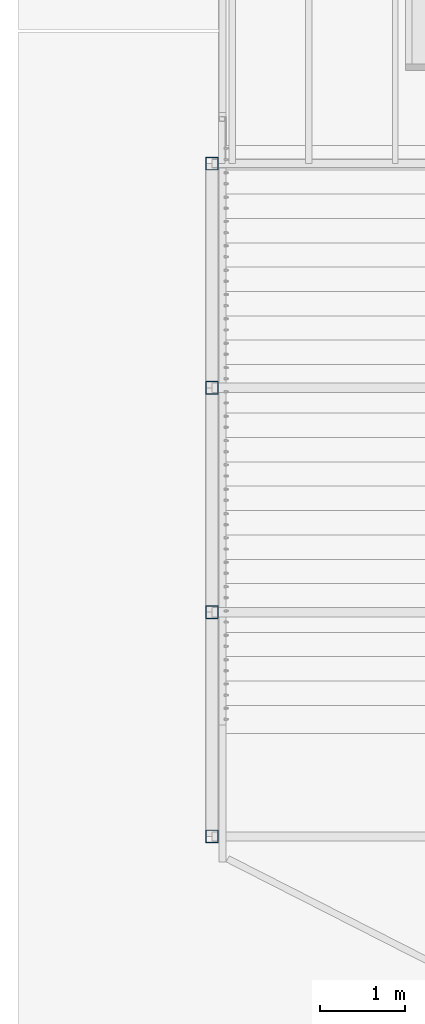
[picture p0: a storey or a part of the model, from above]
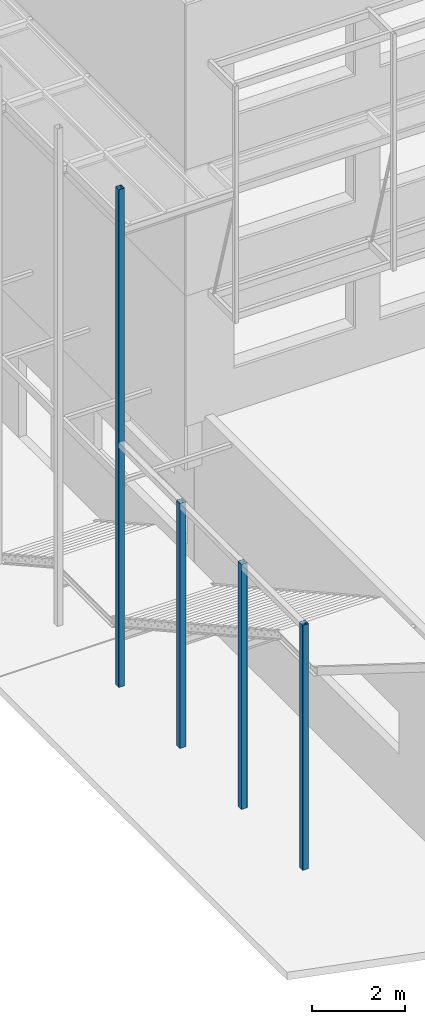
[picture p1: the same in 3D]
Properties of the parts of a building model (IFC2X3), part 1 of 3

# File
Description: ViewDefinition[CoordinationView_V2.0, QuantityTakeOffAddOnView], Option [BaseQuantities:On], Option [GridExport:Off], Option [Assemblies:On], Option [Bolts:On], Option [Rebars:On], Option [PourObjects:Off], Option [Welds:Off], Option [SurfaceTreatments:Off], Option [LocationBy:0], Option [ViewColors:On], Option [SectionedSpine:Off], Option [PropertySets:On], Option [Export all:Off]
File name: Tekla.ifc
Time: 2025-06-02T15:51:15
Author: ETCOMETA\s.laplace
Organization: Structural Designer
Written by: IFC Database Version: Work
Made in: Tekla Structures 2021 Service Pack 13, IFC Export Version: 4.0.0.0 Apr 21 2023

# IfcBuildingStorey, Undefined
In: Undefined
Elevation: 0 mm

# IfcBeam: 160*100 (16)
In: Undefined
Description: 160*100; Material: TIMBER/CHENE
Tekla Commun - Repère de pièce: Po0(?); Repère d'assemblage: Po0(?); Phase: 1402; Classe: 6; Matériau: CHENE; Profil: 160*100; Nom: POUTRE
Tekla Quantités - Hauteur: 160 mm; Largeur: 100 mm
Pset_BeamCommon - LoadBearing: no; Reference: Po0(?)
Name | Niveau bas | Niveau haut | Poids (kg) | Volume (m3) | Surface supérieure totale (m2) | Surface par tonne (m2) | Surface nette (m2) | Longueur (mm) | Length (mm) | OuterSurfaceArea (m2) | NetVolume (m3) | NetWeight (kg)
POUTRE | +156.320 | +156.480 | 278.6 | 0.3 | 1.9 | 36.2 | 10.1 | 19350 | 19350 | 10.094 | 0.3096 | 278.64
POUTRE | +159.620 | +159.780 | 278.6 | 0.3 | 1.9 | 36.2 | 10.1 | 19350 | 19350 | 10.094 | 0.3096 | 278.64
POUTRE | +162.852 | +163.347 | 116.5 | 0.1 | 0 | 36.4 | 4.2 | 8088.5 | 8088.45 | 4.238 | 0.129415 | 116.474
POUTRE | +162.833 | +163.071 | 34.4 | 0 | 0 | 37 | 1.3 | 2390 | 2390 | 1.2748 | 0.03824 | 34.416
POUTRE | +162.935 | +163.349 | 118.1 | 0.1 | 0 | 36.4 | 4.2 | 8200 | 8200 | 4.296 | 0.1312 | 118.08
POUTRE | +162.833 | +163.070 | 36 | 0 | 0 | 37 | 1.3 | 2498.8 | 2498.83 | 1.33139 | 0.0399813 | 35.9832
POUTRE | +162.857 | +163.347 | 116.1 | 0.1 | 0 | 36.4 | 4.2 | 8060 | 8060 | 4.2232 | 0.12896 | 116.064
POUTRE | +156.300 | +156.460 | 28.8 | 0 | 0.2 | 37.2 | 1.1 | 1990 | 1990 | 1.0668 | 0.0318401 | 28.656
POUTRE | +156.320 | +156.480 | 118.1 | 0.1 | 0.8 | 36.4 | 4.2 | 8201 | 8201 | 4.29652 | 0.131216 | 118.094
POUTRE | +156.320 | +156.480 | 118.1 | 0.1 | 0.8 | 36.4 | 4.2 | 8200 | 8200.01 | 4.296 | 0.1312 | 118.08
POUTRE | +162.843 | +163.065 | 28.8 | 0 | 0 | 37.2 | 1.1 | 1990 | 1990 | 1.0668 | 0.0318401 | 28.656
POUTRE | +159.600 | +159.760 | 28.8 | 0 | 0.2 | 37.2 | 1.1 | 1990 | 1990 | 1.0668 | 0.0318401 | 28.656
POUTRE | +159.620 | +159.780 | 118.1 | 0.1 | 0.8 | 36.4 | 4.2 | 8201 | 8201 | 4.29652 | 0.131216 | 118.094
POUTRE | +159.620 | +159.780 | 118.1 | 0.1 | 0.8 | 36.4 | 4.2 | 8200 | 8200.01 | 4.296 | 0.1312 | 118.08
POUTRE | +162.861 | +163.345 | 118.1 | 0.1 | 0 | 36.4 | 4.2 | 8200 | 8200 | 4.296 | 0.1312 | 118.08
POUTRE | +162.933 | +163.347 | 118.1 | 0.1 | 0 | 36.4 | 4.2 | 8200 | 8200 | 4.296 | 0.1312 | 118.08

# IfcBeam: 200*140 (18)
In: Undefined
Description: 200*140; Material: TIMBER/CHENE
Pset_BeamCommon - LoadBearing: no; Reference: Po0(?)
Tekla Commun - Repère de pièce: Po0(?); Repère d'assemblage: Po0(?); Phase: 1402; Classe: 6; Matériau: CHENE; Profil: 200*140; Nom: POUTRE
Tekla Quantités - Volume: 0.1 m3; Surface supérieure totale: 0.5 m2; Surface par tonne: 27.6 m2; Hauteur: 200 mm; Largeur: 140 mm
Name | Niveau bas | Niveau haut | Poids (kg) | Surface nette (m2) | Longueur (mm) = Length (mm) | OuterSurfaceArea (m2) | NetVolume (m3) | NetWeight (kg)
5 x POUTRE | +162.950 | +163.150 | 92.2 | 2.5 | 3660 | 2.5448 | 0.10248 | 92.232
5 x POUTRE | +159.290 | +159.490 | 92.2 | 2.5 | 3660 | 2.5448 | 0.10248 | 92.232
POUTRE | +162.950 | +163.150 | 95.3 | 2.6 | 3780 | 2.6264 | 0.10584 | 95.256
POUTRE | +159.290 | +159.490 | 95.3 | 2.6 | 3780 | 2.6264 | 0.10584 | 95.256
5 x POUTRE | +155.990 | +156.190 | 92.2 | 2.5 | 3660 | 2.5448 | 0.10248 | 92.232
POUTRE | +155.990 | +156.190 | 95.3 | 2.6 | 3780 | 2.6264 | 0.10584 | 95.256

# IfcBeam: 360*160, POUTRE
In: Undefined
Description: 360*160; Material: TIMBER/CHENE
Pset_BeamCommon - LoadBearing: no; Reference: Po0(?)
Tekla Commun - Niveau bas: +164.600; Niveau haut: +164.960; Repère de pièce: Po0(?); Repère d'assemblage: Po0(?); Phase: 1402; Classe: 6; Matériau: CHENE; Profil: 360*160; Nom: POUTRE
Tekla Quantités - Poids: 419.9 kg; Volume: 0.5 m3; Surface supérieure totale: 1.2 m2; Surface par tonne: 20.3 m2; Surface nette: 8.5 m2; Hauteur: 360 mm; Largeur: 160 mm; Longueur: 8100 mm
BaseQuantities - Length: 8100 mm; OuterSurfaceArea: 8.5392 m2; NetVolume: 0.46656 m3; NetWeight: 419.904 kg

# IfcBeam: 360*240 (10)
In: Undefined
Description: 360*240; Material: TIMBER/CHENE
Pset_BeamCommon - LoadBearing: no; Reference: Po0(?)
Tekla Commun - Repère de pièce: Po0(?); Repère d'assemblage: Po0(?); Phase: 1402; Classe: 6; Matériau: CHENE; Profil: 360*240; Nom: POUTRE
Tekla Quantités - Hauteur: 360 mm; Largeur: 240 mm
Name | Niveau bas | Niveau haut | Poids (kg) | Volume (m3) | Surface supérieure totale (m2) | Surface par tonne (m2) | Surface nette (m2) | Longueur (mm) | Length (mm) | OuterSurfaceArea (m2) | NetVolume (m3) | NetWeight (kg)
POUTRE | +156.000 | +156.360 | 1504.7 | 1.7 | 4.6 | 15.5 | 23.4 | 19350 | 19350 | 23.3928 | 1.67184 | 1504.66
POUTRE | +159.300 | +159.660 | 1504.7 | 1.7 | 4.6 | 15.5 | 23.4 | 19350 | 19350 | 23.3928 | 1.67184 | 1504.66
POUTRE | +162.651 | +163.346 | 637.6 | 0.7 | 0 | 15.7 | 10 | 8200 | 8200 | 10.0128 | 0.70848 | 637.632
2 x POUTRE | +162.630 | +163.070 | 201.4 | 0.2 | 0 | 16.3 | 3.3 | 2590 | 2590 | 3.2808 | 0.223776 | 201.398
POUTRE | +162.736 | +163.350 | 637.6 | 0.7 | 0 | 15.7 | 10 | 8200 | 8200 | 10.0128 | 0.70848 | 637.632
POUTRE | +162.657 | +163.346 | 626.7 | 0.7 | 0 | 15.7 | 9.8 | 8060 | 8060 | 9.8448 | 0.696384 | 626.746
POUTRE | +162.640 | +163.068 | 170.4 | 0.2 | 0 | 16.5 | 2.8 | 2191 | 2191.05 | 2.80206 | 0.189307 | 170.376
POUTRE | +162.661 | +163.345 | 637.6 | 0.7 | 0 | 15.7 | 10 | 8200 | 8200 | 10.0128 | 0.70848 | 637.632
POUTRE | +162.734 | +163.347 | 637.6 | 0.7 | 0 | 15.7 | 10 | 8200 | 8200 | 10.0128 | 0.70848 | 637.632

# IfcBeam: 480*240 (2)
In: Undefined
Description: 480*240; Material: TIMBER/CHENE
Pset_BeamCommon - LoadBearing: no; Reference: Po0(?)
Tekla Commun - Repère de pièce: Po0(?); Repère d'assemblage: Po0(?); Phase: 1402; Classe: 6; Matériau: CHENE; Profil: 480*240; Nom: POUTRE
Tekla Quantités - Poids: 1964.7 kg; Volume: 2.2 m3; Surface supérieure totale: 4.5 m2; Surface par tonne: 14 m2; Surface nette: 27.5 m2; Hauteur: 480 mm; Largeur: 240 mm; Longueur: 18950 mm
BaseQuantities - Length: 18950 mm; OuterSurfaceArea: 27.5184 m2; NetVolume: 2.18304 m3; NetWeight: 1964.74 kg
Name | Niveau bas | Niveau haut
POUTRE | +156.000 | +156.480
POUTRE | +159.300 | +159.780

# IfcBeam: 520*140 (6)
In: Undefined
Description: 520*140; Material: TIMBER/CHENE
Pset_BeamCommon - LoadBearing: no; Reference: Po0(?)
Tekla Commun - Niveau bas: +162.950; Niveau haut: +163.470; Repère de pièce: Po0(?); Repère d'assemblage: Po0(?); Phase: 1402; Classe: 6; Matériau: CHENE; Profil: 520*140; Nom: POUTRE
Tekla Quantités - Volume: 0.3 m3; Surface supérieure totale: 0.5 m2; Surface par tonne: 20.8 m2; Hauteur: 520 mm; Largeur: 140 mm
Name | Poids (kg) | Surface nette (m2) | Longueur (mm) = Length (mm) | OuterSurfaceArea (m2) | NetVolume (m3) | NetWeight (kg)
5 x POUTRE | 239.8 | 5 | 3660 | 4.9768 | 0.266448 | 239.803
POUTRE | 247.7 | 5.2 | 3780 | 5.1352 | 0.275184 | 247.666

# IfcBeam: 560*140 (12)
In: Undefined
Description: 560*140; Material: TIMBER/CHENE
Pset_BeamCommon - LoadBearing: no; Reference: Po0(?)
Tekla Commun - Repère de pièce: Po0(?); Repère d'assemblage: Po0(?); Phase: 1402; Classe: 6; Matériau: CHENE; Profil: 560*140; Nom: POUTRE
Tekla Quantités - Volume: 0.3 m3; Surface supérieure totale: 0.5 m2; Surface par tonne: 20.5 m2; Surface nette: 5.3 m2; Hauteur: 560 mm; Largeur: 140 mm
Name | Niveau bas | Niveau haut | Poids (kg) | Longueur (mm) = Length (mm) | OuterSurfaceArea (m2) | NetVolume (m3) | NetWeight (kg)
5 x POUTRE | +159.290 | +159.850 | 258.2 | 3660 | 5.2808 | 0.286944 | 258.25
POUTRE | +159.290 | +159.850 | 266.7 | 3780 | 5.4488 | 0.296352 | 266.717
5 x POUTRE | +155.990 | +156.550 | 258.2 | 3660 | 5.2808 | 0.286944 | 258.25
POUTRE | +155.990 | +156.550 | 266.7 | 3780 | 5.4488 | 0.296352 | 266.717

# IfcBeam: 800*280, POUTRE
In: Undefined
Description: 800*280; Material: TIMBER/CHENE
Pset_BeamCommon - LoadBearing: no; Reference: Po0(?)
Tekla Commun - Niveau bas: +162.400; Niveau haut: +163.200; Repère de pièce: Po0(?); Repère d'assemblage: Po0(?); Phase: 1402; Classe: 6; Matériau: CHENE; Profil: 800*280; Nom: POUTRE
Tekla Quantités - Poids: 1633 kg; Volume: 1.7 m3; Surface supérieure totale: 2.3 m2; Surface par tonne: 11 m2; Surface nette: 17.9 m2; Hauteur: 800 mm; Largeur: 280 mm; Longueur: 8100 mm
BaseQuantities - Length: 8100 mm; OuterSurfaceArea: 17.944 m2; NetVolume: 1.8144 m3; NetWeight: 1632.96 kg

# IfcBeam: IPE140 (47)
In: Undefined
Description: IPE140; Material: STEEL/S275JR
Pset_BeamCommon - LoadBearing: no; Reference: A0(?)
Tekla Commun - Repère de pièce: A0(?); Repère d'assemblage: A0(?); Phase: 301; Classe: 3; Matériau: S275JR; Profil: IPE140
Tekla Quantités - Volume: 0 m3; Surface par tonne: 42.8 m2; Hauteur: 140 mm; Largeur: 73 mm
Name | Niveau bas | Niveau haut | Nom | Poids (kg) | Surface supérieure totale (m2) | Surface nette (m2) | Longueur (mm) | Length (mm) | OuterSurfaceArea (m2) | NetVolume (m3) | NetWeight (kg)
SOLIVE | +150.730 | +150.870 | SOLIVE | 16.8 | 0.1 | 0.7 | 1307.2 | 1307.16 | 0.720245 | 0.00209216 | 16.4235
POUTRE | +148.335 | +148.475 | POUTRE | 22.4 | 0.1 | 0.9 | 1740 | 1740 | 0.95874 | 0.00278494 | 21.8618
POUTRE | +148.335 | +148.475 | POUTRE | 22.4 | 0.1 | 0.9 | 1747.5 | 1747.5 | 0.962872 | 0.00279694 | 21.956
2 x SOLIVE | +159.830 | +159.970 | SOLIVE | 33.9 | 0.2 | 1.4 | 2625 | 2625 | 1.44637 | 0.00420142 | 32.9811
4 x SOLIVE | +156.530 | +156.670 | SOLIVE | 33.9 | 0.2 | 1.4 | 2625 | 2625 | 1.44637 | 0.00420142 | 32.9811
SOLIVE | +156.530 | +156.670 | SOLIVE | 32.8 | 0.2 | 1.4 | 2550 | 2550 | 1.40505 | 0.00408138 | 32.0388
4 x POUTRE | +156.530 | +156.670 | POUTRE | 33.9 | 0.2 | 1.4 | 2625 | 2625 | 1.44637 | 0.00420142 | 32.9811
2 x POUTRE | +156.530 | +156.670 | POUTRE | 39.9 | 0.2 | 1.7 | 3100 | 3100 | 1.7081 | 0.00496167 | 38.9491
8 x SOLIVE | +153.230 | +153.370 | SOLIVE | 33.9 | 0.2 | 1.4 | 2625 | 2625 | 1.44637 | 0.00420142 | 32.9811
4 x POUTRE | +153.230 | +153.370 | POUTRE | 33.9 | 0.2 | 1.4 | 2625 | 2625 | 1.44637 | 0.00420142 | 32.9811
2 x POUTRE | +153.230 | +153.370 | POUTRE | 39.9 | 0.2 | 1.7 | 3100 | 3100 | 1.7081 | 0.00496167 | 38.9491
SOLIVE | +149.930 | +150.070 | SOLIVE | 26 | 0.1 | 1.1 | 2020 | 2020 | 1.11302 | 0.00323309 | 25.3798
SOLIVE | +149.930 | +150.070 | SOLIVE | 33.9 | 0.2 | 1.4 | 2625 | 2625 | 1.44637 | 0.00420142 | 32.9811
SOLIVE | +149.930 | +150.070 | SOLIVE | 32.8 | 0.2 | 1.4 | 2550 | 2550 | 1.40505 | 0.00408138 | 32.0388
2 x SOLIVE | +159.830 | +159.970 | SOLIVE | 33.9 | 0.2 | 1.4 | 2626 | 2626 | 1.44693 | 0.00420302 | 32.9937
SOLIVE | +159.830 | +159.970 | SOLIVE | 31.5 | 0.2 | 1.4 | 2447 | 2447 | 1.3483 | 0.00391652 | 30.7447
SOLIVE | +159.830 | +159.970 | SOLIVE | 28.8 | 0.2 | 1.3 | 2238 | 2238 | 1.23314 | 0.00358201 | 28.1188
3 x SOLIVE | +150.730 | +150.870 | SOLIVE | 33.9 | 0.2 | 1.4 | 2625 | 2625 | 1.44637 | 0.00420142 | 32.9811
SOLIVE | +156.530 | +156.670 | SOLIVE | 33.4 | 0.2 | 1.4 | 2592.9 | 2592.9 | 1.42869 | 0.00407696 | 32.0041
SOLIVE | +156.530 | +156.670 | SOLIVE | 32.6 | 0.2 | 1.4 | 2530 | 2530 | 1.39403 | 0.00404937 | 31.7875
SOLIVE | +156.530 | +156.670 | SOLIVE | 39.9 | 0.2 | 1.7 | 3100 | 3100 | 1.7081 | 0.00496167 | 38.9491
SOLIVE | +156.530 | +156.670 | SOLIVE | 39.7 | 0.2 | 1.7 | 3087 | 3087.05 | 1.70096 | 0.00491172 | 38.557
SOLIVE | +156.530 | +156.670 | SOLIVE | 33.4 | 0.2 | 1.4 | 2592.9 | 2593.05 | 1.42877 | 0.00408009 | 32.0287
2 x SOLIVE | +153.230 | +153.370 | SOLIVE | 39.9 | 0.2 | 1.7 | 3100 | 3100 | 1.7081 | 0.00496167 | 38.9491

# IfcBeam: IPE220 (22)
In: Undefined
Description: IPE220; Material: STEEL/S275JR
Pset_BeamCommon - LoadBearing: no
Tekla Commun - Repère d'assemblage: A0(?); Classe: 3; Matériau: S275JR; Profil: IPE220
Tekla Quantités - Volume: 0 m3; Surface par tonne: 32.3 m2; Hauteur: 220 mm; Largeur: 110 mm
Name | Reference = Repère de pièce | Niveau bas | Niveau haut | Phase | Nom | Poids (kg) | Surface supérieure totale (m2) | Surface nette (m2) | Longueur (mm) | Length (mm) | OuterSurfaceArea (m2) | NetVolume (m3) | NetWeight (kg)
3 x POUTRE | A0(?) | +156.450 | +156.670 | 301 | POUTRE | 53 | 0.2 | 1.7 | 2020 | 2020 | 1.71296 | 0.00649115 | 50.9555
3 x POUTRE | A0(?) | +153.150 | +153.370 | 301 | POUTRE | 53 | 0.2 | 1.7 | 2020 | 2020 | 1.71296 | 0.00649115 | 50.9555
POUTRE | A0(?) | +148.955 | +149.175 | 303 | POUTRE | 71.7 | 0.3 | 2.5 | 2733.4 | 2733.43 | 2.31795 | 0.00878371 | 68.9521
POUTRE | A0(?) | +152.110 | +152.330 | 303 | POUTRE | 71.7 | 0.3 | 2.5 | 2733.4 | 2733.43 | 2.31795 | 0.00878371 | 68.9521
POUTRE | A0(?) | +150.645 | +150.865 | 303 | POUTRE | 71.7 | 0.3 | 2.5 | 2733.4 | 2733.43 | 2.31795 | 0.00878371 | 68.9521
POUTRE | A0(?) | +149.180 | +149.400 | 303 | POUTRE | 71.7 | 0.3 | 2.5 | 2733.4 | 2733.43 | 2.31795 | 0.00878371 | 68.9521
POUTRE | A0(?) | +153.150 | +153.370 | 303 | POUTRE | 71.7 | 0.3 | 2.5 | 2733.4 | 2733.43 | 2.31795 | 0.00878371 | 68.9521
CONSOLE | A0(?) | +159.750 | +159.970 | 301 | CONSOLE | 73.5 | 0.3 | 2.5 | 2803.4 | 2803.43 | 2.37731 | 0.00900865 | 70.7179
3 x CONSOLE | A0(?) | +159.750 | +159.970 | 303 | CONSOLE | 71.7 | 0.3 | 2.5 | 2735 | 2735 | 2.31928 | 0.00878876 | 68.9918
SOLIVE | 0(?) | +150.650 | +150.870 | 301 | SOLIVE | 56.9 | 0.2 | 2 | 2170 | 2170 | 1.84016 | 0.00697316 | 54.7393
SOLIVE | A0(?) | +156.450 | +156.670 | 301 | SOLIVE | 54.9 | 0.2 | 1.7 | 2095 | 2095 | 1.77656 | 0.00673216 | 52.8474
SOLIVE | A0(?) | +156.450 | +156.670 | 301 | SOLIVE | 53 | 0.2 | 1.7 | 2020 | 2020 | 1.71296 | 0.00649115 | 50.9555
SOLIVE | 0(?) | +156.450 | +156.670 | 301 | SOLIVE | 52.4 | 0.2 | 1.7 | 2000 | 2000 | 1.696 | 0.00642688 | 50.451
2 x SOLIVE | A0(?) | +153.150 | +153.370 | 301 | SOLIVE | 54.9 | 0.2 | 1.7 | 2095 | 2095 | 1.77656 | 0.00673216 | 52.8474
SOLIVE | A0(?) | +153.150 | +153.370 | 301 | SOLIVE | 53 | 0.2 | 1.7 | 2020 | 2020 | 1.71296 | 0.00649115 | 50.9555

# IfcBeam: IPE240 (12)
In: Undefined
Description: IPE240; Material: STEEL/S275JR
Pset_BeamCommon - LoadBearing: no; Reference: 0(?)
Tekla Commun - Repère de pièce: 0(?); Phase: 301; Classe: 3; Matériau: S275JR; Profil: IPE240
Tekla Quantités - Volume: 0 m3; Surface par tonne: 30 m2; Hauteur: 240 mm; Largeur: 120 mm
Name | Niveau bas | Niveau haut | Repère d'assemblage | Nom | Poids (kg) | Surface supérieure totale (m2) | Surface nette (m2) | Longueur (mm) | Length (mm) | OuterSurfaceArea (m2) | NetVolume (m3) | NetWeight (kg)
CONSOLE | +159.730 | +159.970 | A0(?) | CONSOLE | 60.9 | 0.2 | 2 | 1985 | 1985 | 1.83017 | 0.00738118 | 57.9423
2 x CONSOLE | +156.430 | +156.670 | A0(?) | CONSOLE | 60.9 | 0.2 | 2 | 1985 | 1985 | 1.83017 | 0.00738118 | 57.9423
2 x CONSOLE | +153.130 | +153.370 | A0(?) | CONSOLE | 60.9 | 0.2 | 2 | 1985 | 1985 | 1.83017 | 0.00738118 | 57.9423
CONSOLE | +149.830 | +150.070 | A0(?) | CONSOLE | 58.6 | 0.2 | 1.7 | 1910 | 1910 | 1.76102 | 0.0071023 | 55.753
SOLIVE | +159.730 | +159.970 | A0(?) | SOLIVE | 62.4 | 0.2 | 2 | 2033.6 | 2033.57 | 1.87495 | 0.00756179 | 59.36
SOLIVE | +150.630 | +150.870 | P0(?) | SOLIVE | 74.7 | 0.3 | 2.3 | 2435 | 2435 | 2.24507 | 0.0090545 | 71.0778
SOLIVE | +156.430 | +156.670 | A0(?) | SOLIVE | 61.4 | 0.2 | 2 | 2000 | 2000 | 1.844 | 0.00743696 | 58.3801
SOLIVE | +156.430 | +156.670 | P0(?) | SOLIVE | 59.5 | 0.2 | 1.7 | 1938.6 | 1938.57 | 1.78736 | 0.00720853 | 56.587
SOLIVE | +153.130 | +153.370 | A0(?) | SOLIVE | 61.4 | 0.2 | 2 | 2000 | 2000 | 1.844 | 0.00743696 | 58.3801
SOLIVE | +153.130 | +153.370 | P0(?) | SOLIVE | 59.8 | 0.2 | 2 | 1948.6 | 1948.57 | 1.79658 | 0.00724572 | 56.8789

# IfcBeam: L100*10 (7)
In: Undefined
Description: L100*10; Material: STEEL/S235JR
Pset_BeamCommon - LoadBearing: no
Tekla Commun - Phase: 301; Classe: 3; Matériau: S235JR; Profil: L100*10; Nom: CORNIERE
Tekla Quantités - Volume: 0 m3; Surface supérieure totale: 0 m2; Surface par tonne: 25.9 m2; Surface nette: 0.1 m2; Hauteur: 100 mm; Largeur: 100 mm
Name | Reference = Repère de pièce | Niveau bas | Niveau haut | Repère d'assemblage | Poids (kg) | Longueur (mm) = Length (mm) | OuterSurfaceArea (m2) | NetVolume (m3) | NetWeight (kg)
CORNIERE | A0(?) | +156.480 | +156.640 | A0(?) | 2.4 | 160 | 0.0624 | 0.000304 | 2.3864
4 x CORNIERE | 0(?) | +156.480 | +156.640 | P0(?) | 2.4 | 160 | 0.0624 | 0.000304 | 2.3864
CORNIERE | 0(?) | +156.420 | +156.620 | P0(?) | 3 | 200 | 0.078 | 0.00038 | 2.983
CORNIERE | 0(?) | +159.800 | +159.960 | A0(?) | 2.4 | 160 | 0.0624 | 0.000304 | 2.3864

# IfcBeam: L50*5 (61)
In: Undefined
Description: L50*5
Pset_BeamCommon - LoadBearing: no; Reference: A0(?)
Tekla Commun - Repère de pièce: A0(?); Repère d'assemblage: A0(?); Phase: 301; Classe: 3; Profil: L50*5; Nom: STAB
Tekla Quantités - Volume: 0 m3; Surface par tonne: 51.5 m2; Hauteur: 50 mm; Largeur: 50 mm
Name | Material | Niveau bas | Niveau haut | Matériau | Poids (kg) | Surface supérieure totale (m2) | Surface nette (m2) | Longueur (mm) | Length (mm) | OuterSurfaceArea (m2) | NetVolume (m3) | NetWeight (kg)
STAB | STEEL/S275JR | +156.458 | +156.508 | S275JR | 5.7 | 0 | 0.4 | 1520.7 | 1520.75 | 0.295025 | 0.000722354 | 5.67048
STAB | STEEL/S275JR | +156.458 | +156.508 | S275JR | 5.2 | 0 | 0.4 | 1387.7 | 1387.65 | 0.269205 | 0.000659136 | 5.17422
STAB | STEEL/S275JR | +156.458 | +156.508 | S275JR | 5.5 | 0 | 0.4 | 1471.4 | 1471.37 | 0.285446 | 0.0006989 | 5.48637
STAB | STEEL/S275JR | +150.680 | +150.730 | S275JR | 8.3 | 0.1 | 0.4 | 2213.6 | 2213.59 | 0.429437 | 0.00105146 | 8.25394
2 x STAB | STEEL/S235JR | +159.780 | +159.830 | S235JR | 12.7 | 0.2 | 0.7 | 3372 | 3372 | 0.654168 | 0.0016017 | 12.5734
4 x STAB | STEEL/S235JR | +156.480 | +156.530 | S235JR | 12.7 | 0.2 | 0.7 | 3372 | 3372 | 0.654168 | 0.0016017 | 12.5734
2 x STAB | STEEL/S235JR | +156.480 | +156.530 | S235JR | 13.1 | 0.2 | 0.7 | 3463.9 | 3463.94 | 0.672005 | 0.00164537 | 12.9162
STAB | STEEL/S235JR | +156.507 | +156.557 | S235JR | 13.1 | 0.2 | 0.7 | 3463.9 | 3463.94 | 0.672005 | 0.00164537 | 12.9162
STAB | STEEL/S235JR | +156.507 | +156.557 | S235JR | 12.3 | 0.2 | 0.7 | 3266.8 | 3266.82 | 0.633764 | 0.00155174 | 12.1812
4 x STAB | STEEL/S235JR | +156.480 | +156.530 | S235JR | 14.3 | 0.2 | 0.7 | 3784 | 3784.03 | 0.734102 | 0.00179742 | 14.1097
4 x STAB | STEEL/S235JR | +153.180 | +153.230 | S235JR | 12.7 | 0.2 | 0.7 | 3372 | 3372 | 0.654168 | 0.0016017 | 12.5734
4 x STAB | STEEL/S235JR | +153.180 | +153.230 | S235JR | 13.1 | 0.2 | 0.7 | 3463.9 | 3463.94 | 0.672005 | 0.00164537 | 12.9162
4 x STAB | STEEL/S235JR | +153.180 | +153.230 | S235JR | 14.3 | 0.2 | 0.7 | 3784 | 3784.03 | 0.734102 | 0.00179742 | 14.1097
2 x STAB | STEEL/S235JR | +149.880 | +149.930 | S235JR | 12.7 | 0.2 | 0.7 | 3372 | 3372 | 0.654168 | 0.0016017 | 12.5734
2 x STAB | STEEL/S275JR | +159.780 | +159.830 | S275JR | 12.7 | 0.2 | 0.7 | 3372 | 3372 | 0.654168 | 0.0016017 | 12.5734
2 x STAB | STEEL/S275JR | +150.680 | +150.730 | S275JR | 12.7 | 0.2 | 0.7 | 3372 | 3372 | 0.654168 | 0.0016017 | 12.5734
2 x STAB | STEEL/S275JR | +156.480 | +156.530 | S275JR | 12.7 | 0.2 | 0.7 | 3372 | 3372 | 0.654168 | 0.0016017 | 12.5734
STAB | STEEL/S275JR | +156.458 | +156.508 | S275JR | 11.2 | 0 | 0.7 | 3010.5 | 3010.48 | 0.584032 | 0.00142998 | 11.2253
4 x STAB | STEEL/S275JR | +153.180 | +153.230 | S275JR | 12.7 | 0.2 | 0.7 | 3372 | 3372 | 0.654168 | 0.0016017 | 12.5734
2 x STAB | STEEL/S275JR | +150.680 | +150.730 | S275JR | 13.1 | 0.2 | 0.7 | 3463.9 | 3463.94 | 0.672005 | 0.00164537 | 12.9162
STAB | STEEL/S275JR | +156.458 | +156.508 | S275JR | 11 | 0 | 0.7 | 2908.9 | 2908.88 | 0.564323 | 0.00138172 | 10.8465
STAB | STEEL/S275JR | +156.458 | +156.508 | S275JR | 5.3 | 0 | 0.4 | 1395.9 | 1395.86 | 0.270796 | 0.000663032 | 5.2048
2 x STAB | STEEL/S275JR | +156.480 | +156.530 | S275JR | 13.1 | 0.2 | 0.7 | 3463.9 | 3463.94 | 0.672005 | 0.00164537 | 12.9162
4 x STAB | STEEL/S275JR | +156.480 | +156.530 | S275JR | 14.3 | 0.2 | 0.7 | 3784 | 3784.03 | 0.734102 | 0.00179742 | 14.1097
4 x STAB | STEEL/S275JR | +153.180 | +153.230 | S275JR | 13.1 | 0.2 | 0.7 | 3463.9 | 3463.94 | 0.672005 | 0.00164537 | 12.9162
4 x STAB | STEEL/S275JR | +153.180 | +153.230 | S275JR | 14.3 | 0.2 | 0.7 | 3784 | 3784.03 | 0.734102 | 0.00179742 | 14.1097

# IfcBeam: L80*8 (9)
In: Undefined
Description: L80*8; Material: STEEL/S235JR
Tekla Commun - Repère de pièce: 0(?); Classe: 99; Matériau: S235JR; Profil: L80*8; Nom: CORNIERE
Tekla Quantités - Poids: 1.4 kg; Volume: 0 m3; Surface supérieure totale: 0 m2; Surface par tonne: 32.2 m2; Surface nette: 0.1 m2; Hauteur: 80 mm; Largeur: 80 mm; Longueur: 150 mm
Pset_BeamCommon - LoadBearing: no; Reference: 0(?)
BaseQuantities - Length: 150 mm; OuterSurfaceArea: 0.04665 m2; NetVolume: 0.0001824 m3; NetWeight: 1.43184 kg
Name | Niveau bas | Niveau haut | Repère d'assemblage | Phase
CORNIERE | +156.485 | +156.635 | L0(?) | 301
CORNIERE | +156.485 | +156.635 | A0(?) | 303
CORNIERE | +149.885 | +150.035 | A0(?) | 301
2 x CORNIERE | +153.185 | +153.335 | A0(?) | 301
2 x CORNIERE | +156.485 | +156.635 | A0(?) | 301
CORNIERE | +150.685 | +150.835 | A0(?) | 301
CORNIERE | +159.785 | +159.935 | A0(?) | 301

# IfcBeam: PL10*10 (212)
In: Undefined
Description: PL10*10; Material: STEEL/S235JR
Pset_BeamCommon - LoadBearing: no; Reference: 0(?)
Tekla Commun - Repère de pièce: 0(?); Repère d'assemblage: GC0(?); Phase: 601; Classe: 13; Matériau: S235JR; Profil: PL10*10; Nom: LISSE
Tekla Quantités - Poids: 0.7 kg; Volume: 0 m3; Surface supérieure totale: 0 m2; Surface nette: 0 m2; Hauteur: 10 mm; Largeur: 10 mm
Name | Niveau bas | Niveau haut | Surface par tonne (m2) | Longueur (mm) | Length (mm) | OuterSurfaceArea (m2) | NetVolume (m3) | NetWeight (kg)
32 x LISSE | +160.120 | +160.990 | 51.2 | 870 | 870 | 0.035 | 0.000087 | 0.68295
90 x LISSE | +156.820 | +157.690 | 51.2 | 870 | 870 | 0.035 | 0.000087 | 0.68295
LISSE | +159.950 | +160.775 | 51.3 | 825.6 | 825.551 | 0.0330295 | 0.0000820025 | 0.643719
LISSE | +159.889 | +160.715 | 51.3 | 825.6 | 825.551 | 0.0330295 | 0.0000820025 | 0.643719
LISSE | +156.985 | +157.810 | 51.3 | 825.6 | 825.551 | 0.0330295 | 0.0000820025 | 0.643719
LISSE | +157.045 | +157.871 | 51.3 | 825.6 | 825.551 | 0.0330295 | 0.0000820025 | 0.643719
LISSE | +157.106 | +157.932 | 51.3 | 825.6 | 825.551 | 0.0330295 | 0.0000820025 | 0.643719
LISSE | +157.167 | +157.993 | 51.3 | 825.6 | 825.551 | 0.0330295 | 0.0000820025 | 0.643719
LISSE | +157.228 | +158.053 | 51.3 | 825.6 | 825.551 | 0.0330295 | 0.0000820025 | 0.643719
LISSE | +157.289 | +158.114 | 51.3 | 825.6 | 825.551 | 0.0330295 | 0.0000820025 | 0.643719
LISSE | +157.349 | +158.175 | 51.3 | 825.6 | 825.551 | 0.0330295 | 0.0000820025 | 0.643719
LISSE | +157.410 | +158.236 | 51.3 | 825.6 | 825.551 | 0.0330295 | 0.0000820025 | 0.643719
LISSE | +157.471 | +158.296 | 51.3 | 825.6 | 825.551 | 0.0330295 | 0.0000820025 | 0.643719
LISSE | +157.592 | +158.418 | 51.3 | 825.6 | 825.551 | 0.0330295 | 0.0000820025 | 0.643719
LISSE | +157.653 | +158.479 | 51.3 | 825.6 | 825.551 | 0.0330295 | 0.0000820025 | 0.643719
LISSE | +157.714 | +158.540 | 51.3 | 825.6 | 825.551 | 0.0330295 | 0.0000820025 | 0.643719
LISSE | +157.775 | +158.600 | 51.3 | 825.6 | 825.551 | 0.0330295 | 0.0000820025 | 0.643719
LISSE | +157.836 | +158.661 | 51.3 | 825.6 | 825.551 | 0.0330295 | 0.0000820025 | 0.643719
LISSE | +157.896 | +158.722 | 51.3 | 825.6 | 825.551 | 0.0330295 | 0.0000820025 | 0.643719
LISSE | +157.957 | +158.783 | 51.3 | 825.6 | 825.551 | 0.0330295 | 0.0000820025 | 0.643719
LISSE | +158.018 | +158.844 | 51.3 | 825.6 | 825.551 | 0.0330295 | 0.0000820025 | 0.643719
LISSE | +158.079 | +158.904 | 51.3 | 825.6 | 825.551 | 0.0330295 | 0.0000820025 | 0.643719
LISSE | +158.200 | +159.026 | 51.3 | 825.6 | 825.551 | 0.0330295 | 0.0000820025 | 0.643719
LISSE | +158.261 | +159.087 | 51.3 | 825.6 | 825.551 | 0.0330295 | 0.0000820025 | 0.643719
LISSE | +158.322 | +159.148 | 51.3 | 825.6 | 825.551 | 0.0330295 | 0.0000820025 | 0.643719
LISSE | +158.383 | +159.208 | 51.3 | 825.6 | 825.551 | 0.0330295 | 0.0000820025 | 0.643719
LISSE | +158.444 | +159.269 | 51.3 | 825.6 | 825.551 | 0.0330295 | 0.0000820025 | 0.643719
LISSE | +158.504 | +159.330 | 51.3 | 825.6 | 825.551 | 0.0330295 | 0.0000820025 | 0.643719
LISSE | +158.565 | +159.391 | 51.3 | 825.6 | 825.551 | 0.0330295 | 0.0000820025 | 0.643719
LISSE | +158.626 | +159.451 | 51.3 | 825.6 | 825.551 | 0.0330295 | 0.0000820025 | 0.643719
LISSE | +158.687 | +159.512 | 51.3 | 825.6 | 825.551 | 0.0330295 | 0.0000820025 | 0.643719
LISSE | +158.808 | +159.634 | 51.3 | 825.6 | 825.551 | 0.0330295 | 0.0000820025 | 0.643719
LISSE | +158.869 | +159.695 | 51.3 | 825.6 | 825.551 | 0.0330295 | 0.0000820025 | 0.643719
LISSE | +158.930 | +159.755 | 51.3 | 825.6 | 825.551 | 0.0330295 | 0.0000820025 | 0.643719
LISSE | +158.991 | +159.816 | 51.3 | 825.6 | 825.551 | 0.0330295 | 0.0000820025 | 0.643719
LISSE | +159.051 | +159.877 | 51.3 | 825.6 | 825.551 | 0.0330295 | 0.0000820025 | 0.643719
LISSE | +159.112 | +159.938 | 51.3 | 825.6 | 825.551 | 0.0330295 | 0.0000820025 | 0.643719
LISSE | +159.173 | +159.999 | 51.3 | 825.6 | 825.551 | 0.0330295 | 0.0000820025 | 0.643719
LISSE | +159.234 | +160.059 | 51.3 | 825.6 | 825.551 | 0.0330295 | 0.0000820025 | 0.643719
LISSE | +159.295 | +160.120 | 51.3 | 825.6 | 825.551 | 0.0330295 | 0.0000820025 | 0.643719
LISSE | +159.416 | +160.242 | 51.3 | 825.6 | 825.551 | 0.0330295 | 0.0000820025 | 0.643719
LISSE | +159.477 | +160.303 | 51.3 | 825.6 | 825.551 | 0.0330295 | 0.0000820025 | 0.643719
LISSE | +159.538 | +160.363 | 51.3 | 825.6 | 825.551 | 0.0330295 | 0.0000820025 | 0.643719
LISSE | +159.599 | +160.424 | 51.3 | 825.6 | 825.551 | 0.0330295 | 0.0000820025 | 0.643719
LISSE | +159.659 | +160.485 | 51.3 | 825.6 | 825.551 | 0.0330295 | 0.0000820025 | 0.643719
LISSE | +159.720 | +160.546 | 51.3 | 825.6 | 825.551 | 0.0330295 | 0.0000820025 | 0.643719
LISSE | +159.781 | +160.606 | 51.3 | 825.6 | 825.551 | 0.0330295 | 0.0000820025 | 0.643719
LISSE | +159.842 | +160.667 | 51.3 | 825.6 | 825.551 | 0.0330295 | 0.0000820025 | 0.643719
LISSE | +159.902 | +160.728 | 51.3 | 825.6 | 825.551 | 0.0330295 | 0.0000820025 | 0.643719
LISSE | +159.828 | +160.654 | 51.3 | 825.6 | 825.551 | 0.0330295 | 0.0000820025 | 0.643719
LISSE | +159.767 | +160.593 | 51.3 | 825.6 | 825.551 | 0.0330295 | 0.0000820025 | 0.643719
LISSE | +159.707 | +160.532 | 51.3 | 825.6 | 825.551 | 0.0330295 | 0.0000820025 | 0.643719
LISSE | +159.646 | +160.471 | 51.3 | 825.6 | 825.551 | 0.0330295 | 0.0000820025 | 0.643719
LISSE | +159.585 | +160.411 | 51.3 | 825.6 | 825.551 | 0.0330295 | 0.0000820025 | 0.643719
LISSE | +159.524 | +160.350 | 51.3 | 825.6 | 825.551 | 0.0330295 | 0.0000820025 | 0.643719
LISSE | +159.463 | +160.289 | 51.3 | 825.6 | 825.551 | 0.0330295 | 0.0000820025 | 0.643719
LISSE | +159.342 | +160.167 | 51.3 | 825.6 | 825.551 | 0.0330295 | 0.0000820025 | 0.643719
LISSE | +159.281 | +160.107 | 51.3 | 825.6 | 825.551 | 0.0330295 | 0.0000820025 | 0.643719
LISSE | +159.220 | +160.046 | 51.3 | 825.6 | 825.551 | 0.0330295 | 0.0000820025 | 0.643719
LISSE | +159.160 | +159.985 | 51.3 | 825.6 | 825.551 | 0.0330295 | 0.0000820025 | 0.643719
LISSE | +159.099 | +159.924 | 51.3 | 825.6 | 825.551 | 0.0330295 | 0.0000820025 | 0.643719
LISSE | +159.038 | +159.863 | 51.3 | 825.6 | 825.551 | 0.0330295 | 0.0000820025 | 0.643719
LISSE | +158.977 | +159.803 | 51.3 | 825.6 | 825.551 | 0.0330295 | 0.0000820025 | 0.643719
LISSE | +158.916 | +159.742 | 51.3 | 825.6 | 825.551 | 0.0330295 | 0.0000820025 | 0.643719
LISSE | +158.856 | +159.681 | 51.3 | 825.6 | 825.551 | 0.0330295 | 0.0000820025 | 0.643719
LISSE | +158.734 | +159.560 | 51.3 | 825.6 | 825.551 | 0.0330295 | 0.0000820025 | 0.643719
LISSE | +158.673 | +159.499 | 51.3 | 825.6 | 825.551 | 0.0330295 | 0.0000820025 | 0.643719
LISSE | +158.612 | +159.438 | 51.3 | 825.6 | 825.551 | 0.0330295 | 0.0000820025 | 0.643719
LISSE | +158.552 | +159.377 | 51.3 | 825.6 | 825.551 | 0.0330295 | 0.0000820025 | 0.643719
LISSE | +158.491 | +159.316 | 51.3 | 825.6 | 825.551 | 0.0330295 | 0.0000820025 | 0.643719
LISSE | +158.430 | +159.256 | 51.3 | 825.6 | 825.551 | 0.0330295 | 0.0000820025 | 0.643719
LISSE | +158.369 | +159.195 | 51.3 | 825.6 | 825.551 | 0.0330295 | 0.0000820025 | 0.643719
LISSE | +158.308 | +159.134 | 51.3 | 825.6 | 825.551 | 0.0330295 | 0.0000820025 | 0.643719
LISSE | +158.248 | +159.073 | 51.3 | 825.6 | 825.551 | 0.0330295 | 0.0000820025 | 0.643719
LISSE | +158.126 | +158.952 | 51.3 | 825.6 | 825.551 | 0.0330295 | 0.0000820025 | 0.643719
LISSE | +158.065 | +158.891 | 51.3 | 825.6 | 825.551 | 0.0330295 | 0.0000820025 | 0.643719
LISSE | +158.005 | +158.830 | 51.3 | 825.6 | 825.551 | 0.0330295 | 0.0000820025 | 0.643719
LISSE | +157.944 | +158.769 | 51.3 | 825.6 | 825.551 | 0.0330295 | 0.0000820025 | 0.643719
LISSE | +157.883 | +158.708 | 51.3 | 825.6 | 825.551 | 0.0330295 | 0.0000820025 | 0.643719
LISSE | +157.822 | +158.648 | 51.3 | 825.6 | 825.551 | 0.0330295 | 0.0000820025 | 0.643719
LISSE | +157.761 | +158.587 | 51.3 | 825.6 | 825.551 | 0.0330295 | 0.0000820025 | 0.643719
LISSE | +157.701 | +158.526 | 51.3 | 825.6 | 825.551 | 0.0330295 | 0.0000820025 | 0.643719
LISSE | +157.640 | +158.465 | 51.3 | 825.6 | 825.551 | 0.0330295 | 0.0000820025 | 0.643719
LISSE | +157.518 | +158.344 | 51.3 | 825.6 | 825.551 | 0.0330295 | 0.0000820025 | 0.643719
LISSE | +157.457 | +158.283 | 51.3 | 825.6 | 825.551 | 0.0330295 | 0.0000820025 | 0.643719
LISSE | +157.397 | +158.222 | 51.3 | 825.6 | 825.551 | 0.0330295 | 0.0000820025 | 0.643719
LISSE | +157.336 | +158.161 | 51.3 | 825.6 | 825.551 | 0.0330295 | 0.0000820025 | 0.643719
LISSE | +157.275 | +158.101 | 51.3 | 825.6 | 825.551 | 0.0330295 | 0.0000820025 | 0.643719
LISSE | +157.214 | +158.040 | 51.3 | 825.6 | 825.551 | 0.0330295 | 0.0000820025 | 0.643719
LISSE | +157.153 | +157.979 | 51.3 | 825.6 | 825.551 | 0.0330295 | 0.0000820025 | 0.643719
LISSE | +157.093 | +157.918 | 51.3 | 825.6 | 825.551 | 0.0330295 | 0.0000820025 | 0.643719
LISSE | +157.032 | +157.857 | 51.3 | 825.6 | 825.551 | 0.0330295 | 0.0000820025 | 0.643719

# IfcBeam: PL10*50 (10)
In: Undefined
Description: PL10*50; Material: STEEL/S235JR
Pset_BeamCommon - LoadBearing: no; Reference: 0(?)
Tekla Commun - Repère de pièce: 0(?); Repère d'assemblage: GC0(?); Phase: 601; Classe: 13; Matériau: S235JR; Profil: PL10*50
Tekla Quantités - Volume: 0 m3; Surface nette: 0.4 m2; Hauteur: 50 mm; Largeur: 10 mm
Name | Niveau bas | Niveau haut | Nom | Poids (kg) | Surface supérieure totale (m2) | Surface par tonne (m2) | Longueur (mm) = Length (mm) | OuterSurfaceArea (m2) | NetVolume (m3) | NetWeight (kg)
2 x LISSE | +156.810 | +156.820 | LISSE | 9.7 | 0.1 | 30.9 | 2500 | 0.2982 | 0.00123 | 9.6555
2 x MAIN_COURANTE | +157.690 | +157.700 | MAIN_COURANTE | 10 | 0.1 | 30.7 | 2540 | 0.3058 | 0.00127 | 9.9695
2 x LISSE | +156.810 | +156.820 | LISSE | 11.2 | 0.1 | 30.7 | 2900 | 0.3462 | 0.00143 | 11.2255
2 x MAIN_COURANTE | +157.690 | +157.700 | MAIN_COURANTE | 11.5 | 0.1 | 30.7 | 2940 | 0.3538 | 0.00147 | 11.5395
LISSE | +160.110 | +160.120 | LISSE | 14.5 | 0.2 | 30.7 | 3750 | 0.4468 | 0.001845 | 14.4832
MAIN_COURANTE | +160.990 | +161.000 | MAIN_COURANTE | 14.9 | 0.2 | 30.6 | 3790 | 0.4558 | 0.001895 | 14.8758

# IfcBeam: TUBE-C-100*100*4 (11)
In: Undefined
Description: TUBE-C-100*100*4; Material: STEEL/S275JR
Pset_BeamCommon - LoadBearing: no
Tekla Commun - Repère d'assemblage: A0(?); Classe: 3; Matériau: S275JR; Profil: TUBE-C-100*100*4; Nom: CONSOLE
Tekla Quantités - Volume: 0 m3; Surface par tonne: 33 m2; Hauteur: 100 mm; Largeur: 100 mm
Name | Reference = Repère de pièce | Niveau bas | Niveau haut | Phase | Poids (kg) | Surface supérieure totale (m2) | Surface nette (m2) | Longueur (mm) | Length (mm) | OuterSurfaceArea (m2) | NetVolume (m3) | NetWeight (kg)
2 x CONSOLE | A0(?) | +153.270 | +153.370 | 303 | 32 | 0.3 | 1.1 | 2733.4 | 2733.43 | 1.0551 | 0.00419855 | 32.9586
2 x CONSOLE | A0(?) | +153.270 | +153.370 | 303 | 32 | 0.3 | 1.1 | 2735 | 2735 | 1.05571 | 0.00420096 | 32.9775
7 x CONSOLE | 0(?) | +156.490 | +162.680 | 301 | 72.4 | 0 | 2.5 | 6190 | 6190 | 2.38934 | 0.00950784 | 74.6365

# IfcBeam: TUBE-C-150*150*5 (3)
In: Undefined
Description: TUBE-C-150*150*5; Material: STEEL/S275JR
Pset_BeamCommon - LoadBearing: no; Reference: A0(?)
Tekla Commun - Niveau bas: +154.250; Niveau haut: +154.400; Repère de pièce: A0(?); Repère d'assemblage: A0(?); Phase: 301; Classe: 3; Matériau: S275JR; Profil: TUBE-C-150*150*5; Nom: SOLIVE
Tekla Quantités - Poids: 58.4 kg; Volume: 0 m3; Surface supérieure totale: 0.3 m2; Surface par tonne: 25.9 m2; Surface nette: 1.6 m2; Hauteur: 150 mm; Largeur: 150 mm; Longueur: 2626 mm
BaseQuantities - Length: 2626 mm; OuterSurfaceArea: 1.51783 m2; NetVolume: 0.0076154 m3; NetWeight: 59.7809 kg

# IfcBeam: TUBE-C-40*40*3 (6)
In: Undefined
Description: TUBE-C-40*40*3; Material: STEEL/S275JR
Pset_BeamCommon - LoadBearing: no; Reference: A0(?)
Tekla Commun - Repère de pièce: A0(?); Repère d'assemblage: A0(?); Phase: 301; Classe: 3; Matériau: S275JR; Profil: TUBE-C-40*40*3; Nom: STAB
Tekla Quantités - Poids: 7.1 kg; Volume: 0 m3; Surface supérieure totale: 0.1 m2; Surface par tonne: 45.1 m2; Surface nette: 0.4 m2; Hauteur: 40 mm; Largeur: 40 mm
Name | Niveau bas | Niveau haut | Longueur (mm) | Length (mm) | OuterSurfaceArea (m2) | NetVolume (m3) | NetWeight (kg)
2 x STAB | +162.570 | +162.610 | 2147.7 | 2147.67 | 0.320003 | 0.000953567 | 7.4855
2 x STAB | +156.560 | +156.600 | 2147.7 | 2147.67 | 0.320003 | 0.000953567 | 7.4855
2 x STAB | +159.860 | +159.900 | 2173.1 | 2173.06 | 0.323786 | 0.000964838 | 7.57398

# IfcBeam: TUBE-R-180*100*4 (60)
In: Undefined
Description: TUBE-R-180*100*4; Material: STEEL/S275JR
Pset_BeamCommon - LoadBearing: no
Tekla Commun - Repère d'assemblage: A0(?); Classe: 3; Matériau: S275JR; Profil: TUBE-R-180*100*4
Tekla Quantités - Volume: 0 m3; Surface par tonne: 32.6 m2; Hauteur: 180 mm; Largeur: 100 mm
Name | Reference = Repère de pièce | Niveau bas | Niveau haut | Phase | Nom | Poids (kg) | Surface supérieure totale (m2) | Surface nette (m2) | Longueur (mm) | Length (mm) | OuterSurfaceArea (m2) | NetVolume (m3) | NetWeight (kg)
4 x SOLIVE | A0(?) | +162.500 | +162.680 | 301 | SOLIVE | 69.6 | 0.3 | 2.3 | 4180 | 4180 | 2.26974 | 0.00909568 | 71.4011
4 x CONSOLE | A0(?) | +162.500 | +162.680 | 303 | CONSOLE | 25.3 | 0.2 | 0.7 | 1518 | 1518 | 0.824274 | 0.00330317 | 25.9299
2 x SOLIVE | A0(?) | +162.500 | +162.680 | 301 | SOLIVE | 48.1 | 0.3 | 1.6 | 2890 | 2890 | 1.56927 | 0.00628864 | 49.3658
2 x SOLIVE | A0(?) | +162.500 | +162.680 | 301 | SOLIVE | 69.8 | 0.3 | 2.3 | 4190 | 4190 | 2.27517 | 0.00911744 | 71.5719
2 x SOLIVE | A0(?) | +162.500 | +162.680 | 301 | SOLIVE | 81.6 | 0.5 | 2.7 | 4898 | 4898 | 2.65961 | 0.010658 | 83.6657
CONSOLE | A0(?) | +162.500 | +162.680 | 303 | CONSOLE | 27.3 | 0.2 | 0.9 | 1638 | 1638 | 0.889434 | 0.00356429 | 27.9797
2 x SOLIVE | A0(?) | +162.500 | +162.680 | 301 | SOLIVE | 55.5 | 0.3 | 2 | 3333.6 | 3333.57 | 1.81013 | 0.00725385 | 56.9427
10 x SOLIVE | A0(?) | +162.500 | +162.680 | 301 | SOLIVE | 64.9 | 0.3 | 2.2 | 3900 | 3900 | 2.1177 | 0.0084864 | 66.6182
2 x SOLIVE | A0(?) | +156.490 | +156.670 | 301 | SOLIVE | 55.5 | 0.3 | 2 | 3333.6 | 3333.57 | 1.81013 | 0.00725385 | 56.9427
10 x SOLIVE | A0(?) | +156.490 | +156.670 | 301 | SOLIVE | 64.9 | 0.3 | 2.2 | 3900 | 3900 | 2.1177 | 0.0084864 | 66.6182
7 x CONSOLE | 0(?) | +162.500 | +162.680 | 301 | CONSOLE | 25.3 | 0.2 | 0.7 | 1518 | 1518 | 0.824274 | 0.00330317 | 25.9299
7 x CONSOLE | 0(?) | +156.490 | +156.670 | 301 | CONSOLE | 25.3 | 0.2 | 0.7 | 1518 | 1518 | 0.824274 | 0.00330317 | 25.9299
7 x CONSOLE | 0(?) | +159.790 | +159.970 | 301 | CONSOLE | 25.3 | 0.2 | 0.7 | 1518 | 1518 | 0.824274 | 0.00330317 | 25.9299

# IfcBeam: UPN140 (5)
In: Undefined
Description: UPN140
Pset_BeamCommon - LoadBearing: no; Reference: A0(?)
Tekla Commun - Repère de pièce: A0(?); Repère d'assemblage: A0(?); Phase: 301; Classe: 3; Profil: UPN140
Tekla Quantités - Volume: 0 m3; Surface par tonne: 30.4 m2; Hauteur: 140 mm; Largeur: 60 mm
Name | Material | Niveau bas | Niveau haut | Matériau | Nom | Poids (kg) | Surface supérieure totale (m2) | Surface nette (m2) | Longueur (mm) = Length (mm) | OuterSurfaceArea (m2) | NetVolume (m3) | NetWeight (kg)
POUTRE | STEEL/S235JR | +150.730 | +150.870 | S235JR | POUTRE | 28.8 | 0.1 | 0.9 | 1800 | 0.876602 | 0.00361858 | 28.4059
2 x SOLIVE | STEEL/S275JR | +159.830 | +159.970 | S275JR | SOLIVE | 42.1 | 0.2 | 1.3 | 2626 | 1.27886 | 0.0052791 | 41.4409
SOLIVE | STEEL/S275JR | +159.830 | +159.970 | S275JR | SOLIVE | 39.2 | 0.1 | 1.3 | 2447 | 1.19169 | 0.00491925 | 38.6161
SOLIVE | STEEL/S275JR | +159.830 | +159.970 | S275JR | SOLIVE | 34.6 | 0.1 | 1.1 | 2163 | 1.05338 | 0.00434832 | 34.1343

# IfcBeam: UPN160 (3)
In: Undefined
Description: UPN160; Material: STEEL/S275JR
Pset_BeamCommon - LoadBearing: no; Reference: A0(?)
Tekla Commun - Repère de pièce: A0(?); Repère d'assemblage: A0(?); Phase: 301; Classe: 3; Matériau: S275JR; Profil: UPN160; Nom: POUTRE
Tekla Quantités - Poids: 33.9 kg; Volume: 0 m3; Surface supérieure totale: 0.1 m2; Surface par tonne: 28.9 m2; Surface nette: 0.9 m2; Hauteur: 160 mm; Largeur: 65 mm; Longueur: 1800 mm
BaseQuantities - Length: 1800 mm; OuterSurfaceArea: 0.981 m2; NetVolume: 0.0042714 m3; NetWeight: 33.5305 kg
Name | Niveau bas | Niveau haut
2 x POUTRE | +148.315 | +148.475
POUTRE | +149.910 | +150.070

# IfcBeam: UPN180 (12)
In: Undefined
Description: UPN180; Material: STEEL/S275JR
Pset_BeamCommon - LoadBearing: no
Tekla Commun - Niveau bas: +159.790; Niveau haut: +159.970; Repère d'assemblage: A0(?); Phase: 301; Classe: 3; Matériau: S275JR; Profil: UPN180; Nom: SOLIVE
Tekla Quantités - Volume: 0 m3; Surface par tonne: 27.5 m2; Hauteur: 180 mm; Largeur: 70 mm
Name | Reference = Repère de pièce | Poids (kg) | Surface supérieure totale (m2) | Surface nette (m2) | Longueur (mm) | Length (mm) | OuterSurfaceArea (m2) | NetVolume (m3) | NetWeight (kg)
2 x SOLIVE | A0(?) | 73 | 0.2 | 2.1 | 3333.6 | 3333.57 | 2.00681 | 0.00921505 | 72.3382
8 x SOLIVE | A0(?) | 85.4 | 0.3 | 2.5 | 3900 | 3900 | 2.3478 | 0.0107808 | 84.6297
SOLIVE | 0(?) | 84.1 | 0.3 | 2.5 | 3840 | 3840 | 2.31168 | 0.010615 | 83.3277
SOLIVE | A0(?) | 84.1 | 0.3 | 2.5 | 3840 | 3840 | 2.31168 | 0.010615 | 83.3277

# IfcBeam: UPN220 (91)
In: Undefined
Description: UPN220
Tekla Commun - Profil: UPN220
Tekla Quantités - Volume: 0 m3; Surface par tonne: 24.5 m2; Hauteur: 220 mm; Largeur: 80 mm
Pset_BeamCommon - LoadBearing: no
Name | Material | Niveau bas | Niveau haut | Repère de pièce = Reference | Repère d'assemblage | Phase | Classe | Matériau | Nom | Poids (kg) | Surface supérieure totale (m2) | Surface nette (m2) | Longueur (mm) | Length (mm) | OuterSurfaceArea (m2) | NetVolume (m3) | NetWeight (kg)
SOLIVE | STEEL/S275JR | +149.850 | +150.070 | A0(?) | A0(?) | 301 | 3 | S275JR | SOLIVE | 17 | 0 | 0.4 | 578 | 578 | 0.415004 | 0.00214084 | 16.8056
SOLIVE | STEEL/S275JR | +149.850 | +150.070 | A0(?) | A0(?) | 301 | 3 | S275JR | SOLIVE | 78.8 | 0.2 | 2 | 2685 | 2685 | 1.92783 | 0.00994492 | 78.0676
2 x LIMON | STEEL/S235JR | +153.150 | +153.370 | 0(?) | L0(?) | 301 | 1 | S235JR | LIMON | 81.9 | 0.2 | 2 | 2791 | 2791.03 | 2.00396 | 0.0102326 | 80.3256
LIMON | STEEL/S235JR | +156.450 | +156.670 | 0(?) | L0(?) | 301 | 1 | S235JR | LIMON | 79.2 | 0.2 | 2 | 2697 | 2697.03 | 1.93647 | 0.00972046 | 76.3056
LIMON | STEEL/S235JR | +149.850 | +150.070 | 0(?) | L0(?) | 301 | 1 | S235JR | LIMON | 81.9 | 0.2 | 2 | 2791 | 2791.03 | 2.00396 | 0.0102326 | 80.3256
LIMON | STEEL/S235JR | +156.450 | +156.670 | 0(?) | L0(?) | 301 | 1 | S235JR | LIMON | 81.9 | 0.2 | 2 | 2791 | 2791.03 | 2.00396 | 0.0102326 | 80.3256
2 x POUTRE | STEEL/S275JR | +156.450 | +156.670 | A0(?) | A0(?) | 303 | 3 | S275JR | POUTRE | 76.7 | 0.2 | 2 | 2613 | 2613 | 1.87613 | 0.00967824 | 75.9742
SOLIVE | STEEL/S275JR | +156.450 | +156.670 | 0(?) | A0(?) | 303 | 3 | S275JR | SOLIVE | 74.2 | 0.2 | 2 | 2528 | 2527.99 | 1.8151 | 0.00936337 | 73.5025
LIMON | STEEL/S235JR | +153.150 | +153.370 | L0(?) | L0(?) | 301 | 1 | S235JR | LIMON | 44.6 | 0.1 | 1.1 | 1517.8 | 1517.82 | 1.08979 | 0.00562182 | 44.1313
2 x LIMON | STEEL/S235JR | +149.175 | +149.395 | 0(?) | L0(?) | 301 | 1 | S235JR | LIMON | 3 | 0 | 0.1 | 103.4 | 103.444 | 0.0742727 | 0.00027718 | 2.17587
2 x LIMON | STEEL/S275JR | +150.650 | +150.870 | 0(?) | L0(?) | 301 | 1 | S275JR | LIMON | 5.3 | 0 | 0.1 | 179.7 | 179.697 | 0.129022 | 0.000448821 | 3.52325
2 x LIMON | STEEL/S235JR | +156.450 | +156.670 | 0(?) | L0(?) | 301 | 1 | S235JR | LIMON | 85 | 0.2 | 2.1 | 2894.3 | 2894.29 | 2.0781 | 0.010615 | 83.3277
LIMON | STEEL/S235JR | +156.450 | +156.670 | 0(?) | L0(?) | 301 | 1 | S235JR | LIMON | 5.3 | 0 | 0.1 | 181.2 | 181.186 | 0.130091 | 0.000506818 | 3.97852
POUTRE | STEEL/S275JR | +148.255 | +148.475 | A0(?) | A0(?) | 301 | 3 | S275JR | POUTRE | 116.6 | 0.3 | 2.9 | 3970 | 3970 | 2.85046 | 0.0147044 | 115.43
2 x LIMON | STEEL/S235JR | +148.255 | +148.475 | 0(?) | L0(?) | 301 | 1 | S235JR | LIMON | 53 | 0.1 | 1.3 | 1803.8 | 1803.77 | 1.29511 | 0.00657469 | 51.6113
2 x LIMON | STEEL/S235JR | +148.255 | +148.475 | 0(?) | L0(?) | 301 | 1 | S235JR | LIMON | 55.9 | 0.2 | 1.4 | 1903.6 | 1903.61 | 1.36679 | 0.00694447 | 54.5141
LIMON | STEEL/S235JR | +153.150 | +153.370 | 0(?) | L0(?) | 301 | 1 | S235JR | LIMON | 5.3 | 0 | 0.1 | 181.2 | 181.186 | 0.130091 | 0.000506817 | 3.97852
LIMON | STEEL/S235JR | +153.150 | +153.370 | 0(?) | L0(?) | 301 | 1 | S235JR | LIMON | 85 | 0.2 | 2.1 | 2894.3 | 2894.29 | 2.0781 | 0.010615 | 83.3277
2 x LIMON | STEEL/S235JR | +149.850 | +150.070 | 0(?) | L0(?) | 301 | 1 | S235JR | LIMON | 62.6 | 0.2 | 1.4 | 2133.6 | 2133.61 | 1.53193 | 0.00779636 | 61.2014
LIMON | STEEL/S235JR | +156.450 | +156.670 | 0(?) | L0(?) | 301 | 1 | S235JR | LIMON | 5.3 | 0 | 0.1 | 181.2 | 181.186 | 0.130091 | 0.000506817 | 3.97852
LIMON | STEEL/S235JR | +159.750 | +159.970 | 0(?) | L0(?) | 301 | 1 | S235JR | LIMON | 5.3 | 0 | 0.1 | 181.2 | 181.186 | 0.130091 | 0.000506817 | 3.97852
2 x LIMON | STEEL/S235JR | +159.750 | +159.970 | 0(?) | L0(?) | 301 | 1 | S235JR | LIMON | 85 | 0.2 | 2.1 | 2894.3 | 2894.29 | 2.0781 | 0.010615 | 83.3277
POUTRE | STEEL/S275JR | +159.750 | +159.970 | A0(?) | A0(?) | 301 | 3 | S275JR | POUTRE | 79.3 | 0.2 | 2 | 2700 | 2700 | 1.9386 | 0.0100005 | 78.5037
POUTRE | STEEL/S275JR | +159.750 | +159.970 | A0(?) | A0(?) | 303 | 3 | S275JR | POUTRE | 78.8 | 0.2 | 2 | 2688 | 2688 | 1.92998 | 0.00995603 | 78.1548
POUTRE | STEEL/S275JR | +156.450 | +156.670 | A0(?) | A0(?) | 301 | 3 | S275JR | POUTRE | 61.2 | 0.2 | 1.4 | 2085 | 2085 | 1.49703 | 0.00772259 | 60.6223
POUTRE | STEEL/S275JR | +156.450 | +156.670 | A0(?) | A0(?) | 301 | 3 | S275JR | POUTRE | 182 | 0.5 | 4.5 | 6200 | 6200 | 4.4516 | 0.0229641 | 180.268
POUTRE | STEEL/S275JR | +156.450 | +156.670 | A0(?) | A0(?) | 301 | 3 | S275JR | POUTRE | 63.7 | 0.2 | 1.6 | 2170 | 2170 | 1.55806 | 0.00803742 | 63.0937
POUTRE | STEEL/S275JR | +156.450 | +156.670 | 0(?) | A0(?) | 301 | 3 | S275JR | POUTRE | 76.5 | 0.2 | 2 | 2606 | 2606 | 1.87111 | 0.00948157 | 74.4303
POUTRE | STEEL/S275JR | +156.450 | +156.670 | 0(?) | A0(?) | 301 | 3 | S275JR | POUTRE | 91 | 0.2 | 2.3 | 3100 | 3100 | 2.2258 | 0.011482 | 90.1339
POUTRE | STEEL/S275JR | +156.450 | +156.670 | A0(?) | A0(?) | 301 | 3 | S275JR | POUTRE | 91 | 0.2 | 2.3 | 3100 | 3100 | 2.2258 | 0.011482 | 90.1339
POUTRE | STEEL/S275JR | +156.450 | +156.670 | A0(?) | A0(?) | 301 | 3 | S275JR | POUTRE | 79.3 | 0.2 | 2 | 2700 | 2700 | 1.9386 | 0.0100005 | 78.5037
POUTRE | STEEL/S275JR | +153.150 | +153.370 | A0(?) | A0(?) | 301 | 3 | S275JR | POUTRE | 182 | 0.5 | 4.5 | 6200 | 6200 | 4.4516 | 0.0229641 | 180.268
POUTRE | STEEL/S275JR | +153.150 | +153.370 | A0(?) | A0(?) | 301 | 3 | S275JR | POUTRE | 63.7 | 0.2 | 1.6 | 2170 | 2170 | 1.55806 | 0.00803742 | 63.0937
POUTRE | STEEL/S275JR | +153.150 | +153.370 | A0(?) | A0(?) | 303 | 3 | S275JR | POUTRE | 76.7 | 0.2 | 2 | 2613 | 2613 | 1.87613 | 0.00967824 | 75.9742
2 x POUTRE | STEEL/S275JR | +153.150 | +153.370 | A0(?) | A0(?) | 301 | 3 | S275JR | POUTRE | 79.3 | 0.2 | 2 | 2700 | 2700 | 1.9386 | 0.0100005 | 78.5037
2 x POUTRE | STEEL/S275JR | +153.150 | +153.370 | A0(?) | A0(?) | 301 | 3 | S275JR | POUTRE | 91 | 0.2 | 2.3 | 3100 | 3100 | 2.2258 | 0.011482 | 90.1339
SOLIVE | STEEL/S275JR | +149.850 | +150.070 | A0(?) | A0(?) | 301 | 3 | S275JR | SOLIVE | 63.7 | 0.2 | 1.6 | 2170 | 2170 | 1.55806 | 0.00803742 | 63.0937
SOLIVE | STEEL/S275JR | +149.850 | +150.070 | A0(?) | A0(?) | 301 | 3 | S275JR | SOLIVE | 75.2 | 0.2 | 2 | 2563 | 2563 | 1.84023 | 0.00949304 | 74.5204
LIMON | STEEL/S235JR | +153.150 | +153.370 | 0(?) | L0(?) | 301 | 1 | S235JR | LIMON | 38.3 | 0.1 | 0.9 | 1303.8 | 1303.77 | 0.936109 | 0.00472306 | 37.076
LIMON | STEEL/S235JR | +153.150 | +153.370 | 0(?) | L0(?) | 301 | 1 | S235JR | LIMON | 47.1 | 0.1 | 1.3 | 1603.8 | 1603.77 | 1.15151 | 0.00583422 | 45.7986
2 x LIMON | STEEL/S235JR | +149.175 | +149.395 | 0(?) | L0(?) | 301 | 1 | S235JR | LIMON | 75 | 0.2 | 2 | 2553.8 | 2553.77 | 1.83361 | 0.00935291 | 73.4203
POUTRE | STEEL/S275JR | +153.150 | +153.370 | A0(?) | A0(?) | 303 | 3 | S275JR | POUTRE | 84.8 | 0.2 | 2.1 | 2890 | 2890 | 2.07502 | 0.0107042 | 84.028
LIMON | STEEL/S235JR | +159.750 | +159.970 | 0(?) | L0(?) | 301 | 1 | S235JR | LIMON | 5.3 | 0 | 0.1 | 181.2 | 181.186 | 0.130091 | 0.000506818 | 3.97852
SOLIVE | STEEL/S275JR | +150.650 | +150.870 | A0(?) | A0(?) | 301 | 3 | S275JR | SOLIVE | 77.1 | 0.2 | 2 | 2625 | 2625 | 1.88475 | 0.00972269 | 76.3231
LIMON | STEEL/S235JR | +153.150 | +153.370 | 0(?) | L0(?) | 301 | 1 | S235JR | LIMON | 85 | 0.2 | 2.1 | 2896.4 | 2896.36 | 2.07958 | 0.0106261 | 83.4147
LIMON | STEEL/S235JR | +153.150 | +153.370 | 0(?) | L0(?) | 301 | 1 | S235JR | LIMON | 5.3 | 0 | 0.1 | 183.3 | 183.258 | 0.131579 | 0.000517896 | 4.06549
2 x LIMON | STEEL/S235JR | +150.650 | +150.870 | 0(?) | L0(?) | 301 | 1 | S235JR | LIMON | 39.8 | 0.1 | 0.9 | 1354.1 | 1354.06 | 0.972218 | 0.0049136 | 38.5718
2 x SOLIVE | STEEL/S275JR | +153.150 | +153.370 | A0(?) | A0(?) | 301 | 3 | S275JR | SOLIVE | 77.1 | 0.2 | 2 | 2626 | 2626 | 1.88547 | 0.00972639 | 76.3522
SOLIVE | STEEL/S275JR | +153.150 | +153.370 | A0(?) | A0(?) | 301 | 3 | S275JR | SOLIVE | 71.7 | 0.2 | 1.7 | 2447 | 2447 | 1.75695 | 0.00906339 | 71.1476
SOLIVE | STEEL/S275JR | +153.150 | +153.370 | A0(?) | A0(?) | 301 | 3 | S275JR | SOLIVE | 63.5 | 0.2 | 1.6 | 2163 | 2163 | 1.55303 | 0.00801149 | 62.8902
2 x SOLIVE | STEEL/S275JR | +159.750 | +159.970 | A0(?) | A0(?) | 301 | 3 | S275JR | SOLIVE | 77.1 | 0.2 | 2 | 2626 | 2626 | 1.88547 | 0.00972639 | 76.3522
SOLIVE | STEEL/S275JR | +159.750 | +159.970 | A0(?) | A0(?) | 301 | 3 | S275JR | SOLIVE | 71.7 | 0.2 | 1.7 | 2447 | 2447 | 1.75695 | 0.00906339 | 71.1476
SOLIVE | STEEL/S275JR | +159.750 | +159.970 | A0(?) | A0(?) | 301 | 3 | S275JR | SOLIVE | 63.5 | 0.2 | 1.6 | 2163 | 2163 | 1.55303 | 0.00801149 | 62.8902
SOLIVE | STEEL/S275JR | +159.750 | +159.970 | A0(?) | A0(?) | 303 | 3 | S275JR | SOLIVE | 76.7 | 0.2 | 2 | 2613 | 2613 | 1.87613 | 0.00967824 | 75.9742
SOLIVE | STEEL/S275JR | +159.750 | +159.970 | A0(?) | A0(?) | 301 | 3 | S275JR | SOLIVE | 79.3 | 0.2 | 2 | 2700 | 2700 | 1.9386 | 0.0100005 | 78.5037
2 x SOLIVE | STEEL/S275JR | +150.650 | +150.870 | A0(?) | A0(?) | 301 | 3 | S275JR | SOLIVE | 79.3 | 0.2 | 2 | 2700 | 2700 | 1.9386 | 0.0100005 | 78.5037
SOLIVE | STEEL/S275JR | +150.650 | +150.870 | A0(?) | A0(?) | 301 | 3 | S275JR | SOLIVE | 73 | 0.2 | 1.7 | 2486.4 | 2486.43 | 1.78526 | 0.00920944 | 72.2941
SOLIVE | STEEL/S275JR | +150.650 | +150.870 | A0(?) | A0(?) | 301 | 3 | S275JR | SOLIVE | 63.7 | 0.2 | 1.6 | 2170 | 2170 | 1.55806 | 0.00803742 | 63.0937
SOLIVE | STEEL/S275JR | +156.450 | +156.670 | A0(?) | A0(?) | 301 | 3 | S275JR | SOLIVE | 179.5 | 0.5 | 4.5 | 6115 | 6115 | 4.39057 | 0.0226492 | 177.796
SOLIVE | STEEL/S275JR | +156.450 | +156.670 | A0(?) | A0(?) | 301 | 3 | S275JR | SOLIVE | 79.3 | 0.2 | 2 | 2700 | 2700 | 1.9386 | 0.0100005 | 78.5037
SOLIVE | STEEL/S275JR | +156.450 | +156.670 | A0(?) | A0(?) | 301 | 3 | S275JR | SOLIVE | 91 | 0.2 | 2.3 | 3100 | 3100 | 2.2258 | 0.011482 | 90.1339
SOLIVE | STEEL/S275JR | +156.450 | +156.670 | 0(?) | A0(?) | 301 | 3 | S275JR | SOLIVE | 88.5 | 0.2 | 2.2 | 3015 | 3015 | 2.16477 | 0.0111672 | 87.6625
SOLIVE | STEEL/S275JR | +156.450 | +156.670 | 0(?) | A0(?) | 301 | 3 | S275JR | SOLIVE | 74 | 0.2 | 1.7 | 2521 | 2521 | 1.81008 | 0.00918226 | 72.0807
SOLIVE | STEEL/S275JR | +156.450 | +156.670 | A0(?) | A0(?) | 303 | 3 | S275JR | SOLIVE | 75.7 | 0.2 | 2 | 2579.4 | 2579.43 | 1.85203 | 0.0095539 | 74.9981
SOLIVE | STEEL/S275JR | +156.450 | +156.670 | A0(?) | A0(?) | 301 | 3 | S275JR | SOLIVE | 63.7 | 0.2 | 1.6 | 2170 | 2170 | 1.55806 | 0.00803742 | 63.0937
SOLIVE | STEEL/S275JR | +156.450 | +156.670 | 0(?) | A0(?) | 301 | 3 | S275JR | SOLIVE | 58.7 | 0.2 | 1.4 | 2000 | 2000 | 1.436 | 0.00740776 | 58.1509
SOLIVE | STEEL/S275JR | +153.150 | +153.370 | A0(?) | A0(?) | 301 | 3 | S275JR | SOLIVE | 182 | 0.5 | 4.5 | 6200 | 6200 | 4.4516 | 0.0229641 | 180.268
2 x SOLIVE | STEEL/S275JR | +153.150 | +153.370 | A0(?) | A0(?) | 301 | 3 | S275JR | SOLIVE | 79.3 | 0.2 | 2 | 2700 | 2700 | 1.9386 | 0.0100005 | 78.5037
2 x SOLIVE | STEEL/S275JR | +153.150 | +153.370 | A0(?) | A0(?) | 301 | 3 | S275JR | SOLIVE | 91 | 0.2 | 2.3 | 3100 | 3100 | 2.2258 | 0.011482 | 90.1339
SOLIVE | STEEL/S275JR | +153.150 | +153.370 | A0(?) | A0(?) | 303 | 3 | S275JR | SOLIVE | 75.7 | 0.2 | 2 | 2579.4 | 2579.43 | 1.85203 | 0.0095539 | 74.9981
2 x SOLIVE | STEEL/S275JR | +153.150 | +153.370 | A0(?) | A0(?) | 301 | 3 | S275JR | SOLIVE | 63.7 | 0.2 | 1.6 | 2170 | 2170 | 1.55806 | 0.00803742 | 63.0937
SOLIVE | STEEL/S275JR | +153.150 | +153.370 | A0(?) | A0(?) | 303 | 3 | S275JR | SOLIVE | 76.7 | 0.2 | 2 | 2613 | 2612.99 | 1.87613 | 0.0096782 | 75.9739

# IfcBeam: UPN300 (2)
In: Undefined
Description: UPN300; Material: STEEL/S275JR
Pset_BeamCommon - LoadBearing: no; Reference: A0(?)
Tekla Commun - Niveau bas: +153.070; Niveau haut: +153.370; Repère de pièce: A0(?); Repère d'assemblage: A0(?); Classe: 3; Matériau: S275JR; Profil: UPN300; Nom: POUTRE
Tekla Quantités - Volume: 0 m3; Surface par tonne: 20.5 m2; Hauteur: 300 mm; Largeur: 100 mm
Name | Phase | Poids (kg) | Surface supérieure totale (m2) | Surface nette (m2) | Longueur (mm) = Length (mm) | OuterSurfaceArea (m2) | NetVolume (m3) | NetWeight (kg)
POUTRE | 303 | 120.6 | 0.3 | 2.5 | 2613 | 2.47712 | 0.0151763 | 119.134
POUTRE | 301 | 100.2 | 0.2 | 2.1 | 2170 | 2.05716 | 0.0126034 | 98.9364

# IfcColumn: 160*160, POUTRE
In: Undefined
Description: 160*160; Material: TIMBER/CHENE
Pset_ColumnCommon - LoadBearing: no; Reference: Po0(?)
Tekla Commun - Niveau bas: +163.200; Niveau haut: +164.960; Repère de pièce: Po0(?); Repère d'assemblage: Po0(?); Phase: 1402; Classe: 6; Matériau: CHENE; Profil: 160*160; Nom: POUTRE
Tekla Quantités - Poids: 40.6 kg; Volume: 0 m3; Surface supérieure totale: 0 m2; Surface par tonne: 28.9 m2; Surface nette: 1.3 m2; Hauteur: 160 mm; Largeur: 160 mm; Longueur: 1760 mm
BaseQuantities - Length: 1760.01 mm; OuterSurfaceArea: 1.17761 m2; NetVolume: 0.0450564 m3; NetWeight: 40.5507 kg

# IfcColumn: 240*240, POUTRE
In: Undefined
Description: 240*240; Material: TIMBER/CHENE
Pset_ColumnCommon - LoadBearing: no; Reference: Po0(?)
Tekla Commun - Niveau bas: +159.900; Niveau haut: +163.186; Repère de pièce: Po0(?); Repère d'assemblage: Po0(?); Phase: 1402; Classe: 6; Matériau: CHENE; Profil: 240*240; Nom: POUTRE
Tekla Quantités - Poids: 170.4 kg; Volume: 0.2 m3; Surface supérieure totale: 0.1 m2; Surface par tonne: 19.2 m2; Surface nette: 3.3 m2; Hauteur: 240 mm; Largeur: 240 mm; Longueur: 3286.1 mm
BaseQuantities - Length: 3286.14 mm; OuterSurfaceArea: 3.26989 m2; NetVolume: 0.189281 m3; NetWeight: 170.353 kg

# IfcColumn: 240*280 (21)
In: Undefined
Description: 240*280; Material: TIMBER/CHENE
Tekla Commun - Repère de pièce: Po0(?); Repère d'assemblage: Po0(?); Phase: 1402; Classe: 6; Matériau: CHENE; Profil: 240*280; Nom: POUTRE
Tekla Quantités - Volume: 0.2 m3; Surface supérieure totale: 0.1 m2; Hauteur: 240 mm; Largeur: 280 mm
Pset_ColumnCommon - LoadBearing: no; Reference: Po0(?)
Name | Niveau bas | Niveau haut | Poids (kg) | Surface par tonne (m2) | Surface nette (m2) | Longueur (mm) | Length (mm) | OuterSurfaceArea (m2) | NetVolume (m3) | NetWeight (kg)
7 x POUTRE | +159.850 | +163.470 | 218.9 | 17.8 | 3.9 | 3620 | 3620.01 | 3.89921 | 0.243265 | 218.938
7 x POUTRE | +156.550 | +159.850 | 199.6 | 17.9 | 3.6 | 3300 | 3300 | 3.5664 | 0.22176 | 199.584
7 x POUTRE | +153.400 | +156.550 | 190.5 | 17.9 | 3.4 | 3150 | 3149.99 | 3.41039 | 0.21168 | 190.512

# IfcColumn: 240*320 (6)
In: Undefined
Description: 240*320; Material: TIMBER/CHENE
Pset_ColumnCommon - LoadBearing: no; Reference: Po0(?)
Tekla Commun - Repère de pièce: Po0(?); Repère d'assemblage: Po0(?); Phase: 1402; Classe: 6; Matériau: CHENE; Profil: 240*320; Nom: POUTRE
Tekla Quantités - Surface supérieure totale: 0.1 m2; Surface par tonne: 16.9 m2; Hauteur: 240 mm; Largeur: 320 mm
Name | Niveau bas | Niveau haut | Poids (kg) | Volume (m3) | Surface nette (m2) | Longueur (mm) | Length (mm) | OuterSurfaceArea (m2) | NetVolume (m3) | NetWeight (kg)
POUTRE | +159.850 | +163.130 | 226.7 | 0.3 | 3.8 | 3280 | 3279.99 | 3.82719 | 0.251904 | 226.713
POUTRE | +159.850 | +163.210 | 232.2 | 0.3 | 3.9 | 3360 | 3360 | 3.9168 | 0.258048 | 232.243
2 x POUTRE | +156.550 | +159.850 | 228.1 | 0.3 | 3.8 | 3300 | 3300 | 3.8496 | 0.25344 | 228.096
2 x POUTRE | +153.400 | +156.550 | 217.7 | 0.2 | 3.7 | 3150 | 3149.99 | 3.68159 | 0.24192 | 217.728

# IfcColumn: 280*240 (7)
In: Undefined
Description: 280*240; Material: TIMBER/CHENE
Pset_ColumnCommon - LoadBearing: no; Reference: Po0(?)
Tekla Commun - Repère de pièce: Po0(?); Repère d'assemblage: Po0(?); Phase: 1402; Classe: 6; Matériau: CHENE; Profil: 280*240; Nom: POUTRE
Tekla Quantités - Volume: 0.2 m3; Surface supérieure totale: 0.1 m2; Hauteur: 280 mm; Largeur: 240 mm
Name | Niveau bas | Niveau haut | Poids (kg) | Surface par tonne (m2) | Surface nette (m2) | Longueur (mm) = Length (mm) | OuterSurfaceArea (m2) | NetVolume (m3) | NetWeight (kg)
2 x POUTRE | +153.400 | +156.550 | 190.5 | 17.9 | 3.4 | 3150 | 3.4104 | 0.21168 | 190.512
2 x POUTRE | +156.550 | +159.900 | 202.6 | 17.9 | 3.6 | 3350 | 3.6184 | 0.22512 | 202.608
3 x POUTRE | +159.900 | +163.470 | 215.9 | 17.8 | 3.8 | 3570 | 3.8472 | 0.239904 | 215.914

# IfcColumn: 280*280 (6)
In: Undefined
Description: 280*280; Material: TIMBER/CHENE
Pset_ColumnCommon - LoadBearing: no; Reference: Po0(?)
Tekla Commun - Repère de pièce: Po0(?); Repère d'assemblage: Po0(?); Phase: 1402; Classe: 6; Matériau: CHENE; Profil: 280*280; Nom: POUTRE
Tekla Quantités - Surface supérieure totale: 0.1 m2; Hauteur: 280 mm; Largeur: 280 mm
Name | Niveau bas | Niveau haut | Poids (kg) | Volume (m3) | Surface par tonne (m2) | Surface nette (m2) | Longueur (mm) | Length (mm) | OuterSurfaceArea (m2) | NetVolume (m3) | NetWeight (kg)
POUTRE | +163.200 | +164.960 | 124.2 | 0.1 | 17.1 | 2.1 | 1760 | 1760.01 | 2.12802 | 0.137985 | 124.187
POUTRE | +159.850 | +163.200 | 236.4 | 0.3 | 16.5 | 3.9 | 3350 | 3349.99 | 3.90879 | 0.26264 | 236.376
POUTRE | +163.470 | +164.960 | 105.1 | 0.1 | 17.4 | 1.7 | 1490 | 1490 | 1.8256 | 0.116816 | 105.135
POUTRE | +159.850 | +163.470 | 255.4 | 0.3 | 16.5 | 4.2 | 3620 | 3620 | 4.2112 | 0.283808 | 255.427
POUTRE | +156.550 | +159.850 | 232.8 | 0.3 | 16.5 | 3.9 | 3300 | 3300 | 3.8528 | 0.25872 | 232.848
POUTRE | +153.400 | +156.550 | 222.3 | 0.2 | 16.6 | 3.7 | 3150 | 3149.99 | 3.68479 | 0.24696 | 222.264

# IfcColumn: 320*240 (7)
In: Undefined
Description: 320*240; Material: TIMBER/CHENE
Pset_ColumnCommon - LoadBearing: no; Reference: Po0(?)
Tekla Commun - Repère de pièce: Po0(?); Repère d'assemblage: Po0(?); Phase: 1402; Classe: 6; Matériau: CHENE; Profil: 320*240; Nom: POUTRE
Tekla Quantités - Surface supérieure totale: 0.1 m2; Surface par tonne: 16.9 m2; Hauteur: 320 mm; Largeur: 240 mm
Name | Niveau bas | Niveau haut | Poids (kg) | Volume (m3) | Surface nette (m2) | Longueur (mm) | Length (mm) | OuterSurfaceArea (m2) | NetVolume (m3) | NetWeight (kg)
POUTRE | +153.350 | +156.550 | 221.2 | 0.2 | 3.7 | 3200 | 3199.99 | 3.73759 | 0.245759 | 221.183
POUTRE | +153.400 | +156.550 | 217.7 | 0.2 | 3.7 | 3150 | 3149.99 | 3.68159 | 0.241919 | 217.727
2 x POUTRE | +156.550 | +159.850 | 228.1 | 0.3 | 3.8 | 3300 | 3300.01 | 3.84961 | 0.253441 | 228.097
POUTRE | +159.850 | +163.210 | 232.2 | 0.3 | 3.9 | 3360 | 3360 | 3.9168 | 0.258048 | 232.243
POUTRE | +159.850 | +163.130 | 226.7 | 0.3 | 3.8 | 3280 | 3280 | 3.8272 | 0.251904 | 226.714
POUTRE | +159.900 | +163.130 | 223.3 | 0.2 | 3.8 | 3230 | 3230 | 3.7712 | 0.248064 | 223.257

# IfcColumn: 450*400 (3)
In: Undefined
Description: 450*400; Material: CONCRETE/C25/30
Tekla Commun - Niveau bas: +147.592; Niveau haut: +153.200; Repère de pièce: Pt0(?); Repère d'assemblage: Pt0(?); Phase: 1401; Classe: 13; Matériau: C25/30; Profil: 450*400; Nom: POTEAU
Tekla Quantités - Poids: 2422.5 kg; Volume: 1 m3; Surface supérieure totale: 0.2 m2; Surface par tonne: 4.1 m2; Surface nette: 9.8 m2; Hauteur: 450 mm; Largeur: 400 mm; Longueur: 5607.6 mm
Pset_ColumnCommon - LoadBearing: no; Reference: Pt0(?)
BaseQuantities - Length: 5607.64 mm; OuterSurfaceArea: 9.89299 m2; NetVolume: 1.00938 m3; NetWeight: 2422.5 kg

# IfcColumn: L100*10 (5)
In: Undefined
Description: L100*10; Material: STEEL/S235JR
Tekla Commun - Phase: 301; Classe: 3; Matériau: S235JR; Profil: L100*10; Nom: CORNIERE
Tekla Quantités - Poids: 2.4 kg; Volume: 0 m3; Surface supérieure totale: 0 m2; Surface par tonne: 25.9 m2; Surface nette: 0.1 m2; Hauteur: 100 mm; Largeur: 100 mm; Longueur: 160 mm
Pset_ColumnCommon - LoadBearing: no
BaseQuantities - Length: 160 mm; OuterSurfaceArea: 0.0624 m2; NetVolume: 0.000304 m3; NetWeight: 2.3864 kg
Name | Niveau bas | Niveau haut | Repère de pièce = Reference | Repère d'assemblage
2 x CORNIERE | +156.480 | +156.640 | A0(?) | A0(?)
2 x CORNIERE | +156.480 | +156.640 | 0(?) | P0(?)
CORNIERE | +159.800 | +159.960 | 0(?) | A0(?)

# IfcColumn: L80*8 (6)
In: Undefined
Description: L80*8; Material: STEEL/S235JR
Tekla Quantités - Poids: 1.4 kg; Volume: 0 m3; Surface supérieure totale: 0 m2; Surface par tonne: 32.2 m2; Surface nette: 0.1 m2; Hauteur: 80 mm; Largeur: 80 mm; Longueur: 150 mm
BaseQuantities - Length: 150 mm; OuterSurfaceArea: 0.04665 m2; NetVolume: 0.0001824 m3; NetWeight: 1.43184 kg
Pset_ColumnCommon - LoadBearing: no; Reference: 0(?)
Tekla Commun - Repère de pièce: 0(?); Phase: 301; Classe: 99; Matériau: S235JR; Profil: L80*8; Nom: CORNIERE
Name | Niveau bas | Niveau haut | Repère d'assemblage
CORNIERE | +153.185 | +153.335 | A0(?)
CORNIERE | +156.485 | +156.635 | A0(?)
CORNIERE | +159.785 | +159.935 | A0(?)
CORNIERE | +150.685 | +150.835 | A0(?)
CORNIERE | +153.185 | +153.335 | P0(?)
CORNIERE | +156.485 | +156.635 | P0(?)

# IfcColumn: PL20*50 (33)
In: Undefined
Description: PL20*50; Material: STEEL/S235JR
Tekla Commun - Repère de pièce: 0(?); Repère d'assemblage: GC0(?); Phase: 601; Classe: 1; Matériau: S235JR; Profil: PL20*50; Nom: MONTANT
Tekla Quantités - Volume: 0 m3; Surface supérieure totale: 0 m2; Surface par tonne: 18.1 m2; Hauteur: 50 mm; Largeur: 20 mm
Pset_ColumnCommon - LoadBearing: no; Reference: 0(?)
Name | Niveau bas | Niveau haut | Poids (kg) | Surface nette (m2) | Longueur (mm) | Length (mm) | OuterSurfaceArea (m2) | NetVolume (m3) | NetWeight (kg)
2 x MONTANT | +160.110 | +160.990 | 6.9 | 0.1 | 880 | 880 | 0.1252 | 0.00088 | 6.908
8 x MONTANT | +156.810 | +157.690 | 6.9 | 0.1 | 880 | 880 | 0.1252 | 0.00088 | 6.908
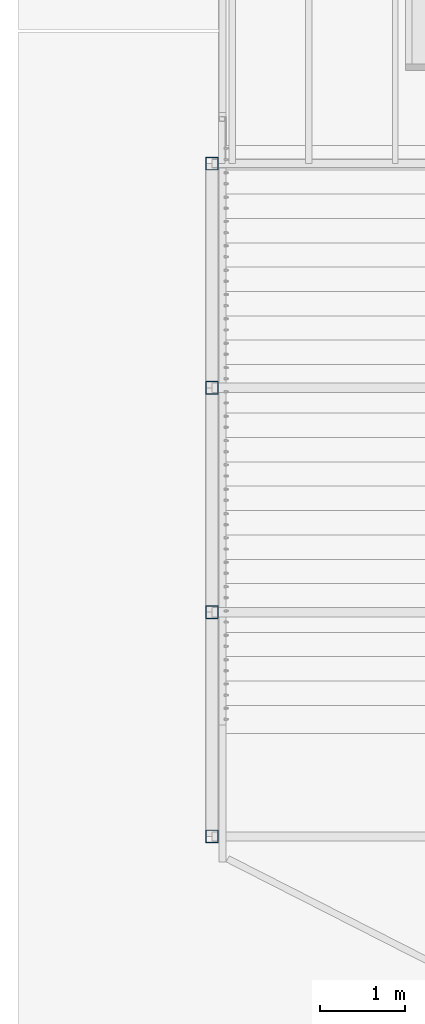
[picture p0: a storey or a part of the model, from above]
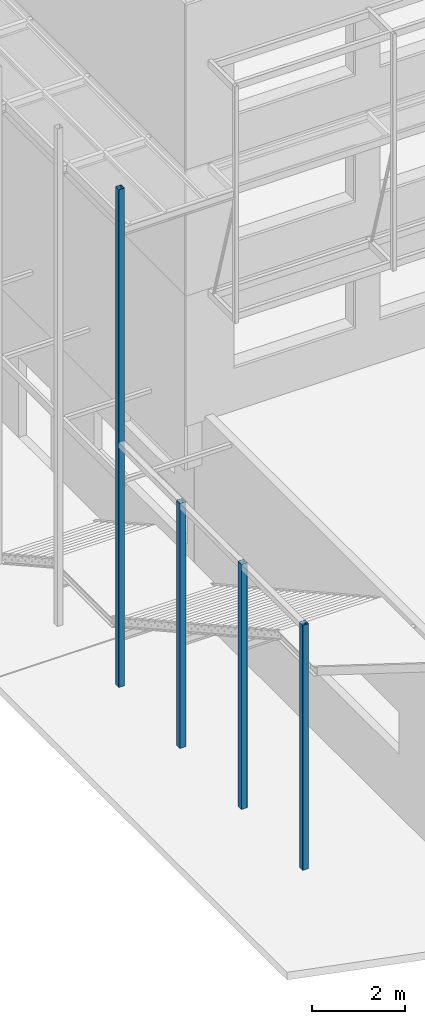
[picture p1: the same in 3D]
Properties of the parts of a building model (IFC2X3), part 2 of 3

# IfcColumn: PL20*50 (33)
Name | Niveau bas | Niveau haut | Poids (kg) | Surface nette (m2) | Longueur (mm) | Length (mm) | OuterSurfaceArea (m2) | NetVolume (m3) | NetWeight (kg)
8 x MONTANT | +156.510 | +157.690 | 9.3 | 0.2 | 1180 | 1180 | 0.1672 | 0.00118 | 9.263
MONTANT | +156.858 | +157.758 | 7.1 | 0.1 | 900 | 900 | 0.128 | 0.0009 | 7.065
MONTANT | +157.466 | +158.360 | 6.9 | 0.1 | 894.1 | 894.101 | 0.126543 | 0.000888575 | 6.97531
MONTANT | +158.074 | +158.968 | 6.9 | 0.1 | 894.1 | 894.101 | 0.126543 | 0.000888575 | 6.97531
MONTANT | +158.682 | +159.576 | 6.9 | 0.1 | 894.1 | 894.101 | 0.126543 | 0.000888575 | 6.97531
MONTANT | +159.290 | +160.184 | 6.9 | 0.1 | 894.1 | 894.101 | 0.126543 | 0.000888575 | 6.97531
MONTANT | +159.897 | +160.797 | 7.1 | 0.1 | 900 | 900 | 0.128 | 0.0009 | 7.065
3 x MONTANT | +159.810 | +160.990 | 9.3 | 0.2 | 1180 | 1180 | 0.1672 | 0.00118 | 9.263
MONTANT | +159.945 | +160.845 | 7.1 | 0.1 | 900 | 900 | 0.128 | 0.0009 | 7.065
MONTANT | +159.337 | +160.231 | 6.9 | 0.1 | 894.1 | 894.101 | 0.126543 | 0.000888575 | 6.97531
MONTANT | +158.729 | +159.623 | 6.9 | 0.1 | 894.1 | 894.101 | 0.126543 | 0.000888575 | 6.97531
MONTANT | +158.121 | +159.015 | 6.9 | 0.1 | 894.1 | 894.101 | 0.126543 | 0.000888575 | 6.97531
MONTANT | +157.513 | +158.407 | 6.9 | 0.1 | 894.1 | 894.101 | 0.126543 | 0.000888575 | 6.97531
MONTANT | +156.905 | +157.805 | 7.1 | 0.1 | 900 | 900 | 0.128 | 0.0009 | 7.065

# IfcColumn: TUBE-C-150*150*10 (2)
In: Undefined
Description: TUBE-C-150*150*10; Material: STEEL/S275JR
Pset_ColumnCommon - LoadBearing: no; Reference: P0(?)
Tekla Commun - Niveau bas: +147.550; Repère de pièce: P0(?); Repère d'assemblage: P0(?); Phase: 301; Classe: 7; Matériau: S275JR; Profil: TUBE-C-150*150*10; Nom: POTEAU
Tekla Quantités - Volume: 0.1 m3; Surface supérieure totale: 0 m2; Surface par tonne: 13.8 m2; Hauteur: 150 mm; Largeur: 150 mm
Name | Niveau haut | Poids (kg) | Surface nette (m2) | Longueur (mm) = Length (mm) | OuterSurfaceArea (m2) | NetVolume (m3) | NetWeight (kg)
POTEAU | +157.700 | 421.6 | 6.1 | 10150 | 5.81595 | 0.05684 | 446.194
POTEAU | +161.000 | 558.6 | 8.1 | 13450 | 7.70685 | 0.07532 | 591.262

# IfcColumn: TUBE-C-150*150*5 (27)
In: Undefined
Description: TUBE-C-150*150*5; Material: STEEL/S275JR
Pset_ColumnCommon - LoadBearing: no
Tekla Commun - Repère d'assemblage: P0(?); Phase: 301; Classe: 7; Matériau: S275JR; Profil: TUBE-C-150*150*5; Nom: POTEAU
Tekla Quantités - Volume: 0 m3; Surface supérieure totale: 0 m2; Surface par tonne: 25.9 m2; Hauteur: 150 mm; Largeur: 150 mm
Name | Reference = Repère de pièce | Niveau bas | Niveau haut | Poids (kg) | Surface nette (m2) | Longueur (mm) = Length (mm) | OuterSurfaceArea (m2) | NetVolume (m3) | NetWeight (kg)
POTEAU | P0(?) | +147.550 | +161.000 | 299.3 | 8.1 | 13450 | 7.7741 | 0.039005 | 306.189
POTEAU | 0(?) | +147.500 | +157.700 | 227 | 6.1 | 10200 | 5.8956 | 0.02958 | 232.203
4 x POTEAU | P0(?) | +147.500 | +157.700 | 227 | 6.1 | 10200 | 5.8956 | 0.02958 | 232.203
POTEAU | P0(?) | +147.550 | +157.700 | 225.9 | 6.1 | 10150 | 5.8667 | 0.029435 | 231.065
POTEAU | P0(?) | +147.590 | +157.700 | 225 | 6.1 | 10110 | 5.84358 | 0.029319 | 230.154
POTEAU | P0(?) | +153.070 | +161.000 | 176.5 | 4.8 | 7930 | 4.58354 | 0.022997 | 180.526
3 x POTEAU | P0(?) | +148.000 | +154.400 | 142.4 | 3.8 | 6400 | 3.6992 | 0.01856 | 145.696
6 x POTEAU | P0(?) | +148.000 | +161.000 | 289.3 | 7.8 | 13000 | 7.514 | 0.0377 | 295.945
POTEAU | P0(?) | +148.000 | +159.970 | 266.4 | 7.2 | 11970 | 6.91866 | 0.034713 | 272.497
5 x POTEAU | 0(?) | +148.000 | +157.700 | 215.9 | 5.8 | 9700 | 5.6066 | 0.02813 | 220.821
3 x POTEAU | P0(?) | +148.000 | +157.700 | 215.9 | 5.8 | 9700 | 5.6066 | 0.02813 | 220.821

# IfcColumn: UPN220, POTEAU
In: Undefined
Description: UPN220; Material: STEEL/S275JR
Tekla Commun - Niveau bas: +147.591; Niveau haut: +148.256; Repère de pièce: P0(?); Repère d'assemblage: P0(?); Phase: 301; Classe: 7; Matériau: S275JR; Profil: UPN220; Nom: POTEAU
Tekla Quantités - Poids: 19.5 kg; Volume: 0 m3; Surface supérieure totale: 0 m2; Surface par tonne: 24.5 m2; Surface nette: 0.4 m2; Hauteur: 220 mm; Largeur: 80 mm; Longueur: 665 mm
Pset_ColumnCommon - LoadBearing: no; Reference: P0(?)
BaseQuantities - Length: 665.04 mm; OuterSurfaceArea: 0.477499 m2; NetVolume: 0.00246323 m3; NetWeight: 19.3363 kg

# IfcElementAssembly (732)
In: Undefined
Name | PredefinedType | Poids Assemblage/Elément béton (kg) | Niveau Bas Assemblage/Elément béton | Niveau Haut Assemblage/Elément béton | Position maillage Assemblage/Elément béton | Repère Assemblage/Elément béton | Width (mm)
POUTRE | RIGID_FRAME | 17 | +149.850 | +150.070 | G-H/1> | A0(?) | 80
POUTRE | RIGID_FRAME | 78.8 | +149.850 | +150.070 | G-H/1 | A0(?) | 80
POTEAU | RIGID_FRAME | 426.1 | +148.000 | +157.700 | <A/6-5 | P0(?) | 2675
LIMON | RIGID_FRAME | 367.6 | +156.450 | +159.970 | <A/8-5 | L0(?) | 160
LIMON | RIGID_FRAME | 368.9 | +153.150 | +156.670 | <A/8-5 | L0(?) | 80
SOLIVE | RIGID_FRAME | 78.4 | +156.450 | +156.670 | <A/5 | A0(?) | 251.781
POUTRE |  | 218.9 | +159.850 | +163.470 | A/5 | Po0(?) | 280
POUTRE |  | 199.6 | +156.550 | +159.850 | A/5 | Po0(?) | 280
POUTRE |  | 190.5 | +153.400 | +156.550 | A/5 | Po0(?) | 280
LIMON | RIGID_FRAME | 368.9 | +149.850 | +153.370 | G-H/1> | L0(?) | 80
LIMON | RIGID_FRAME | 368.9 | +153.150 | +156.670 | G-H/1> | L0(?) | 80
LIMON | RIGID_FRAME | 368.9 | +156.450 | +159.970 | G-H/1> | L0(?) | 80
POUTRE | RIGID_FRAME | 120.6 | +153.070 | +153.370 | I/1> | A0(?) | 100
POUTRE | RIGID_FRAME | 76.7 | +156.450 | +156.670 | I/1> | A0(?) | 80
MAIN_COURANTE | RIGID_FRAME | 92.8 | +159.810 | +161.000 | C-D/12-11 | GC0(?) | 1190
PANNEAU | RIGID_FRAME | 54434.9 | +160.000 | +164.300 | <A-G/5 | PA0(?) | 75
PANNEAU | RIGID_FRAME | 40543.4 | +156.700 | +160.000 | <A-G/5 | PA0(?) | 75
PANNEAU | RIGID_FRAME | 58602.4 | +152.100 | +156.700 | <A-G/5 | PA0(?) | 75
PANNEAU | RIGID_FRAME | 33928.9 | +160.000 | +164.300 | G/5-1> | PA0(?) | 75
PANNEAU | RIGID_FRAME | 22739.6 | +156.700 | +160.000 | G/5-1> | PA0(?) | 75
PANNEAU | RIGID_FRAME | 34828.7 | +152.100 | +156.700 | G/5-1> | PA0(?) | 75
PANNEAU | RIGID_FRAME | 48862 | +160.000 | +164.300 | G-J/1> | PA0(?) | 75
PANNEAU | RIGID_FRAME | 36677.2 | +156.700 | +160.000 | G-J/1> | PA0(?) | 75
PANNEAU | RIGID_FRAME | 52517.4 | +152.100 | +156.700 | G-J/1> | PA0(?) | 75
PANNEAU | RIGID_FRAME | 43171.3 | +156.700 | +161.000 | G/<15-11 | PA0(?) | 75
PANNEAU | RIGID_FRAME | 67751.1 | +160.000 | +164.300 | <A-J/11 | PA0(?) | 75
PANNEAU | RIGID_FRAME | 30645.3 | +156.700 | +160.000 | <A-G/11 | PA0(?) | 75
PANNEAU | RIGID_FRAME | 32182.6 | +153.291 | +156.700 | <A-G/11 | PA0(?) | 75
PANNEAU | RIGID_FRAME | 48440.7 | +160.000 | +164.300 | <A/11-5 | PA0(?) | 75
PANNEAU | RIGID_FRAME | 36491.4 | +156.700 | +160.000 | <A/11-5 | PA0(?) | 75
PANNEAU | RIGID_FRAME | 51201.2 | +152.100 | +156.700 | <A/11-5 | PA0(?) | 75
STAB | RIGID_FRAME | 5.2 | +156.458 | +156.508 | <A/6-5 | A0(?) | 50
2 x SOLIVE | RIGID_FRAME | 33.4 | +156.530 | +156.670 | <A/6-5 | A0(?) | 73
STAB | RIGID_FRAME | 11.3 | +156.458 | +156.508 | <A/6-5 | A0(?) | 50
SOLIVE | RIGID_FRAME | 32.6 | +156.530 | +156.670 | <A/6-5 | A0(?) | 73
POTEAU | RIGID_FRAME | 221.2 | +148.000 | +157.700 | <A/5 | P0(?) | 350
MAIN_COURANTE | RIGID_FRAME | 66.3 | +156.510 | +157.700 | <A/6-5 | GC0(?) | 1190
SOLIVE | RIGID_FRAME | 77.2 | +156.450 | +156.670 | <A/6-5 | A0(?) | 287.941
MAIN_COURANTE | RIGID_FRAME | 71.5 | +156.510 | +157.700 | <A/7-5 | GC0(?) | 1190
SOLIVE | RIGID_FRAME | 179.5 | +156.450 | +156.670 | <A/8-5 | A0(?) | 80
3 x CORNIERE | RIGID_FRAME | 2.4 | +156.480 | +156.640 | <A/6-5 | A0(?) | 100
SOLIVE | RIGID_FRAME | 39.7 | +156.530 | +156.670 | <A/7-5 | A0(?) | 73
SOLIVE | RIGID_FRAME | 54.6 | +156.450 | +156.670 | <A/6-5 | A0(?) | 298.009
GOUSSET | RIGID_FRAME | 3.1 | +156.450 | +156.458 | <A/6-5 | G0(?) | 8
STAB | RIGID_FRAME | 5.7 | +156.458 | +156.508 | <A/6-5 | A0(?) | 50
STAB | RIGID_FRAME | 5.3 | +156.458 | +156.508 | <A/6-5 | A0(?) | 50
GOUSSET | RIGID_FRAME | 3.6 | +156.450 | +156.458 | <A/6-5 | G0(?) | 8
STAB | RIGID_FRAME | 5.5 | +156.458 | +156.508 | <A/6-5 | A0(?) | 50
POTEAU | RIGID_FRAME | 218.3 | +148.000 | +157.700 | <A/5 | P0(?) | 250
POTEAU | RIGID_FRAME | 216.9 | +148.000 | +157.700 | <A/6-5 | P0(?) | 230
SOLIVE | RIGID_FRAME | 90.5 | +156.450 | +156.670 | <A/7-5 | A0(?) | 135
SOLIVE | RIGID_FRAME | 61.5 | +156.450 | +156.670 | <A/5 | A0(?) | 250.059
STAB | RIGID_FRAME | 11 | +156.458 | +156.508 | <A/6-5 | A0(?) | 50
STAB | RIGID_FRAME | 12.3 | +156.507 | +156.557 | H-I/1> | A0(?) | 50
POUTRE | RIGID_FRAME | 79.1 | +156.450 | +156.670 | H-I/1> | A0(?) | 191.883
POTEAU | RIGID_FRAME | 232.4 | +147.500 | +157.700 | I/1> | P0(?) | 250
POUTRE | RIGID_FRAME | 61.2 | +156.450 | +156.670 | I/1> | A0(?) | 80
POTEAU | RIGID_FRAME | 220.7 | +148.000 | +157.700 | <A/5 | P0(?) | 250
MAIN_COURANTE | RIGID_FRAME | 66.3 | +156.510 | +157.700 | H-I/1> | GC0(?) | 1190
MAIN_COURANTE | RIGID_FRAME | 71.5 | +156.510 | +157.700 | G-H/1> | GC0(?) | 1190
LIMON | RIGID_FRAME | 44.6 | +153.150 | +153.370 | A/14-13 | L0(?) | 80
SOLIVE | RIGID_FRAME | 58.4 | +154.250 | +154.400 | <A/12-11 | A0(?) | 150
SOLIVE | RIGID_FRAME | 58.4 | +154.250 | +154.400 | <A/14-12 | A0(?) | 150
SOLIVE | RIGID_FRAME | 58.4 | +154.250 | +154.400 | <A/13-12 | A0(?) | 150
STAB | RIGID_FRAME | 8.3 | +150.680 | +150.730 | <A/6-5 | A0(?) | 50
SOLIVE | RIGID_FRAME | 16.8 | +150.730 | +150.870 | <A/6-5 | A0(?) | 73
POUTRE | RIGID_FRAME | 28.8 | +150.730 | +150.870 | <A/6 | A0(?) | 60
GOUSSET | RIGID_FRAME | 1723.7 | +149.395 | +149.425 | <A/12-9 | G0(?) | 30
LIMON | RIGID_FRAME | 282.5 | +149.175 | +153.370 | A/13-11 | L0(?) | 80
LIMON | RIGID_FRAME | 291.3 | +149.175 | +153.370 | <A/13-11 | L0(?) | 80
CAILLEBOTIS | RIGID_FRAME | 3713.5 | +150.870 | +150.900 | <A/6-5 | G0(?) | 30
CAILLEBOTIS | RIGID_FRAME | 8351.3 | +153.370 | +153.400 | <A/8-5 | G0(?) | 30
2 x LIMON | RIGID_FRAME | 111.6 | +147.356 | +148.475 | G-H/1> | L0(?) | 80
MARCHE | RIGID_FRAME | 317.9 | +148.276 | +148.346 | G-H/1> | MA0(?) | 1800
2 x LIMON | RIGID_FRAME | 213.2 | +148.255 | +150.070 | G-H/1> | L0(?) | 80
MARCHE | RIGID_FRAME | 317.9 | +149.871 | +149.941 | G-H/1> | MA0(?) | 1800
MARCHE | RIGID_FRAME | 317.9 | +148.116 | +148.186 | G-H/1> | MA0(?) | 1800
MARCHE | RIGID_FRAME | 317.9 | +149.711 | +149.781 | G-H/1> | MA0(?) | 1800
MAIN_COURANTE | RIGID_FRAME | 120 | +156.905 | +160.850 | <A/7-5 | GC0(?) | 797.391
MAIN_COURANTE | RIGID_FRAME | 120 | +156.858 | +160.803 | G-H/1> | GC0(?) | 797.391
GOUSSET | RIGID_FRAME | 1910.3 | +148.475 | +148.505 | G-H/1> | G0(?) | 30
POUTRE | RIGID_FRAME | 93 | +156.450 | +156.670 | G-H/1> | A0(?) | 135
CAILLEBOTIS | RIGID_FRAME | 2780.2 | +150.070 | +150.100 | G-H/1> | G0(?) | 30
CAILLEBOTIS | RIGID_FRAME | 8431.4 | +153.370 | +153.400 | G-I/1> | G0(?) | 30
CAILLEBOTIS | RIGID_FRAME | 8431.4 | +156.670 | +156.700 | G-I/1> | G0(?) | 30
GOUSSET | RIGID_FRAME | 1347.9 | +159.970 | +160.000 | H-I/1> | G0(?) | 30
POUTRE |  | 278.6 | +156.320 | +156.480 | G-J/1 | Po0(?) | 100
POUTRE |  | 1504.7 | +156.000 | +156.360 | G-J/1 | Po0(?) | 240
POUTRE |  | 278.6 | +159.620 | +159.780 | G-J/1 | Po0(?) | 100
POUTRE |  | 1504.7 | +159.300 | +159.660 | G-J/1 | Po0(?) | 240
POUTRE |  | 116.5 | +162.852 | +163.347 | I-J/1 | Po0(?) | 100
POUTRE |  | 637.6 | +162.651 | +163.346 | I-J/1 | Po0(?) | 240
POUTRE |  | 34.4 | +162.833 | +163.071 | H-I/1 | Po0(?) | 100
POUTRE |  | 201.4 | +162.630 | +163.070 | H-I/1 | Po0(?) | 240
POUTRE |  | 118.1 | +162.935 | +163.349 | G-H/1 | Po0(?) | 100
POUTRE |  | 637.6 | +162.736 | +163.350 | G-H/1 | Po0(?) | 240
POUTRE |  | 221.2 | +153.350 | +156.550 | H/1 | Po0(?) | 240
POUTRE |  | 190.5 | +153.400 | +156.550 | J/1 | Po0(?) | 240
POUTRE |  | 190.5 | +153.400 | +156.550 | G/1 | Po0(?) | 240
POUTRE |  | 202.6 | +156.550 | +159.900 | J/1 | Po0(?) | 240
POUTRE |  | 202.6 | +156.550 | +159.900 | G/1 | Po0(?) | 240
2 x POUTRE |  | 262 | +153.301 | +156.339 | I-J/1 | Po0(?) | 240
2 x POUTRE |  | 262 | +153.301 | +156.339 | G-H/1 | Po0(?) | 240
2 x POUTRE |  | 276.1 | +156.146 | +159.634 | I-J/1 | Po0(?) | 240
2 x POUTRE |  | 276.1 | +156.146 | +159.634 | G-H/1 | Po0(?) | 240
POUTRE |  | 217.7 | +153.400 | +156.550 | I/1 | Po0(?) | 240
POUTRE |  | 228.1 | +156.550 | +159.850 | H/1 | Po0(?) | 240
POUTRE |  | 228.1 | +156.550 | +159.850 | I/1 | Po0(?) | 240
POUTRE |  | 232.2 | +159.850 | +163.210 | H/1 | Po0(?) | 240
POUTRE |  | 226.7 | +159.850 | +163.130 | I/1 | Po0(?) | 240
POUTRE |  | 215.9 | +159.900 | +163.470 | J/1 | Po0(?) | 240
POUTRE |  | 215.9 | +159.900 | +163.470 | G/1 | Po0(?) | 240
2 x POUTRE |  | 281.3 | +159.448 | +163.094 | I-J/1 | Po0(?) | 240
2 x POUTRE |  | 282.8 | +159.448 | +163.136 | G-H/1 | Po0(?) | 240
SOLIVE | RIGID_FRAME | 87 | +159.790 | +159.970 | C-D/12-11 | A0(?) | 125
LIMON | RIGID_FRAME | 209.2 | +149.838 | +153.370 | G-H/1> | L0(?) | 80
POUTRE | RIGID_FRAME | 60.1 | +149.830 | +150.070 | G-H/1> | A0(?) | 143.1
LIMON | RIGID_FRAME | 209.2 | +153.138 | +156.670 | G-H/1> | L0(?) | 80
CONSOLE | RIGID_FRAME | 62.4 | +153.130 | +153.370 | G-H/1> | A0(?) | 143.1
LIMON | RIGID_FRAME | 209.2 | +156.438 | +159.970 | G-H/1> | L0(?) | 80
CONSOLE | RIGID_FRAME | 62.4 | +156.430 | +156.670 | G-H/1> | A0(?) | 143.1
CONSOLE | RIGID_FRAME | 62.4 | +153.130 | +153.370 | H/1> | A0(?) | 143.1
CONSOLE | RIGID_FRAME | 62.4 | +156.430 | +156.670 | H/1> | A0(?) | 143.1
CONSOLE | RIGID_FRAME | 62.4 | +159.730 | +159.970 | H/1> | A0(?) | 143.1
2 x LIMON | RIGID_FRAME | 188.2 | +147.798 | +150.870 | <A/7-5 | L0(?) | 80
SOLIVE | RIGID_FRAME | 59.8 | +150.650 | +150.870 | <A/6-5 | A0(?) | 137.95
LIMON | RIGID_FRAME | 202.9 | +150.650 | +153.370 | <A/8-6 | L0(?) | 80
SOLIVE | RIGID_FRAME | 62.8 | +153.130 | +153.370 | <A/8-7 | A0(?) | 143.1
LIMON | RIGID_FRAME | 209.2 | +153.138 | +156.670 | <A/8-5 | L0(?) | 80
SOLIVE | RIGID_FRAME | 62.8 | +156.430 | +156.670 | <A/8-7 | A0(?) | 143.1
MARCHE | RIGID_FRAME | 317.9 | +156.473 | +156.543 | <A/8-7 | MA0(?) | 1800
MARCHE | RIGID_FRAME | 317.9 | +156.315 | +156.385 | <A/7 | MA0(?) | 1800
MARCHE | RIGID_FRAME | 317.9 | +156.158 | +156.228 | <A/7 | MA0(?) | 1800
MARCHE | RIGID_FRAME | 317.9 | +156.000 | +156.070 | <A/7-6 | MA0(?) | 1800
MARCHE | RIGID_FRAME | 317.9 | +155.843 | +155.913 | <A/7-6 | MA0(?) | 1800
MARCHE | RIGID_FRAME | 317.9 | +155.685 | +155.755 | <A/7-6 | MA0(?) | 1800
MARCHE | RIGID_FRAME | 317.9 | +155.528 | +155.598 | <A/7-6 | MA0(?) | 1800
MARCHE | RIGID_FRAME | 317.9 | +155.370 | +155.440 | <A/7-6 | MA0(?) | 1800
MARCHE | RIGID_FRAME | 317.9 | +155.213 | +155.283 | <A/7-6 | MA0(?) | 1800
MARCHE | RIGID_FRAME | 317.9 | +155.055 | +155.125 | <A/7-6 | MA0(?) | 1800
MARCHE | RIGID_FRAME | 317.9 | +154.898 | +154.968 | <A/7-6 | MA0(?) | 1800
MARCHE | RIGID_FRAME | 317.9 | +154.740 | +154.810 | <A/7-6 | MA0(?) | 1800
MARCHE | RIGID_FRAME | 317.9 | +154.583 | +154.653 | <A/7-6 | MA0(?) | 1800
MARCHE | RIGID_FRAME | 317.9 | +154.425 | +154.495 | <A/7-6 | MA0(?) | 1800
MARCHE | RIGID_FRAME | 317.9 | +154.268 | +154.338 | <A/7-6 | MA0(?) | 1800
MARCHE | RIGID_FRAME | 317.9 | +154.110 | +154.180 | <A/6 | MA0(?) | 1800
MARCHE | RIGID_FRAME | 317.9 | +153.953 | +154.023 | <A/6 | MA0(?) | 1800
MARCHE | RIGID_FRAME | 317.9 | +153.795 | +153.865 | <A/6-5 | MA0(?) | 1800
MARCHE | RIGID_FRAME | 317.9 | +153.638 | +153.708 | <A/6-5 | MA0(?) | 1800
MARCHE | RIGID_FRAME | 317.9 | +153.480 | +153.550 | <A/6-5 | MA0(?) | 1800
LIMON | RIGID_FRAME | 209.2 | +156.438 | +159.970 | <A/8-5 | L0(?) | 80
SOLIVE | RIGID_FRAME | 63.8 | +159.730 | +159.970 | <A/8-7 | A0(?) | 143.1
POTEAU | RIGID_FRAME | 19.5 | +147.591 | +148.256 | G-H/1> | P0(?) | 80
2 x POUTRE | RIGID_FRAME | 22.4 | +148.335 | +148.475 | G-H/1> | A0(?) | 73
2 x POUTRE | RIGID_FRAME | 33.9 | +148.315 | +148.475 | G-H/1> | A0(?) | 65
POUTRE | RIGID_FRAME | 116.6 | +148.255 | +148.475 | G-H/1> | A0(?) | 80
POUTRE | RIGID_FRAME | 33.9 | +149.910 | +150.070 | G-H/1> | A0(?) | 65
MARCHE | RIGID_FRAME | 317.9 | +147.957 | +148.027 | G-H/1> | MA0(?) | 1800
MARCHE | RIGID_FRAME | 317.9 | +147.797 | +147.867 | G-H/1> | MA0(?) | 1800
MARCHE | RIGID_FRAME | 317.9 | +147.638 | +147.708 | G-H/1> | MA0(?) | 1800
MARCHE | RIGID_FRAME | 317.9 | +153.173 | +153.243 | H/1> | MA0(?) | 1800
MARCHE | RIGID_FRAME | 317.9 | +153.015 | +153.085 | G-H/1> | MA0(?) | 1800
MARCHE | RIGID_FRAME | 317.9 | +152.858 | +152.928 | G-H/1> | MA0(?) | 1800
MARCHE | RIGID_FRAME | 317.9 | +152.700 | +152.770 | G-H/1> | MA0(?) | 1800
MARCHE | RIGID_FRAME | 317.9 | +152.543 | +152.613 | G-H/1> | MA0(?) | 1800
MARCHE | RIGID_FRAME | 317.9 | +152.385 | +152.455 | G-H/1> | MA0(?) | 1800
MARCHE | RIGID_FRAME | 317.9 | +152.228 | +152.298 | G-H/1> | MA0(?) | 1800
MARCHE | RIGID_FRAME | 317.9 | +152.070 | +152.140 | G-H/1> | MA0(?) | 1800
MARCHE | RIGID_FRAME | 317.9 | +151.913 | +151.983 | G-H/1> | MA0(?) | 1800
MARCHE | RIGID_FRAME | 317.9 | +151.755 | +151.825 | G-H/1> | MA0(?) | 1800
MARCHE | RIGID_FRAME | 317.9 | +151.598 | +151.668 | G-H/1> | MA0(?) | 1800
MARCHE | RIGID_FRAME | 317.9 | +151.440 | +151.510 | G-H/1> | MA0(?) | 1800
MARCHE | RIGID_FRAME | 317.9 | +151.283 | +151.353 | G-H/1> | MA0(?) | 1800
MARCHE | RIGID_FRAME | 317.9 | +151.125 | +151.195 | G-H/1> | MA0(?) | 1800
MARCHE | RIGID_FRAME | 317.9 | +150.968 | +151.038 | G-H/1> | MA0(?) | 1800
MARCHE | RIGID_FRAME | 317.9 | +150.810 | +150.880 | G-H/1> | MA0(?) | 1800
MARCHE | RIGID_FRAME | 317.9 | +150.653 | +150.723 | G-H/1> | MA0(?) | 1800
MARCHE | RIGID_FRAME | 317.9 | +150.495 | +150.565 | G-H/1> | MA0(?) | 1800
MARCHE | RIGID_FRAME | 317.9 | +150.338 | +150.408 | G-H/1> | MA0(?) | 1800
MARCHE | RIGID_FRAME | 317.9 | +150.180 | +150.250 | G-H/1> | MA0(?) | 1800
MARCHE | RIGID_FRAME | 317.9 | +148.914 | +148.984 | G-H/1> | MA0(?) | 1800
MARCHE | RIGID_FRAME | 317.9 | +148.754 | +148.824 | G-H/1> | MA0(?) | 1800
MARCHE | RIGID_FRAME | 317.9 | +149.073 | +149.143 | G-H/1> | MA0(?) | 1800
MARCHE | RIGID_FRAME | 317.9 | +149.233 | +149.303 | G-H/1> | MA0(?) | 1800
MARCHE | RIGID_FRAME | 317.9 | +148.595 | +148.665 | G-H/1> | MA0(?) | 1800
MARCHE | RIGID_FRAME | 317.9 | +149.392 | +149.462 | G-H/1> | MA0(?) | 1800
MARCHE | RIGID_FRAME | 317.9 | +149.552 | +149.622 | G-H/1> | MA0(?) | 1800
MARCHE | RIGID_FRAME | 317.9 | +156.473 | +156.543 | H/1> | MA0(?) | 1800
MARCHE | RIGID_FRAME | 317.9 | +156.315 | +156.385 | G-H/1> | MA0(?) | 1800
MARCHE | RIGID_FRAME | 317.9 | +156.158 | +156.228 | G-H/1> | MA0(?) | 1800
MARCHE | RIGID_FRAME | 317.9 | +156.000 | +156.070 | G-H/1> | MA0(?) | 1800
MARCHE | RIGID_FRAME | 317.9 | +155.843 | +155.913 | G-H/1> | MA0(?) | 1800
MARCHE | RIGID_FRAME | 317.9 | +155.685 | +155.755 | G-H/1> | MA0(?) | 1800
MARCHE | RIGID_FRAME | 317.9 | +155.528 | +155.598 | G-H/1> | MA0(?) | 1800
MARCHE | RIGID_FRAME | 317.9 | +155.370 | +155.440 | G-H/1> | MA0(?) | 1800
MARCHE | RIGID_FRAME | 317.9 | +155.213 | +155.283 | G-H/1> | MA0(?) | 1800
MARCHE | RIGID_FRAME | 317.9 | +155.055 | +155.125 | G-H/1> | MA0(?) | 1800
MARCHE | RIGID_FRAME | 317.9 | +154.898 | +154.968 | G-H/1> | MA0(?) | 1800
MARCHE | RIGID_FRAME | 317.9 | +154.740 | +154.810 | G-H/1> | MA0(?) | 1800
MARCHE | RIGID_FRAME | 317.9 | +154.583 | +154.653 | G-H/1> | MA0(?) | 1800
MARCHE | RIGID_FRAME | 317.9 | +154.425 | +154.495 | G-H/1> | MA0(?) | 1800
MARCHE | RIGID_FRAME | 317.9 | +154.268 | +154.338 | G-H/1> | MA0(?) | 1800
MARCHE | RIGID_FRAME | 317.9 | +154.110 | +154.180 | G-H/1> | MA0(?) | 1800
MARCHE | RIGID_FRAME | 317.9 | +153.953 | +154.023 | G-H/1> | MA0(?) | 1800
MARCHE | RIGID_FRAME | 317.9 | +153.795 | +153.865 | G-H/1> | MA0(?) | 1800
MARCHE | RIGID_FRAME | 317.9 | +153.638 | +153.708 | G-H/1> | MA0(?) | 1800
MARCHE | RIGID_FRAME | 317.9 | +153.480 | +153.550 | G-H/1> | MA0(?) | 1800
MARCHE | RIGID_FRAME | 317.9 | +159.773 | +159.843 | H/1> | MA0(?) | 1800
MARCHE | RIGID_FRAME | 317.9 | +159.615 | +159.685 | G-H/1> | MA0(?) | 1800
MARCHE | RIGID_FRAME | 317.9 | +159.458 | +159.528 | G-H/1> | MA0(?) | 1800
MARCHE | RIGID_FRAME | 317.9 | +159.300 | +159.370 | G-H/1> | MA0(?) | 1800
MARCHE | RIGID_FRAME | 317.9 | +159.143 | +159.213 | G-H/1> | MA0(?) | 1800
MARCHE | RIGID_FRAME | 317.9 | +158.985 | +159.055 | G-H/1> | MA0(?) | 1800
MARCHE | RIGID_FRAME | 317.9 | +158.828 | +158.898 | G-H/1> | MA0(?) | 1800
MARCHE | RIGID_FRAME | 317.9 | +158.670 | +158.740 | G-H/1> | MA0(?) | 1800
MARCHE | RIGID_FRAME | 317.9 | +158.513 | +158.583 | G-H/1> | MA0(?) | 1800
MARCHE | RIGID_FRAME | 317.9 | +158.355 | +158.425 | G-H/1> | MA0(?) | 1800
MARCHE | RIGID_FRAME | 317.9 | +158.198 | +158.268 | G-H/1> | MA0(?) | 1800
MARCHE | RIGID_FRAME | 317.9 | +158.040 | +158.110 | G-H/1> | MA0(?) | 1800
MARCHE | RIGID_FRAME | 317.9 | +157.883 | +157.953 | G-H/1> | MA0(?) | 1800
MARCHE | RIGID_FRAME | 317.9 | +157.725 | +157.795 | G-H/1> | MA0(?) | 1800
MARCHE | RIGID_FRAME | 317.9 | +157.568 | +157.638 | G-H/1> | MA0(?) | 1800
MARCHE | RIGID_FRAME | 317.9 | +157.410 | +157.480 | G-H/1> | MA0(?) | 1800
MARCHE | RIGID_FRAME | 317.9 | +157.253 | +157.323 | G-H/1> | MA0(?) | 1800
MARCHE | RIGID_FRAME | 317.9 | +157.095 | +157.165 | G-H/1> | MA0(?) | 1800
MARCHE | RIGID_FRAME | 317.9 | +156.938 | +157.008 | G-H/1> | MA0(?) | 1800
MARCHE | RIGID_FRAME | 317.9 | +156.780 | +156.850 | G-H/1> | MA0(?) | 1800
SOLIVE | RIGID_FRAME | 33.9 | +159.830 | +159.970 | H-I/1> | A0(?) | 73
2 x STAB | RIGID_FRAME | 12.7 | +159.780 | +159.830 | H-I/1> | A0(?) | 50
POUTRE | RIGID_FRAME | 79.3 | +159.750 | +159.970 | H-I/1> | A0(?) | 80
POUTRE | RIGID_FRAME | 78.8 | +159.750 | +159.970 | I/1> | A0(?) | 80
POTEAU | RIGID_FRAME | 299.3 | +147.550 | +161.000 | I/1> | P0(?) | 150
SOLIVE | RIGID_FRAME | 33.9 | +156.530 | +156.670 | H-I/1> | A0(?) | 73
2 x STAB | RIGID_FRAME | 12.7 | +156.480 | +156.530 | H-I/1> | A0(?) | 50
SOLIVE | RIGID_FRAME | 32.8 | +156.530 | +156.670 | G-H/1> | A0(?) | 73
2 x STAB | RIGID_FRAME | 12.7 | +156.480 | +156.530 | G-H/1> | A0(?) | 50
2 x STAB | RIGID_FRAME | 13.1 | +156.480 | +156.530 | G-H/1> | A0(?) | 50
STAB | RIGID_FRAME | 13.1 | +156.507 | +156.557 | H-I/1> | A0(?) | 50
4 x STAB | RIGID_FRAME | 14.3 | +156.480 | +156.530 | G-H/1> | A0(?) | 50
2 x POUTRE | RIGID_FRAME | 33.9 | +156.530 | +156.670 | H-I/1> | A0(?) | 73
2 x POUTRE | RIGID_FRAME | 33.9 | +156.530 | +156.670 | G-H/1> | A0(?) | 73
2 x POUTRE | RIGID_FRAME | 39.9 | +156.530 | +156.670 | G-H/1> | A0(?) | 73
2 x POUTRE | RIGID_FRAME | 53 | +156.450 | +156.670 | G-H/1> | A0(?) | 110
POUTRE | RIGID_FRAME | 53 | +156.450 | +156.670 | H/1> | A0(?) | 110
POUTRE | RIGID_FRAME | 182 | +156.450 | +156.670 | G-H/1> | A0(?) | 80
POUTRE | RIGID_FRAME | 63.7 | +156.450 | +156.670 | G/1> | A0(?) | 80
POUTRE | RIGID_FRAME | 76.7 | +156.450 | +156.670 | G/1> | A0(?) | 80
POUTRE | RIGID_FRAME | 91 | +156.450 | +156.670 | G-H/1> | A0(?) | 80
POUTRE | RIGID_FRAME | 79.3 | +156.450 | +156.670 | G-H/1> | A0(?) | 80
SOLIVE | RIGID_FRAME | 33.9 | +153.230 | +153.370 | H-I/1> | A0(?) | 73
2 x STAB | RIGID_FRAME | 12.7 | +153.180 | +153.230 | H-I/1> | A0(?) | 50
SOLIVE | RIGID_FRAME | 33.9 | +153.230 | +153.370 | G-H/1> | A0(?) | 73
2 x STAB | RIGID_FRAME | 12.7 | +153.180 | +153.230 | G-H/1> | A0(?) | 50
2 x STAB | RIGID_FRAME | 13.1 | +153.180 | +153.230 | G-H/1> | A0(?) | 50
2 x STAB | RIGID_FRAME | 13.1 | +153.180 | +153.230 | H-I/1> | A0(?) | 50
4 x STAB | RIGID_FRAME | 14.3 | +153.180 | +153.230 | G-H/1> | A0(?) | 50
2 x POUTRE | RIGID_FRAME | 33.9 | +153.230 | +153.370 | H-I/1> | A0(?) | 73
2 x POUTRE | RIGID_FRAME | 33.9 | +153.230 | +153.370 | G-H/1> | A0(?) | 73
POUTRE | RIGID_FRAME | 100.2 | +153.070 | +153.370 | I/1> | A0(?) | 100
2 x POUTRE | RIGID_FRAME | 39.9 | +153.230 | +153.370 | G-H/1> | A0(?) | 73
2 x POUTRE | RIGID_FRAME | 53 | +153.150 | +153.370 | G-H/1> | A0(?) | 110
POUTRE | RIGID_FRAME | 53 | +153.150 | +153.370 | H/1> | A0(?) | 110
POUTRE | RIGID_FRAME | 182 | +153.150 | +153.370 | G-H/1> | A0(?) | 80
POUTRE | RIGID_FRAME | 63.7 | +153.150 | +153.370 | G/1> | A0(?) | 80
POUTRE | RIGID_FRAME | 76.7 | +153.150 | +153.370 | G/1> | A0(?) | 80
STAB | RIGID_FRAME | 79.3 | +153.150 | +153.370 | H-I/1> | A0(?) | 80
2 x STAB | RIGID_FRAME | 91 | +153.150 | +153.370 | G-H/1> | A0(?) | 80
STAB | RIGID_FRAME | 79.3 | +153.150 | +153.370 | G-H/1> | A0(?) | 80
SOLIVE | RIGID_FRAME | 26 | +149.930 | +150.070 | G-H/1> | A0(?) | 73
SOLIVE | RIGID_FRAME | 33.9 | +149.930 | +150.070 | G-H/1> | A0(?) | 73
2 x STAB | RIGID_FRAME | 12.7 | +149.880 | +149.930 | G-H/1> | A0(?) | 50
POUTRE | RIGID_FRAME | 32.8 | +149.930 | +150.070 | G-H/1> | A0(?) | 73
POUTRE | RIGID_FRAME | 63.7 | +149.850 | +150.070 | G/1> | A0(?) | 80
POUTRE | RIGID_FRAME | 75.2 | +149.850 | +150.070 | G/1> | A0(?) | 80
POTEAU | RIGID_FRAME | 421.6 | +147.550 | +157.700 | G-H/1> | P0(?) | 150
POTEAU | RIGID_FRAME | 558.6 | +147.550 | +161.000 | H/1> | P0(?) | 150
POTEAU | RIGID_FRAME | 227 | +147.500 | +157.700 | H/1> | P0(?) | 150
2 x POTEAU | RIGID_FRAME | 227 | +147.500 | +157.700 | G-H/1> | P0(?) | 150
POTEAU | RIGID_FRAME | 227 | +147.500 | +157.700 | G/1> | P0(?) | 150
POTEAU | RIGID_FRAME | 225.9 | +147.550 | +157.700 | G/1> | P0(?) | 150
POTEAU | RIGID_FRAME | 225 | +147.590 | +157.700 | G/1> | P0(?) | 150
POTEAU | RIGID_FRAME | 176.5 | +153.070 | +161.000 | I/1> | P0(?) | 150
CONSOLE | RIGID_FRAME | 170.6 | +156.490 | +162.680 | C/12-11 | A0(?) | 300.008
SOLIVE | RIGID_FRAME | 84.1 | +159.790 | +159.970 | B-C/12-11 | A0(?) | 70
GOUSSET | RIGID_FRAME | 1300.5 | +153.370 | +153.400 | <A/14-13 | G0(?) | 30
GOUSSET | RIGID_FRAME | 8378.9 | +156.670 | +156.700 | <A/8-5 | G0(?) | 30
POUTRE | RIGID_FRAME | 71.7 | +148.955 | +149.175 | <A/10-9 | A0(?) | 110
POUTRE | RIGID_FRAME | 71.7 | +152.110 | +152.330 | <A/13-12 | A0(?) | 110
POUTRE | RIGID_FRAME | 71.7 | +150.645 | +150.865 | <A/12 | A0(?) | 110
POUTRE | RIGID_FRAME | 71.7 | +149.180 | +149.400 | <A/12-11 | A0(?) | 110
LIMON | RIGID_FRAME | 159.4 | +147.802 | +149.395 | A/10-9 | L0(?) | 80
LIMON | RIGID_FRAME | 159.4 | +147.802 | +149.395 | <A/10-9 | L0(?) | 80
POUTRE | RIGID_FRAME | 71.7 | +153.150 | +153.370 | <A/14-13 | A0(?) | 110
POUTRE | RIGID_FRAME | 84.8 | +153.150 | +153.370 | <A/14-13 | A0(?) | 80
MARCHE | RIGID_FRAME | 423.9 | +153.171 | +153.241 | <A/13 | MA0(?) | 2400
MARCHE | RIGID_FRAME | 423.9 | +153.012 | +153.082 | <A/13 | MA0(?) | 2400
MARCHE | RIGID_FRAME | 423.9 | +152.853 | +152.923 | <A/13-12 | MA0(?) | 2400
MARCHE | RIGID_FRAME | 423.9 | +152.694 | +152.764 | <A/13-12 | MA0(?) | 2400
MARCHE | RIGID_FRAME | 423.9 | +152.535 | +152.605 | <A/13-12 | MA0(?) | 2400
MARCHE | RIGID_FRAME | 423.9 | +152.376 | +152.446 | <A/13-12 | MA0(?) | 2400
MARCHE | RIGID_FRAME | 423.9 | +152.217 | +152.287 | <A/13-12 | MA0(?) | 2400
MARCHE | RIGID_FRAME | 423.9 | +152.058 | +152.128 | <A/13-12 | MA0(?) | 2400
MARCHE | RIGID_FRAME | 423.9 | +151.899 | +151.969 | <A/13-12 | MA0(?) | 2400
MARCHE | RIGID_FRAME | 423.9 | +151.740 | +151.810 | <A/13-12 | MA0(?) | 2400
MARCHE | RIGID_FRAME | 423.9 | +151.581 | +151.651 | <A/13-12 | MA0(?) | 2400
MARCHE | RIGID_FRAME | 423.9 | +151.422 | +151.492 | <A/13-12 | MA0(?) | 2400
MARCHE | RIGID_FRAME | 423.9 | +151.263 | +151.333 | <A/13-12 | MA0(?) | 2400
MARCHE | RIGID_FRAME | 423.9 | +151.104 | +151.174 | <A/12 | MA0(?) | 2400
MARCHE | RIGID_FRAME | 423.9 | +150.945 | +151.015 | <A/12 | MA0(?) | 2400
MARCHE | RIGID_FRAME | 423.9 | +150.786 | +150.856 | <A/12-11 | MA0(?) | 2400
MARCHE | RIGID_FRAME | 423.9 | +150.468 | +150.538 | <A/12-11 | MA0(?) | 2400
MARCHE | RIGID_FRAME | 423.9 | +150.309 | +150.379 | <A/12-11 | MA0(?) | 2400
MARCHE | RIGID_FRAME | 423.9 | +150.150 | +150.220 | <A/12-11 | MA0(?) | 2400
MARCHE | RIGID_FRAME | 423.9 | +149.991 | +150.061 | <A/12-11 | MA0(?) | 2400
MARCHE | RIGID_FRAME | 423.9 | +149.832 | +149.902 | <A/12-11 | MA0(?) | 2400
MARCHE | RIGID_FRAME | 423.9 | +149.673 | +149.743 | <A/12-11 | MA0(?) | 2400
MARCHE | RIGID_FRAME | 423.9 | +149.514 | +149.584 | <A/12-11 | MA0(?) | 2400
MARCHE | RIGID_FRAME | 423.9 | +150.627 | +150.697 | <A/12-11 | MA0(?) | 2400
MARCHE | RIGID_FRAME | 423.9 | +149.037 | +149.107 | <A/10-9 | MA0(?) | 2400
MARCHE | RIGID_FRAME | 423.9 | +148.878 | +148.948 | <A/10-9 | MA0(?) | 2400
MARCHE | RIGID_FRAME | 423.9 | +148.719 | +148.789 | <A/10-9 | MA0(?) | 2400
MARCHE | RIGID_FRAME | 423.9 | +148.560 | +148.630 | <A/10-9 | MA0(?) | 2400
MARCHE | RIGID_FRAME | 423.9 | +148.401 | +148.471 | <A/10-9 | MA0(?) | 2400
MARCHE | RIGID_FRAME | 423.9 | +148.242 | +148.312 | <A/10-9 | MA0(?) | 2400
MARCHE | RIGID_FRAME | 423.9 | +148.083 | +148.153 | <A/9 | MA0(?) | 2400
MARCHE | RIGID_FRAME | 423.9 | +149.196 | +149.266 | <A/10-9 | MA0(?) | 2400
MARCHE | RIGID_FRAME | 317.9 | +159.773 | +159.843 | <A/8-7 | MA0(?) | 1800
MARCHE | RIGID_FRAME | 317.9 | +159.615 | +159.685 | <A/7 | MA0(?) | 1800
MARCHE | RIGID_FRAME | 317.9 | +159.458 | +159.528 | <A/7 | MA0(?) | 1800
MARCHE | RIGID_FRAME | 317.9 | +159.300 | +159.370 | <A/7-6 | MA0(?) | 1800
MARCHE | RIGID_FRAME | 317.9 | +159.143 | +159.213 | <A/7-6 | MA0(?) | 1800
MARCHE | RIGID_FRAME | 317.9 | +158.985 | +159.055 | <A/7-6 | MA0(?) | 1800
MARCHE | RIGID_FRAME | 317.9 | +158.828 | +158.898 | <A/7-6 | MA0(?) | 1800
MARCHE | RIGID_FRAME | 317.9 | +158.670 | +158.740 | <A/7-6 | MA0(?) | 1800
MARCHE | RIGID_FRAME | 317.9 | +158.513 | +158.583 | <A/7-6 | MA0(?) | 1800
MARCHE | RIGID_FRAME | 317.9 | +158.355 | +158.425 | <A/7-6 | MA0(?) | 1800
MARCHE | RIGID_FRAME | 317.9 | +158.198 | +158.268 | <A/7-6 | MA0(?) | 1800
MARCHE | RIGID_FRAME | 317.9 | +158.040 | +158.110 | <A/7-6 | MA0(?) | 1800
MARCHE | RIGID_FRAME | 317.9 | +157.883 | +157.953 | <A/7-6 | MA0(?) | 1800
MARCHE | RIGID_FRAME | 317.9 | +157.725 | +157.795 | <A/7-6 | MA0(?) | 1800
MARCHE | RIGID_FRAME | 317.9 | +157.568 | +157.638 | <A/7-6 | MA0(?) | 1800
MARCHE | RIGID_FRAME | 317.9 | +157.410 | +157.480 | <A/6 | MA0(?) | 1800
MARCHE | RIGID_FRAME | 317.9 | +157.253 | +157.323 | <A/6 | MA0(?) | 1800
MARCHE | RIGID_FRAME | 317.9 | +157.095 | +157.165 | <A/6-5 | MA0(?) | 1800
MARCHE | RIGID_FRAME | 317.9 | +156.938 | +157.008 | <A/6-5 | MA0(?) | 1800
MARCHE | RIGID_FRAME | 317.9 | +156.780 | +156.850 | <A/6-5 | MA0(?) | 1800
CONSOLE | RIGID_FRAME | 32 | +153.270 | +153.370 | <A/12-11 | A0(?) | 100
CONSOLE | RIGID_FRAME | 32 | +153.270 | +153.370 | <A/10-9 | A0(?) | 100
CONSOLE | RIGID_FRAME | 32 | +153.270 | +153.370 | <A/9 | A0(?) | 100
CONSOLE | RIGID_FRAME | 32 | +153.270 | +153.370 | <A/9-8 | A0(?) | 100
MARCHE | RIGID_FRAME | 317.9 | +150.677 | +150.747 | <A/6-5 | MA0(?) | 1800
MARCHE | RIGID_FRAME | 317.9 | +150.524 | +150.594 | <A/6-5 | MA0(?) | 1800
MARCHE | RIGID_FRAME | 317.9 | +150.371 | +150.441 | <A/6-5 | MA0(?) | 1800
MARCHE | RIGID_FRAME | 317.9 | +150.218 | +150.288 | <A/6-5 | MA0(?) | 1800
MARCHE | RIGID_FRAME | 317.9 | +150.065 | +150.135 | <A/6 | MA0(?) | 1800
MARCHE | RIGID_FRAME | 317.9 | +149.912 | +149.982 | <A/6 | MA0(?) | 1800
MARCHE | RIGID_FRAME | 317.9 | +149.759 | +149.829 | <A/7-6 | MA0(?) | 1800
MARCHE | RIGID_FRAME | 317.9 | +149.606 | +149.676 | <A/7-6 | MA0(?) | 1800
MARCHE | RIGID_FRAME | 317.9 | +149.453 | +149.523 | <A/7-6 | MA0(?) | 1800
MARCHE | RIGID_FRAME | 317.9 | +149.300 | +149.370 | <A/7-6 | MA0(?) | 1800
MARCHE | RIGID_FRAME | 317.9 | +149.147 | +149.217 | <A/7-6 | MA0(?) | 1800
MARCHE | RIGID_FRAME | 317.9 | +148.994 | +149.064 | <A/7-6 | MA0(?) | 1800
MARCHE | RIGID_FRAME | 317.9 | +148.841 | +148.911 | <A/7-6 | MA0(?) | 1800
MARCHE | RIGID_FRAME | 317.9 | +148.688 | +148.758 | <A/7-6 | MA0(?) | 1800
MARCHE | RIGID_FRAME | 317.9 | +148.535 | +148.605 | <A/7-6 | MA0(?) | 1800
MARCHE | RIGID_FRAME | 317.9 | +148.382 | +148.452 | <A/7-6 | MA0(?) | 1800
MARCHE | RIGID_FRAME | 317.9 | +148.229 | +148.299 | <A/7-6 | MA0(?) | 1800
MARCHE | RIGID_FRAME | 317.9 | +148.076 | +148.146 | <A/7 | MA0(?) | 1800
SOLIVE | RIGID_FRAME | 77.2 | +150.650 | +150.870 | A/6-5 | A0(?) | 80
DALLE | REINFORCEMENT_UNIT | 92887.1 | +150.700 | +150.900 | A-G/8-5 | Da0(?) | 200 | Tekla Assemblages - Cast unit type: Coulé sur site; Poids ferraillage Elément béton: 0 kg
LIMON | RIGID_FRAME | 282.6 | +150.650 | +153.370 | <A/8-6 | L0(?) | 80
MARCHE | RIGID_FRAME | 317.9 | +153.174 | +153.244 | <A/8-7 | MA0(?) | 1800
MARCHE | RIGID_FRAME | 317.9 | +153.017 | +153.087 | <A/7 | MA0(?) | 1800
MARCHE | RIGID_FRAME | 317.9 | +152.861 | +152.931 | <A/7 | MA0(?) | 1800
MARCHE | RIGID_FRAME | 317.9 | +152.704 | +152.774 | <A/7-6 | MA0(?) | 1800
MARCHE | RIGID_FRAME | 317.9 | +152.548 | +152.618 | <A/7-6 | MA0(?) | 1800
MARCHE | RIGID_FRAME | 317.9 | +152.391 | +152.461 | <A/7-6 | MA0(?) | 1800
MARCHE | RIGID_FRAME | 317.9 | +152.235 | +152.305 | <A/7-6 | MA0(?) | 1800
MARCHE | RIGID_FRAME | 317.9 | +152.078 | +152.148 | <A/7-6 | MA0(?) | 1800
MARCHE | RIGID_FRAME | 317.9 | +151.922 | +151.992 | <A/7-6 | MA0(?) | 1800
MARCHE | RIGID_FRAME | 317.9 | +151.765 | +151.835 | <A/7-6 | MA0(?) | 1800
MARCHE | RIGID_FRAME | 317.9 | +151.609 | +151.679 | <A/7-6 | MA0(?) | 1800
MARCHE | RIGID_FRAME | 317.9 | +151.452 | +151.522 | <A/7-6 | MA0(?) | 1800
MARCHE | RIGID_FRAME | 317.9 | +151.296 | +151.366 | <A/7-6 | MA0(?) | 1800
MARCHE | RIGID_FRAME | 317.9 | +151.139 | +151.209 | <A/7-6 | MA0(?) | 1800
MARCHE | RIGID_FRAME | 317.9 | +150.983 | +151.053 | <A/6 | MA0(?) | 1800
SOLIVE | RIGID_FRAME | 77.2 | +153.150 | +153.370 | <A/12-9 | A0(?) | 80
SOLIVE | RIGID_FRAME | 77.2 | +153.150 | +153.370 | <A/10-9 | A0(?) | 80
SOLIVE | RIGID_FRAME | 71.7 | +153.150 | +153.370 | <A/9-8 | A0(?) | 80
SOLIVE | RIGID_FRAME | 63.5 | +153.150 | +153.370 | <A/9-8 | A0(?) | 80
GOUSSET | RIGID_FRAME | 6220 | +159.970 | +160.000 | <A/12-7 | G0(?) | 30
SOLIVE | RIGID_FRAME | 33.9 | +159.830 | +159.970 | <A/12-9 | A0(?) | 73
SOLIVE | RIGID_FRAME | 42.1 | +159.830 | +159.970 | <A/12-9 | A0(?) | 60
SOLIVE | RIGID_FRAME | 77.2 | +159.750 | +159.970 | <A/12-9 | A0(?) | 80
CONSOLE | RIGID_FRAME | 73.5 | +159.750 | +159.970 | <A/12-11 | A0(?) | 110
CONSOLE | RIGID_FRAME | 71.7 | +159.750 | +159.970 | <A/10-9 | A0(?) | 110
SOLIVE | RIGID_FRAME | 33.9 | +159.830 | +159.970 | <A/10-9 | A0(?) | 73
SOLIVE | RIGID_FRAME | 42.1 | +159.830 | +159.970 | <A/10-9 | A0(?) | 60
SOLIVE | RIGID_FRAME | 77.2 | +159.750 | +159.970 | <A/10-9 | A0(?) | 80
CONSOLE | RIGID_FRAME | 71.7 | +159.750 | +159.970 | <A/9 | A0(?) | 110
SOLIVE | RIGID_FRAME | 31.5 | +159.830 | +159.970 | <A/9-8 | A0(?) | 73
SOLIVE | RIGID_FRAME | 39.2 | +159.830 | +159.970 | <A/9-8 | A0(?) | 60
SOLIVE | RIGID_FRAME | 71.7 | +159.750 | +159.970 | <A/9-8 | A0(?) | 80
STAB | RIGID_FRAME | 71.7 | +159.750 | +159.970 | <A/9-8 | A0(?) | 110
SOLIVE | RIGID_FRAME | 28.8 | +159.830 | +159.970 | <A/9-7 | A0(?) | 73
SOLIVE | RIGID_FRAME | 34.6 | +159.830 | +159.970 | <A/9-8 | A0(?) | 60
SOLIVE | RIGID_FRAME | 63.5 | +159.750 | +159.970 | <A/9-8 | A0(?) | 80
SOLIVE | RIGID_FRAME | 76.7 | +159.750 | +159.970 | <A/8-7 | A0(?) | 80
2 x STAB | RIGID_FRAME | 12.7 | +159.780 | +159.830 | <A/8-7 | A0(?) | 50
SOLIVE | RIGID_FRAME | 33.9 | +159.830 | +159.970 | <A/8-7 | A0(?) | 73
SOLIVE | RIGID_FRAME | 79.3 | +159.750 | +159.970 | <A/8-7 | A0(?) | 80
POTEAU | RIGID_FRAME | 142.4 | +148.000 | +154.400 | <A/14-13 | P0(?) | 150
POTEAU | RIGID_FRAME | 142.4 | +148.000 | +154.400 | <A/13-12 | P0(?) | 150
POTEAU | RIGID_FRAME | 142.4 | +148.000 | +154.400 | <A/12 | P0(?) | 150
POTEAU | RIGID_FRAME | 289.3 | +148.000 | +161.000 | <A/12-11 | P0(?) | 150
POTEAU | RIGID_FRAME | 289.3 | +148.000 | +161.000 | <A/10-9 | P0(?) | 150
POTEAU | RIGID_FRAME | 289.3 | +148.000 | +161.000 | <A/9 | P0(?) | 150
POTEAU | RIGID_FRAME | 289.3 | +148.000 | +161.000 | <A/9-8 | P0(?) | 150
2 x STAB | RIGID_FRAME | 12.7 | +150.680 | +150.730 | <A/6-5 | A0(?) | 50
3 x SOLIVE | RIGID_FRAME | 33.9 | +150.730 | +150.870 | <A/6-5 | A0(?) | 73
2 x SOLIVE | RIGID_FRAME | 79.3 | +150.650 | +150.870 | <A/6-5 | A0(?) | 80
2 x STAB | RIGID_FRAME | 12.7 | +156.480 | +156.530 | <A/8-7 | A0(?) | 50
3 x SOLIVE | RIGID_FRAME | 33.9 | +156.530 | +156.670 | <A/8-7 | A0(?) | 73
2 x STAB | RIGID_FRAME | 12.7 | +153.180 | +153.230 | <A/8-7 | A0(?) | 50
3 x SOLIVE | RIGID_FRAME | 33.9 | +153.230 | +153.370 | <A/8-7 | A0(?) | 73
2 x STAB | RIGID_FRAME | 12.7 | +153.180 | +153.230 | <A/6-5 | A0(?) | 50
3 x SOLIVE | RIGID_FRAME | 33.9 | +153.230 | +153.370 | <A/6-5 | A0(?) | 73
2 x STAB | RIGID_FRAME | 13.1 | +150.680 | +150.730 | <A/6-5 | A0(?) | 50
SOLIVE | RIGID_FRAME | 73 | +150.650 | +150.870 | <A/5 | A0(?) | 80
SOLIVE | RIGID_FRAME | 63.7 | +150.650 | +150.870 | <A/5 | A0(?) | 80
2 x STAB | RIGID_FRAME | 13.1 | +156.480 | +156.530 | <A/8-7 | A0(?) | 50
2 x STAB | RIGID_FRAME | 14.3 | +156.480 | +156.530 | <A/8-6 | A0(?) | 50
2 x STAB | RIGID_FRAME | 14.3 | +156.480 | +156.530 | <A/7-5 | A0(?) | 50
SOLIVE | RIGID_FRAME | 39.9 | +156.530 | +156.670 | <A/8-6 | A0(?) | 73
SOLIVE | RIGID_FRAME | 54.9 | +156.450 | +156.670 | <A/8-7 | A0(?) | 110
SOLIVE | RIGID_FRAME | 53 | +156.450 | +156.670 | <A/7-6 | A0(?) | 110
SOLIVE | RIGID_FRAME | 79.3 | +156.450 | +156.670 | <A/8-7 | A0(?) | 80
SOLIVE | RIGID_FRAME | 91 | +156.450 | +156.670 | <A/8-6 | A0(?) | 80
SOLIVE | RIGID_FRAME | 75.7 | +156.450 | +156.670 | <A/8-7 | A0(?) | 80
SOLIVE | RIGID_FRAME | 63.7 | +156.450 | +156.670 | <A/8-7 | A0(?) | 80
2 x STAB | RIGID_FRAME | 13.1 | +153.180 | +153.230 | <A/6-5 | A0(?) | 50
2 x STAB | RIGID_FRAME | 13.1 | +153.180 | +153.230 | <A/8-7 | A0(?) | 50
2 x STAB | RIGID_FRAME | 14.3 | +153.180 | +153.230 | <A/8-6 | A0(?) | 50
2 x SOLIVE | RIGID_FRAME | 14.3 | +153.180 | +153.230 | <A/7-5 | A0(?) | 50
SOLIVE | RIGID_FRAME | 39.9 | +153.230 | +153.370 | <A/8-6 | A0(?) | 73
SOLIVE | RIGID_FRAME | 39.9 | +153.230 | +153.370 | <A/7-5 | A0(?) | 73
SOLIVE | RIGID_FRAME | 54.9 | +153.150 | +153.370 | <A/8-7 | A0(?) | 110
SOLIVE | RIGID_FRAME | 53 | +153.150 | +153.370 | <A/7-6 | A0(?) | 110
SOLIVE | RIGID_FRAME | 54.9 | +153.150 | +153.370 | <A/6-5 | A0(?) | 110
SOLIVE | RIGID_FRAME | 182 | +153.150 | +153.370 | <A/8-5 | A0(?) | 80
SOLIVE | RIGID_FRAME | 79.3 | +153.150 | +153.370 | <A/8-7 | A0(?) | 80
SOLIVE | RIGID_FRAME | 91 | +153.150 | +153.370 | <A/8-6 | A0(?) | 80
SOLIVE | RIGID_FRAME | 91 | +153.150 | +153.370 | <A/7-5 | A0(?) | 80
SOLIVE | RIGID_FRAME | 79.3 | +153.150 | +153.370 | <A/6-5 | A0(?) | 80
SOLIVE | RIGID_FRAME | 75.7 | +153.150 | +153.370 | <A/8-7 | A0(?) | 80
SOLIVE | RIGID_FRAME | 63.7 | +153.150 | +153.370 | <A/8-7 | A0(?) | 80
STAB | RIGID_FRAME | 76.7 | +153.150 | +153.370 | <A/5 | A0(?) | 80
STAB | RIGID_FRAME | 63.7 | +153.150 | +153.370 | <A/5 | A0(?) | 80
POTEAU | RIGID_FRAME | 266.4 | +148.000 | +159.970 | <A/8-7 | P0(?) | 150
2 x POTEAU | RIGID_FRAME | 289.3 | +148.000 | +161.000 | <A/8-7 | P0(?) | 150
2 x POTEAU | RIGID_FRAME | 215.9 | +148.000 | +157.700 | <A/8-7 | P0(?) | 150
POTEAU | RIGID_FRAME | 215.9 | +148.000 | +157.700 | <A/7-6 | P0(?) | 150
POUTRE |  | 419.9 | +164.600 | +164.960 | G-H/10 | Po0(?) | 160
POUTRE |  | 40.6 | +163.200 | +164.960 | G-H/10 | Po0(?) | 160
POUTRE |  | 124.2 | +163.200 | +164.960 | H/10 | Po0(?) | 280
POUTRE |  | 236.4 | +159.850 | +163.200 | H/10 | Po0(?) | 280
POUTRE |  | 105.1 | +163.470 | +164.960 | G/10 | Po0(?) | 280
POUTRE |  | 1633 | +162.400 | +163.200 | G-H/10 | Po0(?) | 280
POUTRE |  | 36 | +162.833 | +163.070 | H-I/10 | Po0(?) | 100
POUTRE |  | 201.4 | +162.630 | +163.070 | H-I/10 | Po0(?) | 240
POUTRE |  | 116.1 | +162.857 | +163.347 | I-J/10 | Po0(?) | 100
POUTRE |  | 626.7 | +162.657 | +163.346 | I-J/10 | Po0(?) | 240
POUTRE |  | 215.9 | +159.900 | +163.470 | J/10 | Po0(?) | 240
POUTRE |  | 170.4 | +159.900 | +163.186 | I-J/10 | Po0(?) | 240
POUTRE |  | 223.3 | +159.900 | +163.130 | I/10 | Po0(?) | 240
2 x SOLIVE | RIGID_FRAME | 69.6 | +162.500 | +162.680 | I-J/11 | A0(?) | 100
2 x SOLIVE | RIGID_FRAME | 69.6 | +162.500 | +162.680 | I-J/12-11 | A0(?) | 100
CONSOLE | RIGID_FRAME | 25.3 | +162.500 | +162.680 | J/12-11 | A0(?) | 100
CONSOLE | RIGID_FRAME | 25.3 | +162.500 | +162.680 | I-J/12-11 | A0(?) | 100
SOLIVE | RIGID_FRAME | 48.1 | +162.500 | +162.680 | H-I/11 | A0(?) | 100
SOLIVE | RIGID_FRAME | 48.1 | +162.500 | +162.680 | H-I/12-11 | A0(?) | 100
CONSOLE | RIGID_FRAME | 25.3 | +162.500 | +162.680 | I/12-11 | A0(?) | 100
SOLIVE | RIGID_FRAME | 69.8 | +162.500 | +162.680 | G-H/11 | A0(?) | 100
SOLIVE | RIGID_FRAME | 69.8 | +162.500 | +162.680 | G-H/12-11 | A0(?) | 100
CONSOLE | RIGID_FRAME | 25.3 | +162.500 | +162.680 | H/12-11 | A0(?) | 100
SOLIVE | RIGID_FRAME | 81.6 | +162.500 | +162.680 | F-H/11 | A0(?) | 100
SOLIVE | RIGID_FRAME | 81.6 | +162.500 | +162.680 | F-H/12-11 | A0(?) | 100
CONSOLE | RIGID_FRAME | 27.3 | +162.500 | +162.680 | G-H/12-10 | A0(?) | 100
2 x CVT | RIGID_FRAME | 7.1 | +162.570 | +162.610 | C-D/12-11 | A0(?) | 40
2 x CVT | RIGID_FRAME | 7.1 | +156.560 | +156.600 | C-D/12-11 | A0(?) | 40
SOLIVE | RIGID_FRAME | 55.5 | +162.500 | +162.680 | F-G/11 | A0(?) | 100
SOLIVE | RIGID_FRAME | 64.9 | +162.500 | +162.680 | E-F/11 | A0(?) | 100
SOLIVE | RIGID_FRAME | 64.9 | +162.500 | +162.680 | D-E/11 | A0(?) | 100
SOLIVE | RIGID_FRAME | 64.9 | +162.500 | +162.680 | C-D/11 | A0(?) | 100
SOLIVE | RIGID_FRAME | 64.9 | +162.500 | +162.680 | B-C/11 | A0(?) | 100
SOLIVE | RIGID_FRAME | 64.9 | +162.500 | +162.680 | A-B/11 | A0(?) | 100
SOLIVE | RIGID_FRAME | 55.5 | +162.500 | +162.680 | F-G/12-11 | A0(?) | 100
SOLIVE | RIGID_FRAME | 64.9 | +162.500 | +162.680 | E-F/12-11 | A0(?) | 100
SOLIVE | RIGID_FRAME | 64.9 | +162.500 | +162.680 | D-E/12-11 | A0(?) | 100
SOLIVE | RIGID_FRAME | 64.9 | +162.500 | +162.680 | C-D/12-11 | A0(?) | 100
SOLIVE | RIGID_FRAME | 64.9 | +162.500 | +162.680 | B-C/12-11 | A0(?) | 100
SOLIVE | RIGID_FRAME | 64.9 | +162.500 | +162.680 | A-B/12-11 | A0(?) | 100
SOLIVE | RIGID_FRAME | 55.5 | +156.490 | +156.670 | F-G/11 | A0(?) | 100
SOLIVE | RIGID_FRAME | 64.9 | +156.490 | +156.670 | E-F/11 | A0(?) | 100
SOLIVE | RIGID_FRAME | 64.9 | +156.490 | +156.670 | D-E/11 | A0(?) | 100
SOLIVE | RIGID_FRAME | 64.9 | +156.490 | +156.670 | C-D/11 | A0(?) | 100
SOLIVE | RIGID_FRAME | 64.9 | +156.490 | +156.670 | B-C/11 | A0(?) | 100
SOLIVE | RIGID_FRAME | 64.9 | +156.490 | +156.670 | A-B/11 | A0(?) | 100
SOLIVE | RIGID_FRAME | 55.5 | +156.490 | +156.670 | F-G/12-11 | A0(?) | 100
SOLIVE | RIGID_FRAME | 64.9 | +156.490 | +156.670 | E-F/12-11 | A0(?) | 100
SOLIVE | RIGID_FRAME | 64.9 | +156.490 | +156.670 | D-E/12-11 | A0(?) | 100
SOLIVE | RIGID_FRAME | 64.9 | +156.490 | +156.670 | C-D/12-11 | A0(?) | 100
SOLIVE | RIGID_FRAME | 64.9 | +156.490 | +156.670 | B-C/12-11 | A0(?) | 100
SOLIVE | RIGID_FRAME | 64.9 | +156.490 | +156.670 | A-B/12-11 | A0(?) | 100
CONSOLE | RIGID_FRAME | 165.7 | +156.490 | +162.680 | F-G/12-11 | A0(?) | 100
CONSOLE | RIGID_FRAME | 165.7 | +156.490 | +162.680 | F/12-11 | A0(?) | 100
CONSOLE | RIGID_FRAME | 165.7 | +156.490 | +162.680 | E/12-11 | A0(?) | 100
CONSOLE | RIGID_FRAME | 165.7 | +156.490 | +162.680 | D/12-11 | A0(?) | 100
CONSOLE | RIGID_FRAME | 165.7 | +156.490 | +162.680 | B/12-11 | A0(?) | 100
CONSOLE | RIGID_FRAME | 165.7 | +156.490 | +162.680 | A/12-11 | A0(?) | 100
SOLIVE | RIGID_FRAME | 73 | +159.790 | +159.970 | F-G/11 | A0(?) | 70
SOLIVE | RIGID_FRAME | 85.4 | +159.790 | +159.970 | E-F/11 | A0(?) | 70
SOLIVE | RIGID_FRAME | 85.4 | +159.790 | +159.970 | D-E/11 | A0(?) | 70
SOLIVE | RIGID_FRAME | 85.4 | +159.790 | +159.970 | C-D/11 | A0(?) | 70
SOLIVE | RIGID_FRAME | 85.4 | +159.790 | +159.970 | B-C/11 | A0(?) | 70
SOLIVE | RIGID_FRAME | 85.4 | +159.790 | +159.970 | A-B/11 | A0(?) | 70
SOLIVE | RIGID_FRAME | 73 | +159.790 | +159.970 | F-G/12-11 | A0(?) | 70
SOLIVE | RIGID_FRAME | 85.4 | +159.790 | +159.970 | E-F/12-11 | A0(?) | 70
SOLIVE | RIGID_FRAME | 85.4 | +159.790 | +159.970 | D-E/12-11 | A0(?) | 70
2 x POUTRE | RIGID_FRAME | 7.1 | +159.860 | +159.900 | C-D/12-11 | A0(?) | 40
GOUSSET | RIGID_FRAME | 5398.7 | +159.970 | +160.000 | A-G/12-11 | G0(?) | 30
POUTRE | RIGID_FRAME | 85.4 | +159.790 | +159.970 | A-B/12-11 | A0(?) | 70
POUTRE |  | 226.7 | +159.850 | +163.130 | A/8-7 | Po0(?) | 320
POUTRE |  | 232.2 | +159.850 | +163.210 | A/8-7 | Po0(?) | 320
2 x POUTRE |  | 228.1 | +156.550 | +159.850 | A/8-7 | Po0(?) | 320
2 x POUTRE |  | 217.7 | +153.400 | +156.550 | A/8-7 | Po0(?) | 320
POUTRE |  | 28.8 | +156.300 | +156.460 | A/8-7 | Po0(?) | 100
POUTRE |  | 118.1 | +156.320 | +156.480 | A/8-5 | Po0(?) | 100
POUTRE |  | 1964.7 | +156.000 | +156.480 | A/10-5 | Po0(?) | 240
POUTRE |  | 118.1 | +156.320 | +156.480 | A/10-7 | Po0(?) | 100
POUTRE |  | 276.1 | +152.846 | +156.334 | A/6-5 | Po0(?) | 240
POUTRE |  | 276.1 | +152.846 | +156.334 | A/8-6 | Po0(?) | 240
POUTRE |  | 276.1 | +156.146 | +159.634 | A/6-5 | Po0(?) | 240
POUTRE |  | 276.1 | +156.146 | +159.634 | A/8-6 | Po0(?) | 240
POUTRE |  | 281.5 | +159.448 | +163.098 | A/6-5 | Po0(?) | 240
POUTRE |  | 281.5 | +159.448 | +163.098 | A/8-6 | Po0(?) | 240
POUTRE |  | 276.1 | +152.846 | +156.334 | A/9-7 | Po0(?) | 240
POUTRE |  | 276.1 | +152.846 | +156.334 | A/10-9 | Po0(?) | 240
POUTRE |  | 276.1 | +156.146 | +159.634 | A/9-7 | Po0(?) | 240
POUTRE |  | 276.1 | +156.146 | +159.634 | A/10-9 | Po0(?) | 240
POUTRE |  | 282.6 | +159.448 | +163.134 | A/9-7 | Po0(?) | 240
POUTRE |  | 282.6 | +159.448 | +163.134 | A/10-9 | Po0(?) | 240
POUTRE |  | 170.4 | +162.640 | +163.068 | A/8-7 | Po0(?) | 240
POUTRE |  | 28.8 | +162.843 | +163.065 | A/8-7 | Po0(?) | 100
POUTRE |  | 28.8 | +159.600 | +159.760 | A/8-7 | Po0(?) | 100
POUTRE |  | 118.1 | +159.620 | +159.780 | A/8-5 | Po0(?) | 100
POUTRE |  | 1964.7 | +159.300 | +159.780 | A/10-5 | Po0(?) | 240
POUTRE |  | 118.1 | +159.620 | +159.780 | A/10-7 | Po0(?) | 100
POUTRE |  | 637.6 | +162.661 | +163.345 | A/8-5 | Po0(?) | 240
POUTRE |  | 118.1 | +162.861 | +163.345 | A/8-5 | Po0(?) | 100
POUTRE |  | 637.6 | +162.734 | +163.347 | A/10-7 | Po0(?) | 240
POUTRE |  | 118.1 | +162.933 | +163.347 | A/10-7 | Po0(?) | 100
POUTRE |  | 239.8 | +162.950 | +163.470 | A-B/10 | Po0(?) | 140
POUTRE |  | 92.2 | +162.950 | +163.150 | A-B/10 | Po0(?) | 140
POUTRE |  | 258.2 | +159.290 | +159.850 | A-B/10 | Po0(?) | 140
POUTRE |  | 92.2 | +159.290 | +159.490 | A-B/10 | Po0(?) | 140
POUTRE |  | 239.8 | +162.950 | +163.470 | B-C/10 | Po0(?) | 140
POUTRE |  | 92.2 | +162.950 | +163.150 | B-C/10 | Po0(?) | 140
POUTRE |  | 258.2 | +159.290 | +159.850 | B-C/10 | Po0(?) | 140
POUTRE |  | 92.2 | +159.290 | +159.490 | B-C/10 | Po0(?) | 140
POUTRE |  | 239.8 | +162.950 | +163.470 | C-D/10 | Po0(?) | 140
POUTRE |  | 92.2 | +162.950 | +163.150 | C-D/10 | Po0(?) | 140
POUTRE |  | 258.2 | +159.290 | +159.850 | C-D/10 | Po0(?) | 140
POUTRE |  | 92.2 | +159.290 | +159.490 | C-D/10 | Po0(?) | 140
POUTRE |  | 239.8 | +162.950 | +163.470 | D-E/10 | Po0(?) | 140
POUTRE |  | 92.2 | +162.950 | +163.150 | D-E/10 | Po0(?) | 140
POUTRE |  | 258.2 | +159.290 | +159.850 | D-E/10 | Po0(?) | 140
POUTRE |  | 92.2 | +159.290 | +159.490 | D-E/10 | Po0(?) | 140
POUTRE |  | 239.8 | +162.950 | +163.470 | E-F/10 | Po0(?) | 140
POUTRE |  | 92.2 | +162.950 | +163.150 | E-F/10 | Po0(?) | 140
POUTRE |  | 247.7 | +162.950 | +163.470 | F-G/10 | Po0(?) | 140
POUTRE |  | 95.3 | +162.950 | +163.150 | F-G/10 | Po0(?) | 140
POUTRE |  | 258.2 | +159.290 | +159.850 | E-F/10 | Po0(?) | 140
POUTRE |  | 92.2 | +159.290 | +159.490 | E-F/10 | Po0(?) | 140
POUTRE |  | 266.7 | +159.290 | +159.850 | F-G/10 | Po0(?) | 140
POUTRE |  | 95.3 | +159.290 | +159.490 | F-G/10 | Po0(?) | 140
POUTRE |  | 258.2 | +155.990 | +156.550 | A-B/10 | Po0(?) | 140
POUTRE |  | 92.2 | +155.990 | +156.190 | A-B/10 | Po0(?) | 140
POUTRE |  | 258.2 | +155.990 | +156.550 | B-C/10 | Po0(?) | 140
POUTRE |  | 92.2 | +155.990 | +156.190 | B-C/10 | Po0(?) | 140
POUTRE |  | 258.2 | +155.990 | +156.550 | C-D/10 | Po0(?) | 140
POUTRE |  | 92.2 | +155.990 | +156.190 | C-D/10 | Po0(?) | 140
POUTRE |  | 258.2 | +155.990 | +156.550 | D-E/10 | Po0(?) | 140
POUTRE |  | 92.2 | +155.990 | +156.190 | D-E/10 | Po0(?) | 140
POUTRE |  | 258.2 | +155.990 | +156.550 | E-F/10 | Po0(?) | 140
POUTRE |  | 92.2 | +155.990 | +156.190 | E-F/10 | Po0(?) | 140
POUTRE |  | 266.7 | +155.990 | +156.550 | F-G/10 | Po0(?) | 140
POUTRE |  | 95.3 | +155.990 | +156.190 | F-G/10 | Po0(?) | 140
POUTRE |  | 255.4 | +159.850 | +163.470 | G/10 | Po0(?) | 280
POUTRE |  | 232.8 | +156.550 | +159.850 | G/10 | Po0(?) | 280
POUTRE |  | 222.3 | +153.400 | +156.550 | G/10 | Po0(?) | 280
POUTRE |  | 218.9 | +159.850 | +163.470 | A/10 | Po0(?) | 280
POUTRE |  | 218.9 | +159.850 | +163.470 | B/10 | Po0(?) | 280
POUTRE |  | 218.9 | +159.850 | +163.470 | C/10 | Po0(?) | 280
POUTRE |  | 218.9 | +159.850 | +163.470 | D/10 | Po0(?) | 280
POUTRE |  | 218.9 | +159.850 | +163.470 | E/10 | Po0(?) | 280
POUTRE |  | 218.9 | +159.850 | +163.470 | F/10 | Po0(?) | 280
POUTRE |  | 199.6 | +156.550 | +159.850 | A/10 | Po0(?) | 280
POUTRE |  | 199.6 | +156.550 | +159.850 | B/10 | Po0(?) | 280
POUTRE |  | 199.6 | +156.550 | +159.850 | C/10 | Po0(?) | 280
POUTRE |  | 199.6 | +156.550 | +159.850 | D/10 | Po0(?) | 280
POUTRE |  | 199.6 | +156.550 | +159.850 | E/10 | Po0(?) | 280
POUTRE |  | 199.6 | +156.550 | +159.850 | F/10 | Po0(?) | 280
POUTRE |  | 190.5 | +153.400 | +156.550 | A/10 | Po0(?) | 280
POUTRE |  | 190.5 | +153.400 | +156.550 | B/10 | Po0(?) | 280
POUTRE |  | 190.5 | +153.400 | +156.550 | C/10 | Po0(?) | 280
POUTRE |  | 190.5 | +153.400 | +156.550 | D/10 | Po0(?) | 280
POUTRE |  | 190.5 | +153.400 | +156.550 | E/10 | Po0(?) | 280
POUTRE |  | 190.5 | +153.400 | +156.550 | F/10 | Po0(?) | 280
DALLE |  | 95931.8 | +159.780 | +159.900 | A-J/10-1 | Da0(?) | 120
DALLE |  | 95931.8 | +156.480 | +156.600 | A-J/10-1 | Da0(?) | 120
DALLE | REINFORCEMENT_UNIT | 85339.4 | +151.100 | +151.300 | A-G/10-7 | Da0(?) | 200 | Tekla Assemblages - Cast unit type: Coulé sur site; Poids ferraillage Elément béton: 0 kg
DALLE | REINFORCEMENT_UNIT | 20288.9 | +149.900 | +150.100 | G-H/4-1 | Da0(?) | 200 | Tekla Assemblages - Cast unit type: Coulé sur site; Poids ferraillage Elément béton: 0 kg
DALLE | REINFORCEMENT_UNIT | 140543 | +147.770 | +148.000 | G-J/7-3 | Da0(?) | 230 | Tekla Assemblages - Cast unit type: Coulé sur site; Poids ferraillage Elément béton: 0 kg
DALLE | REINFORCEMENT_UNIT | 462362 | +153.200 | +153.400 | A-J/10-1 | Da0(?) | 200 | Tekla Assemblages - Cast unit type: Coulé sur site; Poids ferraillage Elément béton: 0 kg
DALLE | REINFORCEMENT_UNIT | 130680 | +147.730 | +147.930 | A-G/10-5 | Da0(?) | 200 | Tekla Assemblages - Cast unit type: Coulé sur site; Poids ferraillage Elément béton: 0 kg
DALLE | REINFORCEMENT_UNIT | 217312 | +147.800 | +148.000 | A-H/<15-11 | Da0(?) | 200 | Tekla Assemblages - Cast unit type: Coulé sur site; Poids ferraillage Elément béton: 0 kg
DALLE | REINFORCEMENT_UNIT | 30176.3 | +147.660 | +147.860 | A-B/10-5 | Da0(?) | 200 | Tekla Assemblages - Cast unit type: Coulé sur site; Poids ferraillage Elément béton: 0 kg
DALLE | REINFORCEMENT_UNIT | 22627.7 | +147.400 | +147.600 | G-H/4-1 | Da0(?) | 200 | Tekla Assemblages - Cast unit type: Coulé sur site; Poids ferraillage Elément béton: 0 kg
PANNEAU |  | 1847.8 | +156.700 | +161.000 | G/<15-11 | PA0(?) | 360
PANNEAU |  | 2852.8 | +160.000 | +164.300 | A-J/11 | PA0(?) | 360
PANNEAU |  | 1275.5 | +156.700 | +160.000 | A-G/11 | PA0(?) | 360
PANNEAU |  | 1340.1 | +153.291 | +156.700 | A-G/11 | PA0(?) | 360
PANNEAU |  | 2073.4 | +160.000 | +164.300 | <A/11-5 | PA0(?) | 360
PANNEAU |  | 1561.9 | +156.700 | +160.000 | <A/11-5 | PA0(?) | 360
PANNEAU |  | 2191.5 | +152.100 | +156.700 | <A/11-5 | PA0(?) | 360
PANNEAU |  | 2282.8 | +160.000 | +164.300 | A-G/5 | PA0(?) | 360
PANNEAU |  | 1699.2 | +156.700 | +160.000 | A-G/5 | PA0(?) | 360
PANNEAU |  | 2457.9 | +152.100 | +156.700 | A-G/5 | PA0(?) | 360
PANNEAU |  | 1405.1 | +160.000 | +164.300 | G/5-1 | PA0(?) | 360
PANNEAU |  | 937.1 | +156.700 | +160.000 | G/5-1 | PA0(?) | 360
PANNEAU |  | 1440.3 | +152.100 | +156.700 | G/5-1 | PA0(?) | 360
PANNEAU |  | 3523 | +160.000 | +164.300 | J/10-1 | PA0(?) | 360
PANNEAU |  | 2132.4 | +156.700 | +160.000 | J/10-1 | PA0(?) | 360
PANNEAU |  | 2976.9 | +152.100 | +156.700 | J/9-1 | PA0(?) | 360
PANNEAU |  | 2091.4 | +160.000 | +164.300 | G-J/1> | PA0(?) | 360
PANNEAU |  | 1569.9 | +156.700 | +160.000 | G-J/1> | PA0(?) | 360
PANNEAU |  | 2247.9 | +152.100 | +156.700 | G-J/1> | PA0(?) | 360
PANNEAU | REINFORCEMENT_UNIT | 36358.4 | +147.760 | +153.200 | H-J/4-3 | PA0(?) | 10659.8 | Tekla Assemblages - Cast unit type: Coulé sur site; Poids ferraillage Elément béton: 0 kg
PANNEAU | REINFORCEMENT_UNIT | 89708 | +147.793 | +153.200 | G-J/4-3 | PA0(?) | 350 | Tekla Assemblages - Cast unit type: Coulé sur site; Poids ferraillage Elément béton: 0 kg
DALLE | REINFORCEMENT_UNIT | 119321 | +152.750 | +153.000 | A-E/<15-11 | Da0(?) | 250 | Tekla Assemblages - Cast unit type: Coulé sur site; Poids ferraillage Elément béton: 0 kg
PANNEAU | REINFORCEMENT_UNIT | 56028 | +148.000 | +153.400 | A-E/<15-11 | PA0(?) | 14018.6 | Tekla Assemblages - Cast unit type: Coulé sur site; Poids ferraillage Elément béton: 0 kg
PANNEAU | REINFORCEMENT_UNIT | 100885 | +147.860 | +153.200 | A-G/10-5 | PA0(?) | 23520 | Tekla Assemblages - Cast unit type: Coulé sur site; Poids ferraillage Elément béton: 0 kg
PANNEAU | REINFORCEMENT_UNIT | 35804.2 | +147.600 | +153.200 | G/5-1 | PA0(?) | 200 | Tekla Assemblages - Cast unit type: Coulé sur site; Poids ferraillage Elément béton: 0 kg
PANNEAU | REINFORCEMENT_UNIT | 36957 | +147.600 | +153.200 | G-H/4-1 | PA0(?) | 10031.9 | Tekla Assemblages - Cast unit type: Coulé sur site; Poids ferraillage Elément béton: 0 kg
DALLE | REINFORCEMENT_UNIT | 34759 | +147.800 | +148.000 | <A-B/15-11 | Da0(?) | 200 | Tekla Assemblages - Cast unit type: Coulé sur site; Poids ferraillage Elément béton: 0 kg
DALLE | REINFORCEMENT_UNIT | 46800 | +147.800 | +148.000 | <A/10-5 | Da0(?) | 200 | Tekla Assemblages - Cast unit type: Coulé sur site; Poids ferraillage Elément béton: 0 kg
DALLE | REINFORCEMENT_UNIT | 379287 | +146.988 | +147.700 | <A-G/5-1> | Da0(?) | 300 | Tekla Assemblages - Cast unit type: Coulé sur site; Poids ferraillage Elément béton: 0 kg
DALLE | REINFORCEMENT_UNIT | 167735 | +147.249 | +147.800 | G-J>/4-1> | Da0(?) | 250 | Tekla Assemblages - Cast unit type: Coulé sur site; Poids ferraillage Elément béton: 0 kg
POTEAU | REINFORCEMENT_UNIT | 2422.5 | +147.592 | +153.200 | H/1 | Pt0(?) | 400 | Tekla Assemblages - Cast unit type: Coulé sur site; Poids ferraillage Elément béton: 0 kg
POTEAU | REINFORCEMENT_UNIT | 2422.5 | +147.592 | +153.200 | I/1 | Pt0(?) | 400 | Tekla Assemblages - Cast unit type: Coulé sur site; Poids ferraillage Elément béton: 0 kg
POTEAU | REINFORCEMENT_UNIT | 2422.5 | +147.592 | +153.200 | J/1 | Pt0(?) | 400 | Tekla Assemblages - Cast unit type: Coulé sur site; Poids ferraillage Elément béton: 0 kg

# IfcMechanicalFastener: Bolt assembly (420)
In: Undefined
Tekla Boulons - Trou oblong Y: 0 mm; Trou oblong X: 0 mm; Lieu Boulonnage: Montage
Name | NominalDiameter (mm) = Diamètre rondelle (mm) = Diamètre (mm) | NominalLength (mm) = Longueur (mm) | Material = Standard | Quantité de rondelle | Type rondelle | Nom rondelle | Quantité d'écrou = Quantité | Type écrou | Nom écrou | Diamètre du trou (mm) | Nom
Bolt assembly | 16 | 35 | 8.8 | 0 | PLA-8.8 | RONDELLE-M16-PLA-8.8 | 2 | E-8.8 | ECROU-M16-E-8.8 | 18 | M16*35
14 x Bolt assembly | 16 | 40 | 8.8 | 0 | PLA-8.8 | RONDELLE-M16-PLA-8.8 | 2 | E-8.8 | ECROU-M16-E-8.8 | 18 | M16*40
13 x Bolt assembly | 16 | 45 | 8.8 | 4 | PLA-8.8 | RONDELLE-M16-PLA-8.8 | 2 | E-8.8 | ECROU-M16-E-8.8 | 18 | M16*45
14 x Bolt assembly | 12 | 35 | 8.8 | 6 | PLA-8.8 | RONDELLE-M12-PLA-8.8 | 3 | E-8.8 | ECROU-M12-E-8.8 | 14 | M12*35
7 x Bolt assembly | 12 | 40 | 8.8 | 4 | PLA-8.8 | RONDELLE-M12-PLA-8.8 | 2 | E-8.8 | ECROU-M12-E-8.8 | 14 | M12*40
11 x Bolt assembly | 12 | 60 | INOX-A4 | 4 | PLA-A4 | RONDELLE-M12-PLA-INOX-A4 | 2 | E-INOX-A4 | ECROU-M12-E-INOX-A4 | 14 | M12*60
Bolt assembly | 12 | 30 | 8.8 | 2 | PLA-8.8 | RONDELLE-M12-PLA-8.8 | 2 | E-8.8 | ECROU-M12-E-8.8 | 14 | M12*30
Bolt assembly | 16 | 45 | 8.8 | 6 | PLA-8.8 | RONDELLE-M16-PLA-8.8 | 3 | E-8.8 | ECROU-M16-E-8.8 | 18 | M16*45
358 x Bolt assembly | 12 | 35 | 6.8 | 2 | PLA-6.8 | RONDELLE-M12-PLA-6.8 | 2 | E-6.8 | ECROU-M12-E-6.8 | 12 | M12*35

# IfcMember: 240*240 (24)
In: Undefined
Description: 240*240; Material: TIMBER/CHENE
Tekla Commun - Repère de pièce: Po0(?); Repère d'assemblage: Po0(?); Phase: 1402; Classe: 6; Matériau: CHENE; Profil: 240*240; Nom: POUTRE
Tekla Quantités - Volume: 0.3 m3; Surface supérieure totale: 0 m2; Surface par tonne: 19 m2; Hauteur: 240 mm; Largeur: 240 mm
Pset_MemberCommon - LoadBearing: no; Reference: Po0(?)
BaseQuantities - CrossSectionArea: 0.0576 m2
Name | Niveau bas | Niveau haut | Poids (kg) | Surface nette (m2) | Longueur (mm) | Length (mm) | OuterSurfaceArea (m2) = GrossSurfaceArea (m2) | NetVolume (m3) = GrossVolume (m3) | NetWeight (kg) = GrossWeight (kg)
4 x POUTRE | +153.301 | +156.339 | 262 | 5 | 5053.5 | 5053.51 | 4.96657 | 0.291082 | 261.974
7 x POUTRE | +156.146 | +159.634 | 276.1 | 5.2 | 5325.6 | 5325.64 | 5.22781 | 0.306757 | 276.081
POUTRE | +156.146 | +159.634 | 276.1 | 5.2 | 5325.6 | 5325.63 | 5.2278 | 0.306756 | 276.081
2 x POUTRE | +159.448 | +163.094 | 281.3 | 5.3 | 5426.9 | 5426.92 | 5.32504 | 0.31259 | 281.331
2 x POUTRE | +159.448 | +163.136 | 282.8 | 5.3 | 5454.6 | 5454.63 | 5.35165 | 0.314187 | 282.768
4 x POUTRE | +152.846 | +156.334 | 276.1 | 5.2 | 5325.6 | 5325.64 | 5.22781 | 0.306757 | 276.081
POUTRE | +159.448 | +163.098 | 281.5 | 5.3 | 5429.5 | 5429.5 | 5.32752 | 0.312739 | 281.465
POUTRE | +159.448 | +163.098 | 281.5 | 5.3 | 5429.5 | 5429.49 | 5.32751 | 0.312739 | 281.465
POUTRE | +159.448 | +163.134 | 282.7 | 5.3 | 5453.2 | 5453.22 | 5.35029 | 0.314106 | 282.695
POUTRE | +159.448 | +163.134 | 282.7 | 5.3 | 5453.2 | 5453.23 | 5.3503 | 0.314106 | 282.695

# IfcMember: PL10*50 (12)
In: Undefined
Description: PL10*50; Material: STEEL/S235JR
Tekla Commun - Repère de pièce: 0(?); Repère d'assemblage: GC0(?); Phase: 601; Classe: 13; Matériau: S235JR; Profil: PL10*50
Tekla Quantités - Volume: 0 m3; Surface supérieure totale: 0 m2; Surface par tonne: 30.7 m2; Hauteur: 50 mm; Largeur: 10 mm
Pset_MemberCommon - LoadBearing: no; Reference: 0(?)
BaseQuantities - CrossSectionArea: 0.0005 m2
Name | Niveau bas | Niveau haut | Nom | Poids (kg) | Surface nette (m2) | Longueur (mm) | Length (mm) | OuterSurfaceArea (m2) | GrossSurfaceArea (m2) | NetVolume (m3) | GrossVolume (m3) | NetWeight (kg) | GrossWeight (kg)
LISSE | +159.400 | +160.008 | LISSE | 4.8 | 0.1 | 1239.5 | 1239.47 | 0.149216 | 0.153258 | 0.000616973 | 0.000634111 | 4.84323 | 4.86493
LISSE | +158.184 | +159.400 | LISSE | 9.7 | 0.4 | 2496.3 | 2496.27 | 0.298432 | 0.302631 | 0.00123395 | 0.0012568 | 9.68647 | 9.79785
LISSE | +156.921 | +157.529 | LISSE | 4.8 | 0.1 | 1239.5 | 1239.47 | 0.149216 | 0.153258 | 0.000616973 | 0.000634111 | 4.84323 | 4.86493
MAIN_COURANTE | +157.741 | +158.365 | MAIN_COURANTE | 5 | 0.2 | 1271 | 1270.98 | 0.153258 | 0.153258 | 0.000634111 | 0.000634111 | 4.97777 | 4.98861
LISSE | +157.529 | +158.745 | LISSE | 9.7 | 0.4 | 2496.3 | 2496.27 | 0.298432 | 0.302631 | 0.00123395 | 0.0012568 | 9.68647 | 9.79785
LISSE | +158.744 | +159.961 | LISSE | 9.7 | 0.4 | 2496.3 | 2496.27 | 0.298432 | 0.304073 | 0.00123395 | 0.00126251 | 9.68647 | 9.79785
MAIN_COURANTE | +158.356 | +159.580 | MAIN_COURANTE | 10 | 0.4 | 2513.6 | 2513.59 | 0.302631 | 0.302631 | 0.0012568 | 0.0012568 | 9.86585 | 9.86585
MAIN_COURANTE | +159.572 | +160.803 | MAIN_COURANTE | 10 | 0.4 | 2527.8 | 2527.78 | 0.304073 | 0.304073 | 0.00126251 | 0.00126251 | 9.91069 | 9.92154
MAIN_COURANTE | +160.227 | +160.850 | MAIN_COURANTE | 5 | 0.2 | 1271 | 1270.98 | 0.153258 | 0.153258 | 0.000634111 | 0.000634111 | 4.97777 | 4.98861
LISSE | +156.968 | +158.184 | LISSE | 9.7 | 0.4 | 2496.3 | 2496.27 | 0.298432 | 0.304073 | 0.00123395 | 0.00126251 | 9.68647 | 9.79785
MAIN_COURANTE | +159.011 | +160.236 | MAIN_COURANTE | 10 | 0.4 | 2513.6 | 2513.59 | 0.302631 | 0.302631 | 0.0012568 | 0.0012568 | 9.86585 | 9.86585
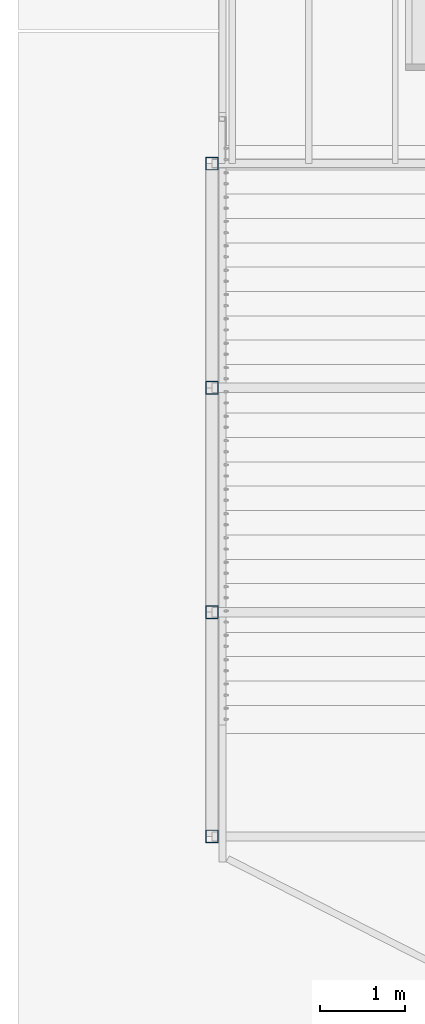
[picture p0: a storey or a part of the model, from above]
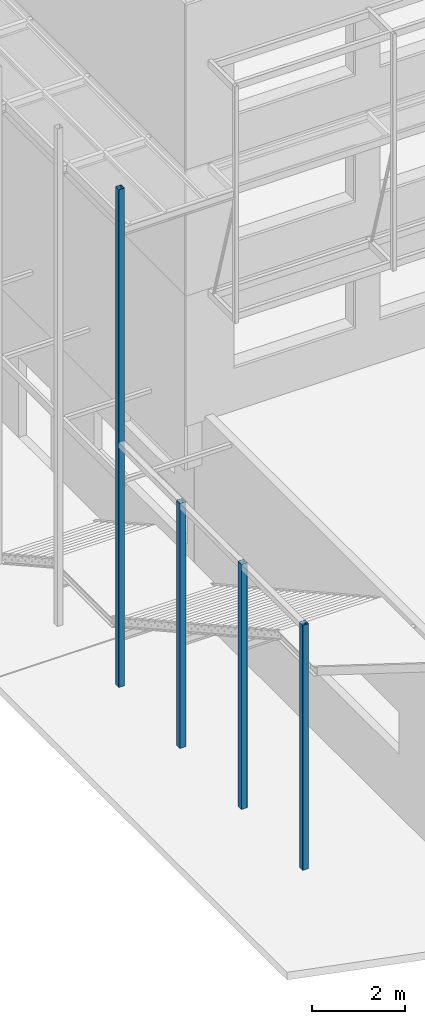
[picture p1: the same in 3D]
Properties of the parts of a building model (IFC2X3), part 3 of 3

# IfcMember: PL10*50 (12)
Name | Niveau bas | Niveau haut | Nom | Poids (kg) | Surface nette (m2) | Longueur (mm) | Length (mm) | OuterSurfaceArea (m2) | GrossSurfaceArea (m2) | NetVolume (m3) | GrossVolume (m3) | NetWeight (kg) | GrossWeight (kg)
MAIN_COURANTE | +157.788 | +159.020 | MAIN_COURANTE | 10 | 0.4 | 2527.8 | 2527.78 | 0.304073 | 0.304073 | 0.00126251 | 0.00126251 | 9.91069 | 9.92154

# IfcMember: TUBE-60.3*4 (7)
In: Undefined
Description: TUBE-60.3*4; Material: STEEL/S275JR
Pset_MemberCommon - LoadBearing: no; Reference: 0(?)
Tekla Commun - Niveau bas: +156.670; Niveau haut: +159.687; Repère de pièce: 0(?); Repère d'assemblage: A0(?); Phase: 301; Classe: 3; Matériau: S275JR; Profil: TUBE-60.3*4; Nom: STAB
Tekla Quantités - Poids: 17.5 kg; Volume: 0 m3; Surface supérieure totale: 0 m2; Surface par tonne: 32.8 m2; Surface nette: 0.7 m2; Hauteur: 60.3 mm; Largeur: 60.3 mm; Longueur: 3152.4 mm
BaseQuantities - Length: 3152.44 mm; OuterSurfaceArea: 0.574574 m2; GrossSurfaceArea: 0 m2; CrossSectionArea: 0.000707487 m2; NetVolume: 0.00209853 m3; GrossVolume: 0.00223031 m3; NetWeight: 16.4735 kg; GrossWeight: 17.5079 kg

# IfcMember: UPN220 (22)
In: Undefined
Description: UPN220
Pset_MemberCommon - LoadBearing: no; Reference: 0(?)
Tekla Commun - Repère de pièce: 0(?); Repère d'assemblage: L0(?); Phase: 301; Classe: 1; Profil: UPN220; Nom: LIMON
Tekla Quantités - Volume: 0 m3; Surface supérieure totale: 0 m2; Surface par tonne: 24.5 m2; Hauteur: 220 mm; Largeur: 80 mm
BaseQuantities - CrossSectionArea: 0.00374 m2
Name | Material | Niveau bas | Niveau haut | Matériau | Poids (kg) | Surface nette (m2) | Longueur (mm) | Length (mm) | OuterSurfaceArea (m2) = GrossSurfaceArea (m2) | NetVolume (m3) | GrossVolume (m3) | NetWeight (kg) | GrossWeight (kg)
2 x LIMON | STEEL/S235JR | +153.150 | +156.670 | S235JR | 202 | 5 | 6879.4 | 6879.35 | 4.93937 | 0.0252701 | 0.0257288 | 198.37 | 201.971
2 x LIMON | STEEL/S235JR | +153.138 | +156.670 | S235JR | 203.8 | 5 | 6942.8 | 6942.82 | 4.98494 | 0.0253314 | 0.0259661 | 198.852 | 203.834
2 x LIMON | STEEL/S235JR | +147.356 | +148.475 | S235JR | 55.7 | 1.4 | 1898.1 | 1898.15 | 1.36287 | 0.00692427 | 0.00709908 | 54.3555 | 55.7278
LIMON | STEEL/S235JR | +149.838 | +153.370 | S235JR | 203.8 | 5 | 6942.8 | 6942.82 | 4.98494 | 0.0253314 | 0.0259661 | 198.852 | 203.834
LIMON | STEEL/S235JR | +149.850 | +153.370 | S235JR | 202 | 5 | 6879.4 | 6879.35 | 4.93937 | 0.0252701 | 0.0257288 | 198.37 | 201.971
2 x LIMON | STEEL/S235JR | +148.255 | +150.070 | S235JR | 97.6 | 2.5 | 3323.3 | 3323.34 | 2.38616 | 0.0120967 | 0.0124293 | 94.9594 | 97.5699
2 x LIMON | STEEL/S235JR | +156.438 | +159.970 | S235JR | 203.8 | 5 | 6942.8 | 6942.82 | 4.98494 | 0.0253314 | 0.0259661 | 198.852 | 203.834
2 x LIMON | STEEL/S235JR | +156.450 | +159.970 | S235JR | 202 | 5 | 6879.4 | 6879.35 | 4.93937 | 0.0252701 | 0.0257288 | 198.37 | 201.971
2 x LIMON | STEEL/S235JR | +149.175 | +153.370 | S235JR | 241.2 | 6 | 8216 | 8216.03 | 5.89911 | 0.0302193 | 0.030728 | 237.221 | 241.214
2 x LIMON | STEEL/S235JR | +147.802 | +149.395 | S235JR | 84.4 | 2.1 | 2875.6 | 2875.6 | 2.06468 | 0.0105449 | 0.0107547 | 82.7775 | 84.4247
2 x LIMON | STEEL/S275JR | +147.798 | +150.870 | S275JR | 183 | 4.5 | 6232.2 | 6232.16 | 4.47469 | 0.0229835 | 0.0233083 | 180.42 | 182.97
2 x LIMON | STEEL/S235JR | +150.650 | +153.370 | S235JR | 157.8 | 3.9 | 5375.3 | 5375.34 | 3.85949 | 0.0197062 | 0.0201038 | 154.694 | 157.815

# IfcPlate: 120*43450 (2)
In: Undefined
Description: 120*43450; Material: TIMBER/CHENE
Tekla Commun - Repère de pièce: Da0(?); Repère d'assemblage: Da0(?); Phase: 1402; Classe: 11; Matériau: CHENE; Profil: 120*43450; Nom: DALLE
Tekla Quantités - Poids: 95931.8 kg; Volume: 106.6 m3; Surface supérieure totale: 888.3 m2; Surface par tonne: 18.8 m2; Surface nette: 1799.6 m2; Hauteur: 43450 mm; Largeur: 120 mm; Longueur: 35220 mm
Pset_PlateCommon - Support de charge: no; Réference: Da0(?)
BaseQuantities - Width: 43450 mm; NetArea: 1799.55 m2; GrossArea: 1530.31 m2; CrossSectionArea: 0.0144 m2; NetVolume: 106.591 m3; GrossVolume: 115.59 m3
Name | Niveau bas | Niveau haut
DALLE | +159.780 | +159.900
DALLE | +156.480 | +156.600

# IfcPlate: PL10*140 (3)
In: Undefined
Description: PL10*140; Material: STEEL/S235JR
Pset_PlateCommon - Support de charge: no; Réference: 0(?)
Tekla Commun - Repère de pièce: 0(?); Repère d'assemblage: P0(?); Phase: 301; Classe: 99; Matériau: S235JR; Profil: PL10*140; Nom: PLATINE
Tekla Quantités - Poids: 3 kg; Volume: 0 m3; Surface supérieure totale: 0 m2; Surface par tonne: 28.3 m2; Surface nette: 0.1 m2; Hauteur: 140 mm; Largeur: 10 mm; Longueur: 260 mm
BaseQuantities - Width: 140 mm; NetArea: 0.0808 m2; GrossArea: 0.0808 m2; CrossSectionArea: 0.0014 m2; NetVolume: 0.000364 m3; GrossVolume: 0.000364 m3
Name | Niveau bas | Niveau haut
PLATINE | +150.620 | +150.880
PLATINE | +153.120 | +153.380
PLATINE | +156.420 | +156.680

# IfcPlate: PL10*70 (7)
In: Undefined
Description: PL10*70; Material: STEEL/S235JR
Pset_PlateCommon - Support de charge: no; Réference: 0(?)
Tekla Commun - Repère de pièce: 0(?); Classe: 99; Matériau: S235JR; Profil: PL10*70; Nom: TOLE
Tekla Quantités - Poids: 0.5 kg; Volume: 0 m3; Surface supérieure totale: 0 m2; Surface par tonne: 31.7 m2; Surface nette: 0 m2; Hauteur: 70 mm; Largeur: 10 mm; Longueur: 100 mm
BaseQuantities - Width: 70 mm; NetArea: 0.0174 m2; GrossArea: 0.007 m2; CrossSectionArea: 0.0001 m2; NetVolume: 0.00007 m3; GrossVolume: 0.00007 m3
Name | Niveau bas | Niveau haut | Repère d'assemblage | Phase
TOLE | +156.545 | +156.645 | A0(?) | 303
2 x TOLE | +156.550 | +156.650 | P0(?) | 301
3 x TOLE | +156.545 | +156.645 | A0(?) | 301
TOLE | +156.545 | +156.645 | P0(?) | 301

# IfcPlate: PL10*80 (2)
In: Undefined
Description: PL10*80; Material: STEEL/S235JR
Pset_PlateCommon - Support de charge: no; Réference: 0(?)
Tekla Commun - Niveau bas: +156.480; Niveau haut: +156.640; Repère de pièce: 0(?); Repère d'assemblage: P0(?); Phase: 301; Classe: 99; Matériau: S235JR; Profil: PL10*80; Nom: TOLE
Tekla Quantités - Poids: 1 kg; Volume: 0 m3; Surface supérieure totale: 0 m2; Surface par tonne: 30.3 m2; Surface nette: 0 m2; Hauteur: 80 mm; Largeur: 10 mm; Longueur: 160 mm
BaseQuantities - Width: 80 mm; NetArea: 0.0304 m2; GrossArea: 0.0128 m2; CrossSectionArea: 0.0001 m2; NetVolume: 0.000128 m3; GrossVolume: 0.000128 m3

# IfcPlate: PL15*150 (11)
In: Undefined
Description: PL15*150; Material: STEEL/S235JR
Pset_PlateCommon - Support de charge: no; Réference: 0(?)
Tekla Commun - Repère de pièce: 0(?); Repère d'assemblage: A0(?); Phase: 301; Classe: 99; Matériau: S235JR; Profil: PL15*150; Nom: PLATINE
Tekla Quantités - Poids: 1 kg; Volume: 0 m3; Surface supérieure totale: 0 m2; Surface par tonne: 23.3 m2; Surface nette: 0 m2; Hauteur: 150 mm; Largeur: 15 mm; Longueur: 55 mm
BaseQuantities - Width: 150 mm; NetArea: 0.02265 m2; GrossArea: 0.02265 m2; CrossSectionArea: 0.00225 m2; NetVolume: 0.00012375 m3; GrossVolume: 0.00012375 m3
Name | Niveau bas | Niveau haut
8 x PLATINE | +156.510 | +156.660
3 x PLATINE | +159.810 | +159.960

# IfcPlate: PL1800*70 (147)
In: Undefined
Description: PL1800*70; Material: STEEL/S235JR
Tekla Commun - Repère de pièce: MA0(?); Repère d'assemblage: MA0(?); Phase: 301; Classe: 5; Matériau: S235JR; Profil: PL1800*70; Nom: MARCHE
Tekla Quantités - Poids: 317.9 kg; Volume: 0 m3; Surface supérieure totale: 0.6 m2; Surface par tonne: 4.6 m2; Surface nette: 1.4 m2; Hauteur: 70 mm; Largeur: 1800 mm; Longueur: 330 mm
Pset_PlateCommon - Support de charge: no; Réference: MA0(?)
BaseQuantities - Width: 70 mm; NetArea: 1.449 m2; GrossArea: 0.0231 m2; CrossSectionArea: 3.24 m2; NetVolume: 0.0405 m3; GrossVolume: 0.0405 m3
Name | Niveau bas | Niveau haut
MARCHE | +148.276 | +148.346
MARCHE | +149.871 | +149.941
MARCHE | +148.116 | +148.186
MARCHE | +149.711 | +149.781
2 x MARCHE | +156.473 | +156.543
2 x MARCHE | +156.315 | +156.385
2 x MARCHE | +156.158 | +156.228
2 x MARCHE | +156.000 | +156.070
2 x MARCHE | +155.843 | +155.913
2 x MARCHE | +155.685 | +155.755
2 x MARCHE | +155.528 | +155.598
2 x MARCHE | +155.370 | +155.440
2 x MARCHE | +155.213 | +155.283
2 x MARCHE | +155.055 | +155.125
2 x MARCHE | +154.898 | +154.968
2 x MARCHE | +154.740 | +154.810
2 x MARCHE | +154.583 | +154.653
2 x MARCHE | +154.425 | +154.495
2 x MARCHE | +154.268 | +154.338
2 x MARCHE | +154.110 | +154.180
2 x MARCHE | +153.953 | +154.023
2 x MARCHE | +153.795 | +153.865
2 x MARCHE | +153.638 | +153.708
2 x MARCHE | +153.480 | +153.550
MARCHE | +147.957 | +148.027
MARCHE | +147.797 | +147.867
MARCHE | +147.638 | +147.708
MARCHE | +153.173 | +153.243
MARCHE | +153.015 | +153.085
MARCHE | +152.858 | +152.928
MARCHE | +152.700 | +152.770
MARCHE | +152.543 | +152.613
MARCHE | +152.385 | +152.455
MARCHE | +152.228 | +152.298
MARCHE | +152.070 | +152.140
MARCHE | +151.913 | +151.983
MARCHE | +151.755 | +151.825
MARCHE | +151.598 | +151.668
MARCHE | +151.440 | +151.510
MARCHE | +151.283 | +151.353
MARCHE | +151.125 | +151.195
MARCHE | +150.968 | +151.038
MARCHE | +150.810 | +150.880
MARCHE | +150.653 | +150.723
MARCHE | +150.495 | +150.565
MARCHE | +150.338 | +150.408
MARCHE | +150.180 | +150.250
MARCHE | +148.914 | +148.984
MARCHE | +148.754 | +148.824
MARCHE | +149.073 | +149.143
MARCHE | +149.233 | +149.303
MARCHE | +148.595 | +148.665
MARCHE | +149.392 | +149.462
MARCHE | +149.552 | +149.622
2 x MARCHE | +159.773 | +159.843
2 x MARCHE | +159.615 | +159.685
2 x MARCHE | +159.458 | +159.528
2 x MARCHE | +159.300 | +159.370
2 x MARCHE | +159.143 | +159.213
2 x MARCHE | +158.985 | +159.055
2 x MARCHE | +158.828 | +158.898
2 x MARCHE | +158.670 | +158.740
2 x MARCHE | +158.513 | +158.583
2 x MARCHE | +158.355 | +158.425
2 x MARCHE | +158.198 | +158.268
2 x MARCHE | +158.040 | +158.110
2 x MARCHE | +157.883 | +157.953
2 x MARCHE | +157.725 | +157.795
2 x MARCHE | +157.568 | +157.638
2 x MARCHE | +157.410 | +157.480
2 x MARCHE | +157.253 | +157.323
2 x MARCHE | +157.095 | +157.165
2 x MARCHE | +156.938 | +157.008
2 x MARCHE | +156.780 | +156.850
MARCHE | +150.677 | +150.747
MARCHE | +150.524 | +150.594
MARCHE | +150.371 | +150.441
MARCHE | +150.218 | +150.288
MARCHE | +150.065 | +150.135
MARCHE | +149.912 | +149.982
MARCHE | +149.759 | +149.829
MARCHE | +149.606 | +149.676
MARCHE | +149.453 | +149.523
MARCHE | +149.300 | +149.370
MARCHE | +149.147 | +149.217
MARCHE | +148.994 | +149.064
MARCHE | +148.841 | +148.911
MARCHE | +148.688 | +148.758
MARCHE | +148.535 | +148.605
MARCHE | +148.382 | +148.452
MARCHE | +148.229 | +148.299
MARCHE | +148.076 | +148.146
MARCHE | +153.174 | +153.244
MARCHE | +153.017 | +153.087
MARCHE | +152.861 | +152.931
MARCHE | +152.704 | +152.774
MARCHE | +152.548 | +152.618
MARCHE | +152.391 | +152.461
MARCHE | +152.235 | +152.305
MARCHE | +152.078 | +152.148
MARCHE | +151.922 | +151.992
MARCHE | +151.765 | +151.835
MARCHE | +151.609 | +151.679
MARCHE | +151.452 | +151.522
MARCHE | +151.296 | +151.366
MARCHE | +151.139 | +151.209
MARCHE | +150.983 | +151.053

# IfcPlate: PL2400*70 (32)
In: Undefined
Description: PL2400*70; Material: STEEL/S235JR
Pset_PlateCommon - Support de charge: no; Réference: MA0(?)
Tekla Commun - Repère de pièce: MA0(?); Repère d'assemblage: MA0(?); Phase: 301; Classe: 5; Matériau: S235JR; Profil: PL2400*70; Nom: MARCHE
Tekla Quantités - Poids: 423.9 kg; Volume: 0.1 m3; Surface supérieure totale: 0.8 m2; Surface par tonne: 4.5 m2; Surface nette: 2 m2; Hauteur: 70 mm; Largeur: 2400 mm; Longueur: 330 mm
BaseQuantities - Width: 70 mm; NetArea: 1.917 m2; GrossArea: 0.0231 m2; CrossSectionArea: 5.76 m2; NetVolume: 0.054 m3; GrossVolume: 0.054 m3
Name | Niveau bas | Niveau haut
MARCHE | +153.171 | +153.241
MARCHE | +153.012 | +153.082
MARCHE | +152.853 | +152.923
MARCHE | +152.694 | +152.764
MARCHE | +152.535 | +152.605
MARCHE | +152.376 | +152.446
MARCHE | +152.217 | +152.287
MARCHE | +152.058 | +152.128
MARCHE | +151.899 | +151.969
MARCHE | +151.740 | +151.810
MARCHE | +151.581 | +151.651
MARCHE | +151.422 | +151.492
MARCHE | +151.263 | +151.333
MARCHE | +151.104 | +151.174
MARCHE | +150.945 | +151.015
MARCHE | +150.786 | +150.856
MARCHE | +150.468 | +150.538
MARCHE | +150.309 | +150.379
MARCHE | +150.150 | +150.220
MARCHE | +149.991 | +150.061
MARCHE | +149.832 | +149.902
MARCHE | +149.673 | +149.743
MARCHE | +149.514 | +149.584
MARCHE | +150.627 | +150.697
MARCHE | +149.037 | +149.107
MARCHE | +148.878 | +148.948
MARCHE | +148.719 | +148.789
MARCHE | +148.560 | +148.630
MARCHE | +148.401 | +148.471
MARCHE | +148.242 | +148.312
MARCHE | +148.083 | +148.153
MARCHE | +149.196 | +149.266

# IfcPlate: PL30*1000, CAILLEBOTIS
In: Undefined
Description: PL30*1000; Material: STEEL/S235JR
Pset_PlateCommon - Support de charge: no; Réference: G0(?)
Tekla Commun - Niveau bas: +159.970; Niveau haut: +160.000; Repère de pièce: G0(?); Repère d'assemblage: G0(?); Phase: 401; Classe: 99; Matériau: S235JR; Profil: PL30*1000; Nom: CAILLEBOTIS
Tekla Quantités - Poids: 5398.7 kg; Volume: 0.7 m3; Surface supérieure totale: 22.9 m2; Surface par tonne: 8.7 m2; Surface nette: 47.3 m2; Hauteur: 1000 mm; Largeur: 30 mm; Longueur: 22924.6 mm
BaseQuantities - Width: 1000 mm; NetArea: 47.2846 m2; GrossArea: 22.9246 m2; CrossSectionArea: 0.0009 m2; NetVolume: 0.687737 m3; GrossVolume: 0.687737 m3

# IfcPlate: PL30*2070, CAILLEBOTIS
In: Undefined
Description: PL30*2070; Material: STEEL/S235JR
Pset_PlateCommon - Support de charge: no; Réference: G0(?)
Tekla Commun - Niveau bas: +159.970; Niveau haut: +160.000; Repère de pièce: G0(?); Repère d'assemblage: G0(?); Phase: 401; Classe: 99; Matériau: S235JR; Profil: PL30*2070; Nom: CAILLEBOTIS
Tekla Quantités - Poids: 1347.9 kg; Volume: 0.2 m3; Surface supérieure totale: 5.7 m2; Surface par tonne: 8.7 m2; Surface nette: 11.7 m2; Hauteur: 2070 mm; Largeur: 30 mm; Longueur: 2765 mm
BaseQuantities - Width: 2070 mm; NetArea: 11.7372 m2; GrossArea: 5.72355 m2; CrossSectionArea: 0.0009 m2; NetVolume: 0.171706 m3; GrossVolume: 0.171706 m3

# IfcPlate: PL30*2135, CAILLEBOTIS
In: Undefined
Description: PL30*2135; Material: STEEL/S235JR
Pset_PlateCommon - Support de charge: no; Réference: G0(?)
Tekla Commun - Niveau bas: +148.475; Niveau haut: +148.505; Repère de pièce: G0(?); Repère d'assemblage: G0(?); Phase: 401; Classe: 99; Matériau: S235JR; Profil: PL30*2135; Nom: CAILLEBOTIS
Tekla Quantités - Poids: 1910.3 kg; Volume: 0.2 m3; Surface supérieure totale: 8.1 m2; Surface par tonne: 8.7 m2; Surface nette: 16.6 m2; Hauteur: 2135 mm; Largeur: 30 mm; Longueur: 4130 mm
BaseQuantities - Width: 2135 mm; NetArea: 16.6054 m2; GrossArea: 8.81755 m2; CrossSectionArea: 0.0009 m2; NetVolume: 0.243351 m3; GrossVolume: 0.243351 m3

# IfcPlate: PL30*2560, CAILLEBOTIS
In: Undefined
Description: PL30*2560; Material: STEEL/S235JR
Pset_PlateCommon - Support de charge: no; Réference: G0(?)
Tekla Commun - Niveau bas: +153.370; Niveau haut: +153.400; Repère de pièce: G0(?); Repère d'assemblage: G0(?); Phase: 401; Classe: 99; Matériau: S235JR; Profil: PL30*2560; Nom: CAILLEBOTIS
Tekla Quantités - Poids: 1300.5 kg; Volume: 0.2 m3; Surface supérieure totale: 5.5 m2; Surface par tonne: 8.7 m2; Surface nette: 11.3 m2; Hauteur: 2560 mm; Largeur: 30 mm; Longueur: 2808.5 mm
BaseQuantities - Width: 2560 mm; NetArea: 11.3366 m2; GrossArea: 7.18986 m2; CrossSectionArea: 0.0009 m2; NetVolume: 0.165663 m3; GrossVolume: 0.165663 m3

# IfcPlate: PL30*2606, CAILLEBOTIS
In: Undefined
Description: PL30*2606; Material: STEEL/S235JR
Pset_PlateCommon - Support de charge: no; Réference: G0(?)
Tekla Commun - Niveau bas: +159.970; Niveau haut: +160.000; Repère de pièce: G0(?); Repère d'assemblage: G0(?); Phase: 401; Classe: 99; Matériau: S235JR; Profil: PL30*2606; Nom: CAILLEBOTIS
Tekla Quantités - Poids: 6220 kg; Volume: 0.7 m3; Surface supérieure totale: 26.4 m2; Surface par tonne: 8.6 m2; Surface nette: 53.7 m2; Hauteur: 2606.4 mm; Largeur: 30 mm; Longueur: 12757 mm
BaseQuantities - Width: 2606.43 mm; NetArea: 53.7455 m2; GrossArea: 33.2502 m2; CrossSectionArea: 0.0009 m2; NetVolume: 0.792356 m3; GrossVolume: 0.792356 m3

# IfcPlate: PL30*2885, CAILLEBOTIS
In: Undefined
Description: PL30*2885; Material: STEEL/S235JR
Pset_PlateCommon - Support de charge: no; Réference: G0(?)
Tekla Commun - Niveau bas: +149.395; Niveau haut: +149.425; Repère de pièce: G0(?); Repère d'assemblage: G0(?); Phase: 401; Classe: 99; Matériau: S235JR; Profil: PL30*2885; Nom: CAILLEBOTIS
Tekla Quantités - Poids: 1723.7 kg; Volume: 0.2 m3; Surface supérieure totale: 7.3 m2; Surface par tonne: 8.7 m2; Surface nette: 15 m2; Hauteur: 2885 mm; Largeur: 30 mm; Longueur: 2560 mm
BaseQuantities - Width: 2885 mm; NetArea: 14.9657 m2; GrossArea: 7.3856 m2; CrossSectionArea: 0.0009 m2; NetVolume: 0.219585 m3; GrossVolume: 0.219585 m3

# IfcPlate: PL30*3035, CAILLEBOTIS
In: Undefined
Description: PL30*3035; Material: STEEL/S235JR
Pset_PlateCommon - Support de charge: no; Réference: G0(?)
Tekla Commun - Niveau bas: +150.070; Niveau haut: +150.100; Repère de pièce: G0(?); Repère d'assemblage: G0(?); Phase: 401; Classe: 99; Matériau: S235JR; Profil: PL30*3035; Nom: CAILLEBOTIS
Tekla Quantités - Poids: 2780.2 kg; Volume: 0.5 m3; Surface supérieure totale: 11.8 m2; Surface par tonne: 8.7 m2; Surface nette: 24.1 m2; Hauteur: 3035 mm; Largeur: 30 mm; Longueur: 4633 mm
BaseQuantities - Width: 3035 mm; NetArea: 24.0714 m2; GrossArea: 14.0612 m2; CrossSectionArea: 0.0009 m2; NetVolume: 0.35417 m3; GrossVolume: 0.35417 m3

# IfcPlate: PL30*4190, CAILLEBOTIS
In: Undefined
Description: PL30*4190; Material: STEEL/S235JR
Pset_PlateCommon - Support de charge: no; Réference: G0(?)
Tekla Commun - Niveau bas: +153.370; Niveau haut: +153.400; Repère de pièce: G0(?); Repère d'assemblage: G0(?); Phase: 401; Classe: 99; Matériau: S235JR; Profil: PL30*4190; Nom: CAILLEBOTIS
Tekla Quantités - Poids: 8351.3 kg; Volume: 1.1 m3; Surface supérieure totale: 35.5 m2; Surface par tonne: 8.6 m2; Surface nette: 72 m2; Hauteur: 4190 mm; Largeur: 30 mm; Longueur: 11450 mm
BaseQuantities - Width: 4189.97 mm; NetArea: 72.033 m2; GrossArea: 47.9751 m2; CrossSectionArea: 0.0009 m2; NetVolume: 1.06386 m3; GrossVolume: 1.06386 m3

# IfcPlate: PL30*4215, CAILLEBOTIS
In: Undefined
Description: PL30*4215; Material: STEEL/S235JR
Pset_PlateCommon - Support de charge: no; Réference: G0(?)
Tekla Commun - Niveau bas: +156.670; Niveau haut: +156.700; Repère de pièce: G0(?); Repère d'assemblage: G0(?); Phase: 401; Classe: 99; Matériau: S235JR; Profil: PL30*4215; Nom: CAILLEBOTIS
Tekla Quantités - Poids: 8378.9 kg; Volume: 1.1 m3; Surface supérieure totale: 35.6 m2; Surface par tonne: 8.6 m2; Surface nette: 72.3 m2; Hauteur: 4215 mm; Largeur: 30 mm; Longueur: 11450 mm
BaseQuantities - Width: 4214.97 mm; NetArea: 72.2706 m2; GrossArea: 48.2614 m2; CrossSectionArea: 0.0009 m2; NetVolume: 1.06738 m3; GrossVolume: 1.06738 m3

# IfcPlate: PL30*4240 (2)
In: Undefined
Description: PL30*4240; Material: STEEL/S235JR
Pset_PlateCommon - Support de charge: no; Réference: G0(?)
Tekla Commun - Repère de pièce: G0(?); Repère d'assemblage: G0(?); Phase: 401; Classe: 99; Matériau: S235JR; Profil: PL30*4240; Nom: CAILLEBOTIS
Tekla Quantités - Poids: 8431.4 kg; Volume: 1.1 m3; Surface supérieure totale: 35.8 m2; Surface par tonne: 8.6 m2; Surface nette: 72.7 m2; Hauteur: 4240 mm; Largeur: 30 mm; Longueur: 11450 mm
BaseQuantities - Width: 4240 mm; NetArea: 72.7206 m2; GrossArea: 48.548 m2; CrossSectionArea: 0.0009 m2; NetVolume: 1.07406 m3; GrossVolume: 1.07406 m3
Name | Niveau bas | Niveau haut
CAILLEBOTIS | +153.370 | +153.400
CAILLEBOTIS | +156.670 | +156.700

# IfcPlate: PL30*4325, CAILLEBOTIS
In: Undefined
Description: PL30*4325; Material: STEEL/S235JR
Pset_PlateCommon - Support de charge: no; Réference: G0(?)
Tekla Commun - Niveau bas: +150.870; Niveau haut: +150.900; Repère de pièce: G0(?); Repère d'assemblage: G0(?); Phase: 401; Classe: 99; Matériau: S235JR; Profil: PL30*4325; Nom: CAILLEBOTIS
Tekla Quantités - Poids: 3713.5 kg; Volume: 0.5 m3; Surface supérieure totale: 15.8 m2; Surface par tonne: 8.6 m2; Surface nette: 32.1 m2; Hauteur: 4325 mm; Largeur: 30 mm; Longueur: 4656.4 mm
BaseQuantities - Width: 4325 mm; NetArea: 32.0887 m2; GrossArea: 20.1389 m2; CrossSectionArea: 0.0009 m2; NetVolume: 0.473059 m3; GrossVolume: 0.473059 m3

# IfcPlate: PL6*119, GOUSSET
In: Undefined
Description: PL6*119; Material: STEEL/S235JR
Pset_PlateCommon - Support de charge: no; Réference: 0(?)
Tekla Commun - Niveau bas: +156.557; Niveau haut: +156.563; Repère de pièce: 0(?); Repère d'assemblage: A0(?); Phase: 301; Classe: 99; Matériau: S235JR; Profil: PL6*119; Nom: GOUSSET
Tekla Quantités - Poids: 0.7 kg; Volume: 0 m3; Surface supérieure totale: 0 m2; Surface par tonne: 47.2 m2; Surface nette: 0 m2; Hauteur: 119.5 mm; Largeur: 6 mm; Longueur: 180.5 mm
BaseQuantities - Width: 119.453 mm; NetArea: 0.029403 m2; GrossArea: 0.0215651 m2; CrossSectionArea: 0.000036 m2; NetVolume: 0.0000794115 m3; GrossVolume: 0.0000794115 m3

# IfcPlate: PL8*143, GOUSSET
In: Undefined
Description: PL8*143; Material: STEEL/S235JR
Pset_PlateCommon - Support de charge: no; Réference: 0(?)
Tekla Commun - Niveau bas: +156.450; Niveau haut: +156.458; Repère de pièce: 0(?); Repère d'assemblage: P0(?); Phase: 301; Classe: 99; Matériau: S235JR; Profil: PL8*143; Nom: GOUSSET
Tekla Quantités - Poids: 1.3 kg; Volume: 0 m3; Surface supérieure totale: 0 m2; Surface par tonne: 35.5 m2; Surface nette: 0 m2; Hauteur: 142.6 mm; Largeur: 8 mm; Longueur: 201.8 mm
BaseQuantities - Width: 142.592 mm; NetArea: 0.0467877 m2; GrossArea: 0.0287724 m2; CrossSectionArea: 0.000064 m2; NetVolume: 0.000167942 m3; GrossVolume: 0.000167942 m3

# IfcPlate: PL8*150, GOUSSET
In: Undefined
Description: PL8*150; Material: STEEL/S235JR
Pset_PlateCommon - Support de charge: no; Réference: 0(?)
Tekla Commun - Niveau bas: +156.450; Niveau haut: +156.458; Repère de pièce: 0(?); Repère d'assemblage: P0(?); Phase: 301; Classe: 99; Matériau: S235JR; Profil: PL8*150; Nom: GOUSSET
Tekla Quantités - Poids: 1.4 kg; Volume: 0 m3; Surface supérieure totale: 0 m2; Surface par tonne: 35.6 m2; Surface nette: 0 m2; Hauteur: 150.4 mm; Largeur: 8 mm; Longueur: 247.6 mm
BaseQuantities - Width: 150.364 mm; NetArea: 0.0494398 m2; GrossArea: 0.0372364 m2; CrossSectionArea: 0.000064 m2; NetVolume: 0.00017681 m3; GrossVolume: 0.00017681 m3

# IfcPlate: PL8*153, GOUSSET
In: Undefined
Description: PL8*153; Material: STEEL/S235JR
Pset_PlateCommon - Support de charge: no; Réference: 0(?)
Tekla Commun - Niveau bas: +156.450; Niveau haut: +156.458; Repère de pièce: 0(?); Repère d'assemblage: A0(?); Phase: 301; Classe: 99; Matériau: S235JR; Profil: PL8*153; Nom: GOUSSET
Tekla Quantités - Poids: 1.3 kg; Volume: 0 m3; Surface supérieure totale: 0 m2; Surface par tonne: 35.9 m2; Surface nette: 0 m2; Hauteur: 152.9 mm; Largeur: 8 mm; Longueur: 221.6 mm
BaseQuantities - Width: 152.941 mm; NetArea: 0.0444359 m2; GrossArea: 0.0338945 m2; CrossSectionArea: 0.000064 m2; NetVolume: 0.000157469 m3; GrossVolume: 0.000157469 m3

# IfcPlate: PL8*168, GOUSSET
In: Undefined
Description: PL8*168; Material: STEEL/S235JR
Pset_PlateCommon - Support de charge: no; Réference: 0(?)
Tekla Commun - Niveau bas: +156.450; Niveau haut: +156.458; Repère de pièce: 0(?); Repère d'assemblage: A0(?); Phase: 301; Classe: 99; Matériau: S235JR; Profil: PL8*168; Nom: GOUSSET
Tekla Quantités - Poids: 1.1 kg; Volume: 0 m3; Surface supérieure totale: 0 m2; Surface par tonne: 35.9 m2; Surface nette: 0 m2; Hauteur: 168.2 mm; Largeur: 8 mm; Longueur: 174.2 mm
BaseQuantities - Width: 168.241 mm; NetArea: 0.0406282 m2; GrossArea: 0.0293059 m2; CrossSectionArea: 0.000064 m2; NetVolume: 0.000143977 m3; GrossVolume: 0.000143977 m3

# IfcPlate: PL8*169, GOUSSET
In: Undefined
Description: PL8*169; Material: STEEL/S235JR
Tekla Commun - Niveau bas: +156.450; Niveau haut: +156.458; Repère de pièce: G0(?); Repère d'assemblage: G0(?); Phase: 301; Classe: 99; Matériau: S235JR; Profil: PL8*169; Nom: GOUSSET
Tekla Quantités - Poids: 3.1 kg; Volume: 0 m3; Surface supérieure totale: 0 m2; Surface par tonne: 34.3 m2; Surface nette: 0.1 m2; Hauteur: 168.8 mm; Largeur: 8 mm; Longueur: 410.4 mm
Pset_PlateCommon - Support de charge: no; Réference: G0(?)
BaseQuantities - Width: 168.771 mm; NetArea: 0.10761 m2; GrossArea: 0.0692678 m2; CrossSectionArea: 0.000064 m2; NetVolume: 0.000399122 m3; GrossVolume: 0.000399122 m3

# IfcPlate: PL8*170 (2)
In: Undefined
Description: PL8*170; Material: STEEL/S235JR
Pset_PlateCommon - Support de charge: no; Réference: 0(?)
Tekla Commun - Niveau bas: +156.450; Niveau haut: +156.458; Repère de pièce: 0(?); Repère d'assemblage: A0(?); Phase: 301; Classe: 99; Matériau: S235JR; Profil: PL8*170; Nom: GOUSSET
Tekla Quantités - Poids: 1.1 kg; Volume: 0 m3; Surface supérieure totale: 0 m2; Surface par tonne: 36 m2; Surface nette: 0 m2; Hauteur: 170.1 mm; Largeur: 8 mm; Longueur: 167.2 mm
BaseQuantities - Width: 170.059 mm; CrossSectionArea: 0.000064 m2
Name | NetArea (m2) | GrossArea (m2) | NetVolume (m3) = GrossVolume (m3)
GOUSSET | 0.0398869 | 0.0284324 | 0.000141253
GOUSSET | 0.0399012 | 0.028445 | 0.000141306

# IfcPlate: PL8*171, GOUSSET
In: Undefined
Description: PL8*171; Material: STEEL/S235JR
Pset_PlateCommon - Support de charge: no; Réference: 0(?)
Tekla Commun - Niveau bas: +156.450; Niveau haut: +156.458; Repère de pièce: 0(?); Repère d'assemblage: A0(?); Phase: 303; Classe: 99; Matériau: S235JR; Profil: PL8*171; Nom: GOUSSET
Tekla Quantités - Poids: 1.1 kg; Volume: 0 m3; Surface supérieure totale: 0 m2; Surface par tonne: 36 m2; Surface nette: 0 m2; Hauteur: 170.9 mm; Largeur: 8 mm; Longueur: 159.6 mm
BaseQuantities - Width: 170.934 mm; NetArea: 0.0387028 m2; GrossArea: 0.0272728 m2; CrossSectionArea: 0.000064 m2; NetVolume: 0.000136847 m3; GrossVolume: 0.000136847 m3

# IfcPlate: PL8*172, GOUSSET
In: Undefined
Description: PL8*172; Material: STEEL/S235JR
Tekla Commun - Niveau bas: +156.450; Niveau haut: +156.458; Repère de pièce: 0(?); Repère d'assemblage: A0(?); Phase: 303; Classe: 99; Matériau: S235JR; Profil: PL8*172; Nom: GOUSSET
Tekla Quantités - Poids: 1.1 kg; Volume: 0 m3; Surface supérieure totale: 0 m2; Surface par tonne: 36 m2; Surface nette: 0 m2; Hauteur: 171.8 mm; Largeur: 8 mm; Longueur: 160.1 mm
Pset_PlateCommon - Support de charge: no; Réference: 0(?)
BaseQuantities - Width: 171.781 mm; NetArea: 0.0390925 m2; GrossArea: 0.0274984 m2; CrossSectionArea: 0.000064 m2; NetVolume: 0.000138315 m3; GrossVolume: 0.000138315 m3

# IfcPlate: PL8*193, GOUSSET
In: Undefined
Description: PL8*193; Material: STEEL/S235JR
Pset_PlateCommon - Support de charge: no; Réference: G0(?)
Tekla Commun - Niveau bas: +156.450; Niveau haut: +156.458; Repère de pièce: G0(?); Repère d'assemblage: G0(?); Phase: 301; Classe: 99; Matériau: S235JR; Profil: PL8*193; Nom: GOUSSET
Tekla Quantités - Poids: 3.6 kg; Volume: 0 m3; Surface supérieure totale: 0.1 m2; Surface par tonne: 34.1 m2; Surface nette: 0.1 m2; Hauteur: 192.7 mm; Largeur: 8 mm; Longueur: 414.9 mm
BaseQuantities - Width: 192.674 mm; NetArea: 0.123412 m2; GrossArea: 0.0799381 m2; CrossSectionArea: 0.000064 m2; NetVolume: 0.00046126 m3; GrossVolume: 0.00046126 m3

# IfcSlab: 200*10805, DALLE
In: Undefined
Description: 200*10805; PredefinedType: FLOOR; Material: CONCRETE/C25/30
Pset_SlabCommon - LoadBearing: no; Reference: Da0(?)
Tekla Commun - Niveau bas: +151.100; Niveau haut: +151.300; Repère de pièce: Da0(?); Repère d'assemblage: Da0(?); Phase: 1401; Classe: 11; Matériau: C25/30; Profil: 200*10805; Nom: DALLE
Tekla Quantités - Poids: 85339.4 kg; Volume: 35.6 m3; Surface supérieure totale: 177.8 m2; Surface par tonne: 4.3 m2; Surface nette: 369.2 m2; Hauteur: 10805 mm; Largeur: 200 mm; Longueur: 23338.2 mm
BaseQuantities - Width: 200 mm; NetVolume: 35.5581 m3; NetArea: 177.791 m2; NetWeight: 85339.4 kg

# IfcSlab: 200*19500, DALLE
In: Undefined
Description: 200*19500; PredefinedType: FLOOR; Material: CONCRETE/C25/30
Pset_SlabCommon - LoadBearing: no; Reference: Da0(?)
Tekla Commun - Niveau bas: +147.730; Niveau haut: +147.930; Repère de pièce: Da0(?); Repère d'assemblage: Da0(?); Phase: 1401; Classe: 11; Matériau: C25/30; Profil: 200*19500; Nom: DALLE
Tekla Quantités - Poids: 130680 kg; Volume: 54.4 m3; Surface supérieure totale: 272.2 m2; Surface par tonne: 4.3 m2; Surface nette: 560.5 m2; Hauteur: 19500 mm; Largeur: 200 mm; Longueur: 20496 mm
BaseQuantities - Width: 200 mm; NetVolume: 54.4498 m3; NetArea: 272.249 m2; NetWeight: 130680 kg

# IfcSlab: 200*21083, DALLE
In: Undefined
Description: 200*21083; PredefinedType: FLOOR; Material: CONCRETE/C25/30
Pset_SlabCommon - LoadBearing: no; Reference: Da0(?)
Tekla Commun - Niveau bas: +147.800; Niveau haut: +148.000; Repère de pièce: Da0(?); Repère d'assemblage: Da0(?); Phase: 1401; Classe: 11; Matériau: C25/30; Profil: 200*21083; Nom: DALLE
Tekla Quantités - Poids: 217312 kg; Volume: 90.5 m3; Surface supérieure totale: 452.7 m2; Surface par tonne: 4.3 m2; Surface nette: 926.1 m2; Hauteur: 21082.6 mm; Largeur: 200 mm; Longueur: 32180 mm
BaseQuantities - Width: 200 mm; NetVolume: 90.5467 m3; NetArea: 452.734 m2; NetWeight: 217312 kg

# IfcSlab: 200*3224, DALLE
In: Undefined
Description: 200*3224; PredefinedType: FLOOR; Material: CONCRETE/C25/30
Pset_SlabCommon - LoadBearing: no; Reference: Da0(?)
Tekla Commun - Niveau bas: +147.660; Niveau haut: +147.860; Repère de pièce: Da0(?); Repère d'assemblage: Da0(?); Phase: 1401; Classe: 11; Matériau: C25/30; Profil: 200*3224; Nom: DALLE
Tekla Quantités - Poids: 30176.3 kg; Volume: 12.6 m3; Surface supérieure totale: 62.9 m2; Surface par tonne: 4.5 m2; Surface nette: 134.8 m2; Hauteur: 3224 mm; Largeur: 200 mm; Longueur: 19500 mm
BaseQuantities - Width: 200 mm; NetVolume: 12.5735 m3; NetArea: 62.8674 m2; NetWeight: 30176.3 kg

# IfcSlab: 200*4299, DALLE
In: Undefined
Description: 200*4299; PredefinedType: FLOOR; Material: CONCRETE/C25/30
Pset_SlabCommon - LoadBearing: no; Reference: Da0(?)
Tekla Commun - Niveau bas: +149.900; Niveau haut: +150.100; Repère de pièce: Da0(?); Repère d'assemblage: Da0(?); Phase: 1401; Classe: 11; Matériau: C25/30; Profil: 200*4299; Nom: DALLE
Tekla Quantités - Poids: 20288.9 kg; Volume: 8.6 m3; Surface supérieure totale: 42.3 m2; Surface par tonne: 4.5 m2; Surface nette: 90.2 m2; Hauteur: 4299.1 mm; Largeur: 200 mm; Longueur: 9831.9 mm
BaseQuantities - Width: 200 mm; NetVolume: 8.4537 m3; NetArea: 42.2685 m2; NetWeight: 20288.9 kg

# IfcSlab: 200*43450, DALLE
In: Undefined
Description: 200*43450; PredefinedType: FLOOR; Material: CONCRETE/C25/30
Pset_SlabCommon - LoadBearing: no; Reference: Da0(?)
Tekla Commun - Niveau bas: +153.200; Niveau haut: +153.400; Repère de pièce: Da0(?); Repère d'assemblage: Da0(?); Phase: 1401; Classe: 11; Matériau: C25/30; Profil: 200*43450; Nom: DALLE
Tekla Quantités - Poids: 462362 kg; Volume: 192.7 m3; Surface supérieure totale: 963.3 m2; Surface par tonne: 4.3 m2; Surface nette: 1958 m2; Hauteur: 43450 mm; Largeur: 200 mm; Longueur: 35220 mm
BaseQuantities - Width: 200 mm; NetVolume: 192.651 m3; NetArea: 963.253 m2; NetWeight: 462362 kg

# IfcSlab: 200*4699, DALLE
In: Undefined
Description: 200*4699; PredefinedType: FLOOR; Material: CONCRETE/C25/30
Pset_SlabCommon - LoadBearing: no; Reference: Da0(?)
Tekla Commun - Niveau bas: +147.400; Niveau haut: +147.600; Repère de pièce: Da0(?); Repère d'assemblage: Da0(?); Phase: 1401; Classe: 11; Matériau: C25/30; Profil: 200*4699; Nom: DALLE
Tekla Quantités - Poids: 22627.7 kg; Volume: 9.4 m3; Surface supérieure totale: 47.1 m2; Surface par tonne: 4.5 m2; Surface nette: 100.2 m2; Hauteur: 4699.1 mm; Largeur: 200 mm; Longueur: 10031.9 mm
BaseQuantities - Width: 200 mm; NetVolume: 9.42821 m3; NetArea: 47.1411 m2; NetWeight: 22627.7 kg

# IfcSlab: 200*5000, DALLE
In: Undefined
Description: 200*5000; PredefinedType: FLOOR; Material: CONCRETE/C25/30
Pset_SlabCommon - LoadBearing: no; Reference: Da0(?)
Tekla Commun - Niveau bas: +147.800; Niveau haut: +148.000; Repère de pièce: Da0(?); Repère d'assemblage: Da0(?); Phase: 1401; Classe: 11; Matériau: C25/30; Profil: 200*5000; Nom: DALLE
Tekla Quantités - Poids: 46800 kg; Volume: 19.5 m3; Surface supérieure totale: 97.5 m2; Surface par tonne: 4.5 m2; Surface nette: 204.7 m2; Hauteur: 5000 mm; Largeur: 200 mm; Longueur: 19500 mm
BaseQuantities - Width: 200 mm; NetVolume: 19.5 m3; NetArea: 97.5 m2; NetWeight: 46800 kg

# IfcSlab: 200*7660, DALLE
In: Undefined
Description: 200*7660; PredefinedType: FLOOR; Material: CONCRETE/C25/30
Pset_SlabCommon - LoadBearing: no; Reference: Da0(?)
Tekla Commun - Niveau bas: +147.800; Niveau haut: +148.000; Repère de pièce: Da0(?); Repère d'assemblage: Da0(?); Phase: 1401; Classe: 11; Matériau: C25/30; Profil: 200*7660; Nom: DALLE
Tekla Quantités - Poids: 34759 kg; Volume: 14.5 m3; Surface supérieure totale: 72.4 m2; Surface par tonne: 4.5 m2; Surface nette: 153 m2; Hauteur: 7659.6 mm; Largeur: 200 mm; Longueur: 14468.7 mm
BaseQuantities - Width: 200 mm; NetVolume: 14.4829 m3; NetArea: 72.4146 m2; NetWeight: 34759 kg

# IfcSlab: 200*8295, DALLE
In: Undefined
Description: 200*8295; PredefinedType: FLOOR; Material: CONCRETE/C25/30
Tekla Commun - Niveau bas: +150.700; Niveau haut: +150.900; Repère de pièce: Da0(?); Repère d'assemblage: Da0(?); Phase: 1401; Classe: 11; Matériau: C25/30; Profil: 200*8295; Nom: DALLE
Tekla Quantités - Poids: 92887.1 kg; Volume: 38.7 m3; Surface supérieure totale: 193.5 m2; Surface par tonne: 4.3 m2; Surface nette: 399.7 m2; Hauteur: 8295 mm; Largeur: 200 mm; Longueur: 23338.2 mm
Pset_SlabCommon - LoadBearing: no; Reference: Da0(?)
BaseQuantities - Width: 200 mm; NetVolume: 38.7029 m3; NetArea: 193.515 m2; NetWeight: 92887.1 kg

# IfcSlab: 230*12937, DALLE
In: Undefined
Description: 230*12937; PredefinedType: FLOOR; Material: CONCRETE/C25/30
Pset_SlabCommon - LoadBearing: no; Reference: Da0(?)
Tekla Commun - Niveau bas: +147.770; Niveau haut: +148.000; Repère de pièce: Da0(?); Repère d'assemblage: Da0(?); Phase: 1401; Classe: 11; Matériau: C25/30; Profil: 230*12937; Nom: DALLE
Tekla Quantités - Poids: 140543 kg; Volume: 58.6 m3; Surface supérieure totale: 254.6 m2; Surface par tonne: 3.7 m2; Surface nette: 524.2 m2; Hauteur: 12937 mm; Largeur: 230 mm; Longueur: 19714.2 mm
BaseQuantities - Width: 230 mm; NetVolume: 58.5594 m3; NetArea: 254.606 m2; NetWeight: 140543 kg

# IfcSlab: 250*13784, DALLE
In: Undefined
Description: 250*13784; PredefinedType: FLOOR; Material: CONCRETE/C25/30
Pset_SlabCommon - LoadBearing: no; Reference: Da0(?)
Tekla Commun - Niveau bas: +152.750; Niveau haut: +153.000; Repère de pièce: Da0(?); Repère d'assemblage: Da0(?); Phase: 1401; Classe: 11; Matériau: C25/30; Profil: 250*13784; Nom: DALLE
Tekla Quantités - Poids: 119321 kg; Volume: 49.7 m3; Surface supérieure totale: 198.9 m2; Surface par tonne: 3.5 m2; Surface nette: 412.3 m2; Hauteur: 13783.5 mm; Largeur: 250 mm; Longueur: 18034 mm
BaseQuantities - Width: 250 mm; NetVolume: 49.7172 m3; NetArea: 198.869 m2; NetWeight: 119321 kg

# IfcSlab: 250*14979, DALLE
In: Undefined
Description: 250*14979; PredefinedType: FLOOR; Material: CONCRETE/C25/30
Pset_SlabCommon - LoadBearing: no; Reference: Da0(?)
Tekla Commun - Niveau bas: +147.249; Niveau haut: +147.800; Repère de pièce: Da0(?); Repère d'assemblage: Da0(?); Phase: 1401; Classe: 11; Matériau: C25/30; Profil: 250*14979; Nom: DALLE
Tekla Quantités - Poids: 167735 kg; Volume: 69.9 m3; Surface supérieure totale: 0 m2; Surface par tonne: 3.5 m2; Surface nette: 579.2 m2; Hauteur: 14978.8 mm; Largeur: 250 mm; Longueur: 25200 mm
BaseQuantities - Width: 250 mm; NetVolume: 69.8894 m3; NetArea: 0 m2; NetWeight: 167735 kg

# IfcSlab: 300*20618, DALLE
In: Undefined
Description: 300*20618; PredefinedType: FLOOR; Material: CONCRETE/C25/30
Pset_SlabCommon - LoadBearing: no; Reference: Da0(?)
Tekla Commun - Niveau bas: +146.988; Niveau haut: +147.700; Repère de pièce: Da0(?); Repère d'assemblage: Da0(?); Phase: 1401; Classe: 11; Matériau: C25/30; Profil: 300*20618; Nom: DALLE
Tekla Quantités - Poids: 379287 kg; Volume: 158 m3; Surface supérieure totale: 0 m2; Surface par tonne: 2.9 m2; Surface nette: 1081.3 m2; Hauteur: 20617.9 mm; Largeur: 300 mm; Longueur: 25550 mm
BaseQuantities - Width: 300 mm; NetVolume: 158.036 m3; NetArea: 0 m2; NetWeight: 379287 kg

# IfcWall: 3300*360 (6)
In: Undefined
Description: 3300*360; Material: MISCELLANEOUS/ISOLANT
Pset_WallCommon - LoadBearing: no; Reference: PA0(?)
Tekla Commun - Niveau bas: +156.700; Niveau haut: +160.000; Repère de pièce: PA0(?); Repère d'assemblage: PA0(?); Phase: 1402; Classe: 1; Matériau: ISOLANT; Profil: 3300*360; Nom: PANNEAU
Tekla Quantités - Hauteur: 3300 mm; Largeur: 360 mm
Name | Poids (kg) | Volume (m3) | Surface supérieure totale (m2) | Surface par tonne (m2) | Surface nette (m2) | Longueur (mm) = Length (mm) | OuterSurfaceArea (m2) | NetVolume (m3) | NetWeight (kg)
PANNEAU | 1275.5 | 18.2 | 8.5 | 109.7 | 140 | 23520 | 139.982 | 18.2218 | 1275.52
PANNEAU | 1561.9 | 22.3 | 7.3 | 91.4 | 142.8 | 20296 | 142.751 | 22.3132 | 1561.93
PANNEAU | 1699.2 | 24.3 | 8.3 | 94.4 | 160.4 | 23160 | 160.387 | 24.2741 | 1699.19
PANNEAU | 937.1 | 13.4 | 5.5 | 104.1 | 97.5 | 15360 | 97.5312 | 13.3877 | 937.138
PANNEAU | 2132.4 | 30.5 | 9.2 | 90.3 | 192.5 | 35373 | 192.455 | 30.4633 | 2132.43
PANNEAU | 1569.9 | 22.4 | 7.5 | 91.4 | 143.7 | 20696 | 143.671 | 22.4268 | 1569.88

# IfcWall: 3300*75 (5)
In: Undefined
Description: 3300*75; Material: STEEL/S235JR
Pset_WallCommon - LoadBearing: no; Reference: PA0(?)
Tekla Commun - Niveau bas: +156.700; Niveau haut: +160.000; Repère de pièce: PA0(?); Repère d'assemblage: PA0(?); Phase: 1201; Classe: 1; Matériau: S235JR; Profil: 3300*75; Nom: PANNEAU
Tekla Quantités - Hauteur: 3300 mm; Largeur: 75 mm
Name | Poids (kg) = NetWeight (kg) | Volume (m3) | Surface supérieure totale (m2) | Surface par tonne (m2) | Surface nette (m2) | Longueur (mm) = Length (mm) | OuterSurfaceArea (m2) | NetVolume (m3)
PANNEAU | 40543.4 | 5.2 | 1.8 | 3.5 | 143.1 | 23595 | 143.111 | 5.16476
PANNEAU | 22739.6 | 2.9 | 1.2 | 3.6 | 82.1 | 15795 | 82.1363 | 2.89676
PANNEAU | 36677.2 | 4.7 | 1.6 | 3.5 | 128.6 | 20696 | 128.568 | 4.67226
PANNEAU | 30645.3 | 3.9 | 1.8 | 3.7 | 112.2 | 23955 | 112.241 | 3.90386
PANNEAU | 36491.4 | 4.7 | 1.5 | 3.5 | 127.9 | 20296 | 127.877 | 4.64859

# IfcWall: 3409*360, PANNEAU
In: Undefined
Description: 3409*360; Material: MISCELLANEOUS/ISOLANT
Pset_WallCommon - LoadBearing: no; Reference: PA0(?)
Tekla Commun - Niveau bas: +153.291; Niveau haut: +156.700; Repère de pièce: PA0(?); Repère d'assemblage: PA0(?); Phase: 1402; Classe: 1; Matériau: ISOLANT; Profil: 3409*360; Nom: PANNEAU
Tekla Quantités - Poids: 1340.1 kg; Volume: 19.1 m3; Surface supérieure totale: 8.5 m2; Surface par tonne: 108.3 m2; Surface nette: 145.2 m2; Hauteur: 3409 mm; Largeur: 360 mm; Longueur: 23520 mm
BaseQuantities - Length: 23520 mm; OuterSurfaceArea: 145.188 m2; NetVolume: 19.1447 m3; NetWeight: 1340.13 kg

# IfcWall: 3409*75, PANNEAU
In: Undefined
Description: 3409*75; Material: STEEL/S235JR
Pset_WallCommon - LoadBearing: no; Reference: PA0(?)
Tekla Commun - Niveau bas: +153.291; Niveau haut: +156.700; Repère de pièce: PA0(?); Repère d'assemblage: PA0(?); Phase: 1201; Classe: 1; Matériau: S235JR; Profil: 3409*75; Nom: PANNEAU
Tekla Quantités - Poids: 32182.6 kg; Volume: 4.1 m3; Surface supérieure totale: 1.8 m2; Surface par tonne: 3.7 m2; Surface nette: 117.5 m2; Hauteur: 3409 mm; Largeur: 75 mm; Longueur: 23955 mm
BaseQuantities - Length: 23955 mm; OuterSurfaceArea: 117.48 m2; NetVolume: 4.09969 m3; NetWeight: 32182.6 kg

# IfcWall: 4300*360 (7)
In: Undefined
Description: 4300*360; Material: MISCELLANEOUS/ISOLANT
Pset_WallCommon - LoadBearing: no; Reference: PA0(?)
Tekla Commun - Repère de pièce: PA0(?); Repère d'assemblage: PA0(?); Phase: 1402; Classe: 1; Matériau: ISOLANT; Profil: 4300*360; Nom: PANNEAU
Tekla Quantités - Hauteur: 4300 mm; Largeur: 360 mm
Name | Niveau bas | Niveau haut | Poids (kg) | Volume (m3) | Surface supérieure totale (m2) | Surface par tonne (m2) | Surface nette (m2) | Longueur (mm) = Length (mm) | OuterSurfaceArea (m2) | NetVolume (m3) | NetWeight (kg)
PANNEAU | +156.700 | +161.000 | 1847.8 | 26.4 | 7.6 | 98.1 | 181.2 | 22264.4 | 181.246 | 26.3977 | 1847.84
PANNEAU | +160.000 | +164.300 | 2852.8 | 40.8 | 15.8 | 99 | 282.3 | 43856 | 282.324 | 40.7541 | 2852.79
PANNEAU | +160.000 | +164.300 | 2073.4 | 29.6 | 7.3 | 88.8 | 184.1 | 20296 | 184.063 | 29.6198 | 2073.38
PANNEAU | +160.000 | +164.300 | 2282.8 | 32.6 | 8.3 | 90.9 | 207.4 | 23160 | 207.427 | 32.6117 | 2282.82
PANNEAU | +160.000 | +164.300 | 1405.1 | 20.1 | 5.5 | 96 | 134.8 | 15360 | 134.931 | 20.0729 | 1405.11
PANNEAU | +160.000 | +164.300 | 3523 | 50.3 | 12.7 | 90 | 317.1 | 35296 | 317.1 | 50.329 | 3523.03
PANNEAU | +160.000 | +164.300 | 2091.4 | 29.9 | 7.5 | 88.8 | 185.8 | 20696 | 185.783 | 29.8774 | 2091.42

# IfcWall: 4300*75 (6)
In: Undefined
Description: 4300*75; Material: STEEL/S235JR
Tekla Commun - Repère de pièce: PA0(?); Repère d'assemblage: PA0(?); Phase: 1201; Classe: 1; Matériau: S235JR; Profil: 4300*75; Nom: PANNEAU
Tekla Quantités - Hauteur: 4300 mm; Largeur: 75 mm
Pset_WallCommon - LoadBearing: no; Reference: PA0(?)
Name | Niveau bas | Niveau haut | Poids (kg) = NetWeight (kg) | Volume (m3) | Surface supérieure totale (m2) | Surface par tonne (m2) | Surface nette (m2) | Longueur (mm) = Length (mm) | OuterSurfaceArea (m2) | NetVolume (m3)
PANNEAU | +160.000 | +164.300 | 54434.9 | 6.9 | 1.8 | 3.5 | 190.5 | 23595 | 190.451 | 6.93439
PANNEAU | +160.000 | +164.300 | 33928.9 | 4.3 | 1.2 | 3.5 | 120.2 | 15795 | 120.201 | 4.32215
PANNEAU | +160.000 | +164.300 | 48862 | 6.2 | 1.6 | 3.5 | 170.1 | 20696 | 170.11 | 6.22446
PANNEAU | +156.700 | +161.000 | 43171.3 | 5.5 | 1.6 | 3.6 | 153.9 | 22264.4 | 153.861 | 5.49952
PANNEAU | +160.000 | +164.300 | 67751.1 | 8.6 | 3.3 | 3.6 | 241.9 | 44291 | 241.866 | 8.63072
PANNEAU | +160.000 | +164.300 | 48440.7 | 6.2 | 1.5 | 3.5 | 168.6 | 20296 | 168.619 | 6.17079

# IfcWall: 4600*360 (5)
In: Undefined
Description: 4600*360; Material: MISCELLANEOUS/ISOLANT
Pset_WallCommon - LoadBearing: no; Reference: PA0(?)
Tekla Commun - Niveau bas: +152.100; Niveau haut: +156.700; Repère de pièce: PA0(?); Repère d'assemblage: PA0(?); Phase: 1402; Classe: 1; Matériau: ISOLANT; Profil: 4600*360; Nom: PANNEAU
Tekla Quantités - Hauteur: 4600 mm; Largeur: 360 mm
Name | Poids (kg) | Volume (m3) | Surface supérieure totale (m2) | Surface par tonne (m2) | Surface nette (m2) | Longueur (mm) = Length (mm) | OuterSurfaceArea (m2) | NetVolume (m3) | NetWeight (kg)
PANNEAU | 2191.5 | 31.3 | 7.3 | 89.4 | 195.8 | 20296 | 195.816 | 31.3077 | 2191.54
PANNEAU | 2457.9 | 35.1 | 8.3 | 90.1 | 221.5 | 23160 | 221.539 | 35.113 | 2457.91
PANNEAU | 1440.3 | 20.6 | 5.5 | 96.1 | 138.4 | 15360 | 138.403 | 20.5762 | 1440.33
PANNEAU | 2976.9 | 42.5 | 10.2 | 90.3 | 268.9 | 28283 | 268.925 | 42.5275 | 2976.92
PANNEAU | 2247.9 | 32.1 | 7.5 | 89 | 200.1 | 20696 | 200.144 | 32.1126 | 2247.88

# IfcWall: 4600*75 (4)
In: Undefined
Description: 4600*75; Material: STEEL/S235JR
Pset_WallCommon - LoadBearing: no; Reference: PA0(?)
Tekla Commun - Niveau bas: +152.100; Niveau haut: +156.700; Repère de pièce: PA0(?); Repère d'assemblage: PA0(?); Phase: 1201; Classe: 1; Matériau: S235JR; Profil: 4600*75; Nom: PANNEAU
Tekla Quantités - Surface par tonne: 3.5 m2; Hauteur: 4600 mm; Largeur: 75 mm
Name | Poids (kg) = NetWeight (kg) | Volume (m3) | Surface supérieure totale (m2) | Surface nette (m2) | Longueur (mm) = Length (mm) | OuterSurfaceArea (m2) | NetVolume (m3)
PANNEAU | 58602.4 | 7.5 | 1.8 | 204.7 | 23595 | 204.653 | 7.46527
PANNEAU | 34828.7 | 4.4 | 1.2 | 123.4 | 15795 | 123.398 | 4.43678
PANNEAU | 52517.4 | 6.7 | 1.6 | 182.9 | 20696 | 182.933 | 6.69012
PANNEAU | 51201.2 | 6.5 | 1.5 | 178.5 | 20296 | 178.491 | 6.52245

# IfcWall: 5340*200, PANNEAU
In: Undefined
Description: 5340*200; Material: CONCRETE/C25/30
Pset_WallCommon - LoadBearing: no; Reference: PA0(?)
Tekla Commun - Niveau bas: +147.860; Niveau haut: +153.200; Repère de pièce: PA0(?); Repère d'assemblage: PA0(?); Phase: 1401; Classe: 1; Matériau: C25/30; Profil: 5340*200; Nom: PANNEAU
Tekla Quantités - Poids: 100885 kg; Volume: 42 m3; Surface supérieure totale: 8.5 m2; Surface par tonne: 4.5 m2; Surface nette: 448.5 m2; Hauteur: 5340 mm; Largeur: 200 mm; Longueur: 42820 mm
BaseQuantities - Length: 42820 mm; OuterSurfaceArea: 448.539 m2; NetVolume: 42.0355 m3; NetWeight: 100885 kg

# IfcWall: 5400*200, PANNEAU
In: Undefined
Description: 5400*200; Material: CONCRETE/C25/30
Pset_WallCommon - LoadBearing: no; Reference: PA0(?)
Tekla Commun - Niveau bas: +148.000; Niveau haut: +153.400; Repère de pièce: PA0(?); Repère d'assemblage: PA0(?); Phase: 1401; Classe: 1; Matériau: C25/30; Profil: 5400*200; Nom: PANNEAU
Tekla Quantités - Poids: 56028 kg; Volume: 23.3 m3; Surface supérieure totale: 5.3 m2; Surface par tonne: 4.5 m2; Surface nette: 249.9 m2; Hauteur: 5400 mm; Largeur: 200 mm; Longueur: 26560.8 mm
BaseQuantities - Length: 26560.8 mm; OuterSurfaceArea: 249.914 m2; NetVolume: 23.345 m3; NetWeight: 56028 kg

# IfcWall: 5407*350, PANNEAU
In: Undefined
Description: 5407*350; Material: CONCRETE/C25/30
Pset_WallCommon - LoadBearing: no; Reference: PA0(?)
Tekla Commun - Niveau bas: +147.793; Niveau haut: +153.200; Repère de pièce: PA0(?); Repère d'assemblage: PA0(?); Phase: 1401; Classe: 1; Matériau: C25/30; Profil: 5407*350; Nom: PANNEAU; sets with these values: 2
Tekla Quantités - Poids: 89708 kg; Volume: 37.4 m3; Surface supérieure totale: 6.9 m2; Surface par tonne: 2.6 m2; Surface nette: 231.2 m2; Hauteur: 5407 mm; Largeur: 350 mm; Longueur: 19751.3 mm; sets with these values: 2
BaseQuantities - Length: 19751.3 mm; OuterSurfaceArea: 231.201 m2; NetVolume: 37.3783 m3; NetWeight: 89708 kg; Width: 350 mm; GrossFootprintArea: 6.91295 m2

# IfcWall: 5440*200, PANNEAU
In: Undefined
Description: 5440*200; Material: CONCRETE/C25/30
Pset_WallCommon - LoadBearing: no; Reference: PA0(?)
Tekla Commun - Niveau bas: +147.760; Niveau haut: +153.200; Repère de pièce: PA0(?); Repère d'assemblage: PA0(?); Phase: 1401; Classe: 1; Matériau: C25/30; Profil: 5440*200; Nom: PANNEAU
Tekla Quantités - Poids: 36358.4 kg; Volume: 15.1 m3; Surface supérieure totale: 2.8 m2; Surface par tonne: 4.5 m2; Surface nette: 159.2 m2; Hauteur: 5440 mm; Largeur: 200 mm; Longueur: 13924 mm
BaseQuantities - Length: 13924 mm; OuterSurfaceArea: 159.239 m2; NetVolume: 15.1493 m3; NetWeight: 36358.4 kg

# IfcWall: 5600*200 (2)
In: Undefined
Description: 5600*200; Material: CONCRETE/C25/30
Pset_WallCommon - LoadBearing: no; Reference: PA0(?)
Tekla Commun - Niveau bas: +147.600; Niveau haut: +153.200; Repère de pièce: PA0(?); Repère d'assemblage: PA0(?); Phase: 1401; Classe: 1; Matériau: C25/30; Profil: 5600*200; Nom: PANNEAU
Tekla Quantités - Surface par tonne: 4.5 m2; Hauteur: 5600 mm; Largeur: 200 mm
Name | Poids (kg) = NetWeight (kg) | Volume (m3) | Surface supérieure totale (m2) | Surface nette (m2) | Longueur (mm) = Length (mm) | OuterSurfaceArea (m2) | NetVolume (m3)
PANNEAU | 35804.2 | 14.9 | 3.1 | 162.3 | 15520 | 162.288 | 14.9184
PANNEAU | 36957 | 15.4 | 2.9 | 164 | 14531 | 164.016 | 15.3988
